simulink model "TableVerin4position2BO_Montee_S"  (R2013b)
settings: Solver=ode15s  StartTime=0.0  StopTime=20  RelTol=1e-3
undefined symbols (not defined in the file): deg, kg, m, mm, N, rad, s, X, Y, Z
libraries: sm_lib x907, fl_lib x19, nesl_utility x13, elec_lib x3, sdl_lib x2
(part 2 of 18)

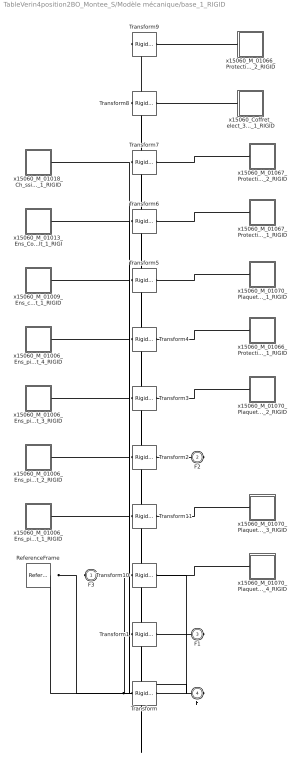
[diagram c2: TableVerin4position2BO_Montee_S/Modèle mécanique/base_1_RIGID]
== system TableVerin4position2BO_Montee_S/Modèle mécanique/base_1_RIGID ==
  ReferenceFrame : sm_lib/Frames and Transforms/Reference Frame  BlockFunction=simmechanics.library.frames_transforms.reference_frame
  Transform : sm_lib/Frames and Transforms/Rigid Transform  TranslationMethod=Cartesian  TranslationLengthUnit=mm  TranslationStandardAxis=+Z  TranslationStandardOffset=0  TranslationCartesianOffset=[-1242 73.964999999999918 -35]  TranslationROffset=0  TranslationROffsetUnits=m  TranslationZOffset=0  TranslationZOffsetUnits=m  TranslationThetaOffset=0  TranslationThetaOffsetUnits=deg  RotationMethod=ArbitraryAxis  RotationAngleUnits=rad  RotationStandardAxis=+Z  RotationAngle=2.0943951023931953  RotationArbitraryAxis=[-0.57735026918962562 -0.57735026918962595 -0.57735026918962562]  FollAlignAxisA=+X  BaseAlignAxisA=+Y  FollAlignAxisB=+Y  BaseAlignAxisB=+Z  BlockFunction=simmechanics.library.frames_transforms.rigid_transform
  Transform1 : sm_lib/Frames and Transforms/Rigid Transform  TranslationMethod=Cartesian  TranslationLengthUnit=mm  TranslationStandardAxis=+Z  TranslationStandardOffset=0  TranslationCartesianOffset=[-1320 -193.8074 -14.000000000000002]  TranslationROffset=0  TranslationROffsetUnits=m  TranslationZOffset=0  TranslationZOffsetUnits=m  TranslationThetaOffset=0  TranslationThetaOffsetUnits=deg  RotationMethod=ArbitraryAxis  RotationAngleUnits=rad  RotationStandardAxis=+Z  RotationAngle=2.0943951023931953  RotationArbitraryAxis=[0.57735026918962584 -0.57735026918962584 0.57735026918962584]  FollAlignAxisA=+X  BaseAlignAxisA=+Y  FollAlignAxisB=+Y  BaseAlignAxisB=+Z  BlockFunction=simmechanics.library.frames_transforms.rigid_transform
  Transform10 : sm_lib/Frames and Transforms/Rigid Transform  TranslationMethod=Cartesian  TranslationLengthUnit=mm  TranslationStandardAxis=+Z  TranslationStandardOffset=0  TranslationCartesianOffset=[-200 -325 -60]  TranslationROffset=0  TranslationROffsetUnits=m  TranslationZOffset=0  TranslationZOffsetUnits=m  TranslationThetaOffset=0  TranslationThetaOffsetUnits=deg  RotationMethod=ArbitraryAxis  RotationAngleUnits=rad  RotationStandardAxis=+Z  RotationAngle=3.1415926535897891  RotationArbitraryAxis=[0 1 0]  FollAlignAxisA=+X  BaseAlignAxisA=+Y  FollAlignAxisB=+Y  BaseAlignAxisB=+Z  BlockFunction=simmechanics.library.frames_transforms.rigid_transform
  Transform11 : sm_lib/Frames and Transforms/Rigid Transform  TranslationMethod=Cartesian  TranslationLengthUnit=mm  TranslationStandardAxis=+Z  TranslationStandardOffset=0  TranslationCartesianOffset=[-200 215 -60]  TranslationROffset=0  TranslationROffsetUnits=m  TranslationZOffset=0  TranslationZOffsetUnits=m  TranslationThetaOffset=0  TranslationThetaOffsetUnits=deg  RotationMethod=ArbitraryAxis  RotationAngleUnits=rad  RotationStandardAxis=+Z  RotationAngle=3.1415926535897891  RotationArbitraryAxis=[0 1 0]  FollAlignAxisA=+X  BaseAlignAxisA=+Y  FollAlignAxisB=+Y  BaseAlignAxisB=+Z  BlockFunction=simmechanics.library.frames_transforms.rigid_transform
  Transform2 : sm_lib/Frames and Transforms/Rigid Transform  TranslationMethod=Cartesian  TranslationLengthUnit=mm  TranslationStandardAxis=+Z  TranslationStandardOffset=0  TranslationCartesianOffset=[-1400 -138.965 121.00000000000195]  TranslationROffset=0  TranslationROffsetUnits=m  TranslationZOffset=0  TranslationZOffsetUnits=m  TranslationThetaOffset=0  TranslationThetaOffsetUnits=deg  RotationMethod=ArbitraryAxis  RotationAngleUnits=rad  RotationStandardAxis=+Z  RotationAngle=2.0943951023931953  RotationArbitraryAxis=[0.57735026918962584 -0.57735026918962584 0.57735026918962584]  FollAlignAxisA=+X  BaseAlignAxisA=+Y  FollAlignAxisB=+Y  BaseAlignAxisB=+Z  BlockFunction=simmechanics.library.frames_transforms.rigid_transform
  Transform3 : sm_lib/Frames and Transforms/Rigid Transform  TranslationMethod=Cartesian  TranslationLengthUnit=mm  TranslationStandardAxis=+Z  TranslationStandardOffset=0  TranslationCartesianOffset=[-550 -325 -60]  TranslationROffset=0  TranslationROffsetUnits=m  TranslationZOffset=0  TranslationZOffsetUnits=m  TranslationThetaOffset=0  TranslationThetaOffsetUnits=deg  RotationMethod=ArbitraryAxis  RotationAngleUnits=rad  RotationStandardAxis=+Z  RotationAngle=3.1415926535897931  RotationArbitraryAxis=[1 -6.2449999999999997e-17 0]  FollAlignAxisA=+X  BaseAlignAxisA=+Y  FollAlignAxisB=+Y  BaseAlignAxisB=+Z  BlockFunction=simmechanics.library.frames_transforms.rigid_transform
  Transform4 : sm_lib/Frames and Transforms/Rigid Transform  TranslationMethod=Cartesian  TranslationLengthUnit=mm  TranslationStandardAxis=+Z  TranslationStandardOffset=0  TranslationCartesianOffset=[-1740 -415 31]  TranslationROffset=0  TranslationROffsetUnits=m  TranslationZOffset=0  TranslationZOffsetUnits=m  TranslationThetaOffset=0  TranslationThetaOffsetUnits=deg  RotationMethod=None  RotationAngleUnits=deg  RotationStandardAxis=+Z  RotationAngle=0  RotationArbitraryAxis=[0 0 1]  FollAlignAxisA=+X  BaseAlignAxisA=+Y  FollAlignAxisB=+Y  BaseAlignAxisB=+Z  BlockFunction=simmechanics.library.frames_transforms.rigid_transform
  Transform5 : sm_lib/Frames and Transforms/Rigid Transform  TranslationMethod=Cartesian  TranslationLengthUnit=mm  TranslationStandardAxis=+Z  TranslationStandardOffset=0  TranslationCartesianOffset=[-550 215 -60]  TranslationROffset=0  TranslationROffsetUnits=m  TranslationZOffset=0  TranslationZOffsetUnits=m  TranslationThetaOffset=0  TranslationThetaOffsetUnits=deg  RotationMethod=ArbitraryAxis  RotationAngleUnits=rad  RotationStandardAxis=+Z  RotationAngle=3.1415926535897896  RotationArbitraryAxis=[-1 -0 -1.99581e-15]  FollAlignAxisA=+X  BaseAlignAxisA=+Y  FollAlignAxisB=+Y  BaseAlignAxisB=+Z  BlockFunction=simmechanics.library.frames_transforms.rigid_transform
  Transform6 : sm_lib/Frames and Transforms/Rigid Transform  TranslationMethod=Cartesian  TranslationLengthUnit=mm  TranslationStandardAxis=+Z  TranslationStandardOffset=0  TranslationCartesianOffset=[20 -415 31]  TranslationROffset=0  TranslationROffsetUnits=m  TranslationZOffset=0  TranslationZOffsetUnits=m  TranslationThetaOffset=0  TranslationThetaOffsetUnits=deg  RotationMethod=ArbitraryAxis  RotationAngleUnits=rad  RotationStandardAxis=+Z  RotationAngle=3.1415926535897931  RotationArbitraryAxis=[0 -1.9146e-15 1]  FollAlignAxisA=+X  BaseAlignAxisA=+Y  FollAlignAxisB=+Y  BaseAlignAxisB=+Z  BlockFunction=simmechanics.library.frames_transforms.rigid_transform
  Transform7 : sm_lib/Frames and Transforms/Rigid Transform  TranslationMethod=Cartesian  TranslationLengthUnit=mm  TranslationStandardAxis=+Z  TranslationStandardOffset=0  TranslationCartesianOffset=[-1740 415 31]  TranslationROffset=0  TranslationROffsetUnits=m  TranslationZOffset=0  TranslationZOffsetUnits=m  TranslationThetaOffset=0  TranslationThetaOffsetUnits=deg  RotationMethod=None  RotationAngleUnits=deg  RotationStandardAxis=+Z  RotationAngle=0  RotationArbitraryAxis=[0 0 1]  FollAlignAxisA=+X  BaseAlignAxisA=+Y  FollAlignAxisB=+Y  BaseAlignAxisB=+Z  BlockFunction=simmechanics.library.frames_transforms.rigid_transform
  Transform8 : sm_lib/Frames and Transforms/Rigid Transform  TranslationMethod=Cartesian  TranslationLengthUnit=mm  TranslationStandardAxis=+Z  TranslationStandardOffset=0  TranslationCartesianOffset=[-760 275 -60]  TranslationROffset=0  TranslationROffsetUnits=m  TranslationZOffset=0  TranslationZOffsetUnits=m  TranslationThetaOffset=0  TranslationThetaOffsetUnits=deg  RotationMethod=ArbitraryAxis  RotationAngleUnits=rad  RotationStandardAxis=+Z  RotationAngle=1.5707963267948968  RotationArbitraryAxis=[-5.5510999999999988e-17 5.5510999999999988e-17 1]  FollAlignAxisA=+X  BaseAlignAxisA=+Y  FollAlignAxisB=+Y  BaseAlignAxisB=+Z  BlockFunction=simmechanics.library.frames_transforms.rigid_transform
  Transform9 : sm_lib/Frames and Transforms/Rigid Transform  TranslationMethod=Cartesian  TranslationLengthUnit=mm  TranslationStandardAxis=+Z  TranslationStandardOffset=0  TranslationCartesianOffset=[20 415 31]  TranslationROffset=0  TranslationROffsetUnits=m  TranslationZOffset=0  TranslationZOffsetUnits=m  TranslationThetaOffset=0  TranslationThetaOffsetUnits=deg  RotationMethod=ArbitraryAxis  RotationAngleUnits=rad  RotationStandardAxis=+Z  RotationAngle=3.1415926535897931  RotationArbitraryAxis=[0 -1.6751650000000001e-15 1]  FollAlignAxisA=+X  BaseAlignAxisA=+Y  FollAlignAxisB=+Y  BaseAlignAxisB=+Z  BlockFunction=simmechanics.library.frames_transforms.rigid_transform
  x15060_Coffret_elect_300_X_150_H_150_AA_DEFAULT_1_RIGID : Subsystem
  x15060_M_01006_Ens_pied_escamotable_Default_1_RIGID : Subsystem
  x15060_M_01006_Ens_pied_escamotable_Default_2_RIGID : Subsystem
  x15060_M_01006_Ens_pied_escamotable_Default_3_RIGID : Subsystem
  x15060_M_01006_Ens_pied_escamotable_Default_4_RIGID : Subsystem
  x15060_M_01009_Ens_chassis_inf_Default_1_RIGID : Subsystem
  x15060_M_01013_Ens_Coffret_electrique_sous_table_Default_1_RIGI : Subsystem
  x15060_M_01018_Ch_ssis_bas_1_RIGID : Subsystem
  x15060_M_01066_Protection_capteur_pied_AA_DEFAULT_1_RIGID : Subsystem
  x15060_M_01066_Protection_capteur_pied_AA_DEFAULT_2_RIGID : Subsystem
  x15060_M_01067_Protection_capteur_pied_SYM_AA_DEFAULT_1_RIGID : Subsystem
  x15060_M_01067_Protection_capteur_pied_SYM_AA_DEFAULT_2_RIGID : Subsystem
  x15060_M_01070_Plaquette_porte_coffret_elect_AA_DEFAULT_1_RIGID : Subsystem
  x15060_M_01070_Plaquette_porte_coffret_elect_AA_DEFAULT_2_RIGID : Subsystem
  x15060_M_01070_Plaquette_porte_coffret_elect_AA_DEFAULT_3_RIGID : Subsystem
  x15060_M_01070_Plaquette_porte_coffret_elect_AA_DEFAULT_4_RIGID : Subsystem
  F3 : PMIOPort  Port=1  Side=Left
  F2 : PMIOPort  Port=2  Side=Right
  F1 : PMIOPort  Port=3  Side=Right
  F : PMIOPort  Port=4  Side=Right
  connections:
  Transform/LConn1 -- ReferenceFrame/RConn1 -- Transform1/LConn1 -- Transform10/LConn1 -- Transform11/LConn1 -- Transform2/LConn1 -- Transform3/LConn1 -- Transform4/LConn1 -- Transform5/LConn1 -- Transform6/LConn1 -- Transform7/LConn1 -- Transform8/LConn1 -- Transform9/LConn1 -- x15060_M_01006_Ens_pied_escamotable_Default_1_RIGID/RConn1 -- x15060_M_01006_Ens_pied_escamotable_Default_2_RIGID/RConn1 -- x15060_M_01006_Ens_pied_escamotable_Default_3_RIGID/RConn1 -- x15060_M_01006_Ens_pied_escamotable_Default_4_RIGID/RConn1 -- x15060_M_01009_Ens_chassis_inf_Default_1_RIGID/RConn1 -- x15060_M_01013_Ens_Coffret_electrique_sous_table_Default_1_RIGI/RConn1 -- x15060_M_01018_Ch_ssis_bas_1_RIGID/RConn1 -- F3/RConn1
  Transform/RConn1 -- F/RConn1
  Transform9/RConn1 -- x15060_M_01066_Protection_capteur_pied_AA_DEFAULT_2_RIGID/LConn1
  Transform10/RConn1 -- x15060_M_01070_Plaquette_porte_coffret_elect_AA_DEFAULT_4_RIGID/LConn1
  Transform11/RConn1 -- x15060_M_01070_Plaquette_porte_coffret_elect_AA_DEFAULT_3_RIGID/LConn1
  Transform1/RConn1 -- F1/RConn1
  Transform2/RConn1 -- F2/RConn1
  Transform3/RConn1 -- x15060_M_01070_Plaquette_porte_coffret_elect_AA_DEFAULT_2_RIGID/LConn1
  Transform4/RConn1 -- x15060_M_01066_Protection_capteur_pied_AA_DEFAULT_1_RIGID/LConn1
  Transform5/RConn1 -- x15060_M_01070_Plaquette_porte_coffret_elect_AA_DEFAULT_1_RIGID/LConn1
  Transform6/RConn1 -- x15060_M_01067_Protection_capteur_pied_SYM_AA_DEFAULT_1_RIGID/LConn1
  Transform7/RConn1 -- x15060_M_01067_Protection_capteur_pied_SYM_AA_DEFAULT_2_RIGID/LConn1
  Transform8/RConn1 -- x15060_Coffret_elect_300_X_150_H_150_AA_DEFAULT_1_RIGID/LConn1

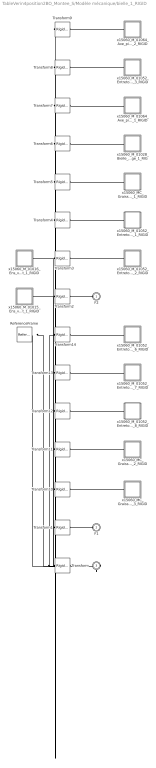
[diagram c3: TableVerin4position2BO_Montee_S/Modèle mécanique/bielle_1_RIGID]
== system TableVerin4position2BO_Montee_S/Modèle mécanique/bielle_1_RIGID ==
  ReferenceFrame : sm_lib/Frames and Transforms/Reference Frame  BlockFunction=simmechanics.library.frames_transforms.reference_frame
  Transform : sm_lib/Frames and Transforms/Rigid Transform  TranslationMethod=Cartesian  TranslationLengthUnit=mm  TranslationStandardAxis=+Z  TranslationStandardOffset=0  TranslationCartesianOffset=[-316.26699999999994 -140.96499999999997 350]  TranslationROffset=0  TranslationROffsetUnits=m  TranslationZOffset=0  TranslationZOffsetUnits=m  TranslationThetaOffset=0  TranslationThetaOffsetUnits=deg  RotationMethod=ArbitraryAxis  RotationAngleUnits=rad  RotationStandardAxis=+Z  RotationAngle=2.0943951023931957  RotationArbitraryAxis=[0.57735026918962584 -0.57735026918962573 0.57735026918962573]  FollAlignAxisA=+X  BaseAlignAxisA=+Y  FollAlignAxisB=+Y  BaseAlignAxisB=+Z  BlockFunction=simmechanics.library.frames_transforms.rigid_transform
  Transform1 : sm_lib/Frames and Transforms/Rigid Transform  TranslationMethod=Cartesian  TranslationLengthUnit=mm  TranslationStandardAxis=+Z  TranslationStandardOffset=0  TranslationCartesianOffset=[-778.76007754271018 -139.46500000002229 0.00028965769951128095]  TranslationROffset=0  TranslationROffsetUnits=m  TranslationZOffset=0  TranslationZOffsetUnits=m  TranslationThetaOffset=0  TranslationThetaOffsetUnits=deg  RotationMethod=ArbitraryAxis  RotationAngleUnits=rad  RotationStandardAxis=+Z  RotationAngle=2.0943951023931953  RotationArbitraryAxis=[0.57735026918962584 -0.57735026918962584 0.57735026918962584]  FollAlignAxisA=+X  BaseAlignAxisA=+Y  FollAlignAxisB=+Y  BaseAlignAxisB=+Z  BlockFunction=simmechanics.library.frames_transforms.rigid_transform
  Transform10 : sm_lib/Frames and Transforms/Rigid Transform  TranslationMethod=Cartesian  TranslationLengthUnit=mm  TranslationStandardAxis=+Z  TranslationStandardOffset=0  TranslationCartesianOffset=[-785.096 9.7691999999999992e-12 8.3727200000000011]  TranslationROffset=0  TranslationROffsetUnits=m  TranslationZOffset=0  TranslationZOffsetUnits=m  TranslationThetaOffset=0  TranslationThetaOffsetUnits=deg  RotationMethod=ArbitraryAxis  RotationAngleUnits=rad  RotationStandardAxis=+Z  RotationAngle=2.4013188770426868  RotationArbitraryAxis=[0.70267924249142677 -0.65170522453176793 -0.28552089676532016]  FollAlignAxisA=+X  BaseAlignAxisA=+Y  FollAlignAxisB=+Y  BaseAlignAxisB=+Z  BlockFunction=simmechanics.library.frames_transforms.rigid_transform
  Transform11 : sm_lib/Frames and Transforms/Rigid Transform  TranslationMethod=Cartesian  TranslationLengthUnit=mm  TranslationStandardAxis=+Z  TranslationStandardOffset=0  TranslationCartesianOffset=[-310.23200000000003 -73 342.02600000000001]  TranslationROffset=0  TranslationROffsetUnits=m  TranslationZOffset=0  TranslationZOffsetUnits=m  TranslationThetaOffset=0  TranslationThetaOffsetUnits=deg  RotationMethod=ArbitraryAxis  RotationAngleUnits=rad  RotationStandardAxis=+Z  RotationAngle=2.9102018676527228  RotationArbitraryAxis=[-0.51648054719757408 -0.70231547164023367 0.48989878818103916]  FollAlignAxisA=+X  BaseAlignAxisA=+Y  FollAlignAxisB=+Y  BaseAlignAxisB=+Z  BlockFunction=simmechanics.library.frames_transforms.rigid_transform
  Transform12 : sm_lib/Frames and Transforms/Rigid Transform  TranslationMethod=Cartesian  TranslationLengthUnit=mm  TranslationStandardAxis=+Z  TranslationStandardOffset=0  TranslationCartesianOffset=[-316.267 105.5 350]  TranslationROffset=0  TranslationROffsetUnits=m  TranslationZOffset=0  TranslationZOffsetUnits=m  TranslationThetaOffset=0  TranslationThetaOffsetUnits=deg  RotationMethod=ArbitraryAxis  RotationAngleUnits=rad  RotationStandardAxis=+Z  RotationAngle=2.793539492072322  RotationArbitraryAxis=[-0.69609360831745681 -0.6960936083174567 0.17580493997372784]  FollAlignAxisA=+X  BaseAlignAxisA=+Y  FollAlignAxisB=+Y  BaseAlignAxisB=+Z  BlockFunction=simmechanics.library.frames_transforms.rigid_transform
  Transform13 : sm_lib/Frames and Transforms/Rigid Transform  TranslationMethod=Cartesian  TranslationLengthUnit=mm  TranslationStandardAxis=+Z  TranslationStandardOffset=0  TranslationCartesianOffset=[-778.75999999999999 -106.5 -8.5598199999999999e-10]  TranslationROffset=0  TranslationROffsetUnits=m  TranslationZOffset=0  TranslationZOffsetUnits=m  TranslationThetaOffset=0  TranslationThetaOffsetUnits=deg  RotationMethod=ArbitraryAxis  RotationAngleUnits=rad  RotationStandardAxis=+Z  RotationAngle=2.793539492072322  RotationArbitraryAxis=[-0.69609360831745681 -0.6960936083174567 0.17580493997372784]  FollAlignAxisA=+X  BaseAlignAxisA=+Y  FollAlignAxisB=+Y  BaseAlignAxisB=+Z  BlockFunction=simmechanics.library.frames_transforms.rigid_transform
  Transform14 : sm_lib/Frames and Transforms/Rigid Transform  TranslationMethod=Cartesian  TranslationLengthUnit=mm  TranslationStandardAxis=+Z  TranslationStandardOffset=0  TranslationCartesianOffset=[-316.267 -27 350]  TranslationROffset=0  TranslationROffsetUnits=m  TranslationZOffset=0  TranslationZOffsetUnits=m  TranslationThetaOffset=0  TranslationThetaOffsetUnits=deg  RotationMethod=ArbitraryAxis  RotationAngleUnits=rad  RotationStandardAxis=+Z  RotationAngle=1.631639801857675  RotationArbitraryAxis=[-0.2394170303444268 -0.2394170303444268 0.94093515778830983]  FollAlignAxisA=+X  BaseAlignAxisA=+Y  FollAlignAxisB=+Y  BaseAlignAxisB=+Z  BlockFunction=simmechanics.library.frames_transforms.rigid_transform
  Transform2 : sm_lib/Frames and Transforms/Rigid Transform  TranslationMethod=Cartesian  TranslationLengthUnit=mm  TranslationStandardAxis=+Z  TranslationStandardOffset=0  TranslationCartesianOffset=[-316.267 127 350]  TranslationROffset=0  TranslationROffsetUnits=m  TranslationZOffset=0  TranslationZOffsetUnits=m  TranslationThetaOffset=0  TranslationThetaOffsetUnits=deg  RotationMethod=ArbitraryAxis  RotationAngleUnits=rad  RotationStandardAxis=+Z  RotationAngle=2.0943951023931957  RotationArbitraryAxis=[0.57735026918962584 -0.57735026918962573 0.57735026918962573]  FollAlignAxisA=+X  BaseAlignAxisA=+Y  FollAlignAxisB=+Y  BaseAlignAxisB=+Z  BlockFunction=simmechanics.library.frames_transforms.rigid_transform
  Transform3 : sm_lib/Frames and Transforms/Rigid Transform  TranslationMethod=Cartesian  TranslationLengthUnit=mm  TranslationStandardAxis=+Z  TranslationStandardOffset=0  TranslationCartesianOffset=[-778.75999999999999 105.5 -8.5609299999999991e-10]  TranslationROffset=0  TranslationROffsetUnits=m  TranslationZOffset=0  TranslationZOffsetUnits=m  TranslationThetaOffset=0  TranslationThetaOffsetUnits=deg  RotationMethod=ArbitraryAxis  RotationAngleUnits=rad  RotationStandardAxis=+Z  RotationAngle=2.8057551749822172  RotationArbitraryAxis=[-0.69687325454044569 -0.69687325454044569 0.16951499701328632]  FollAlignAxisA=+X  BaseAlignAxisA=+Y  FollAlignAxisB=+Y  BaseAlignAxisB=+Z  BlockFunction=simmechanics.library.frames_transforms.rigid_transform
  Transform4 : sm_lib/Frames and Transforms/Rigid Transform  TranslationMethod=Cartesian  TranslationLengthUnit=mm  TranslationStandardAxis=+Z  TranslationStandardOffset=0  TranslationCartesianOffset=[-316.267 -50.5 350]  TranslationROffset=0  TranslationROffsetUnits=m  TranslationZOffset=0  TranslationZOffsetUnits=m  TranslationThetaOffset=0  TranslationThetaOffsetUnits=deg  RotationMethod=ArbitraryAxis  RotationAngleUnits=rad  RotationStandardAxis=+Z  RotationAngle=1.631639801857675  RotationArbitraryAxis=[-0.2394170303444268 -0.2394170303444268 0.94093515778830983]  FollAlignAxisA=+X  BaseAlignAxisA=+Y  FollAlignAxisB=+Y  BaseAlignAxisB=+Z  BlockFunction=simmechanics.library.frames_transforms.rigid_transform
  Transform5 : sm_lib/Frames and Transforms/Rigid Transform  TranslationMethod=Cartesian  TranslationLengthUnit=mm  TranslationStandardAxis=+Z  TranslationStandardOffset=0  TranslationCartesianOffset=[-310.23200000000003 73 342.02600000000001]  TranslationROffset=0  TranslationROffsetUnits=m  TranslationZOffset=0  TranslationZOffsetUnits=m  TranslationThetaOffset=0  TranslationThetaOffsetUnits=deg  RotationMethod=ArbitraryAxis  RotationAngleUnits=rad  RotationStandardAxis=+Z  RotationAngle=2.0858703302929738  RotationArbitraryAxis=[-0.81159259125179828 -0.57448043372600788 0.10625298626941872]  FollAlignAxisA=+X  BaseAlignAxisA=+Y  FollAlignAxisB=+Y  BaseAlignAxisB=+Z  BlockFunction=simmechanics.library.frames_transforms.rigid_transform
  Transform6 : sm_lib/Frames and Transforms/Rigid Transform  TranslationMethod=Cartesian  TranslationLengthUnit=mm  TranslationStandardAxis=+Z  TranslationStandardOffset=0  TranslationCartesianOffset=[-778.75999999999999 0 1.7275099999999998e-10]  TranslationROffset=0  TranslationROffsetUnits=m  TranslationZOffset=0  TranslationZOffsetUnits=m  TranslationThetaOffset=0  TranslationThetaOffsetUnits=deg  RotationMethod=ArbitraryAxis  RotationAngleUnits=rad  RotationStandardAxis=+Z  RotationAngle=3.1401454668224669  RotationArbitraryAxis=[-0.00072359350995129183 0.70710659607036352 0.70710659607036352]  FollAlignAxisA=+X  BaseAlignAxisA=+Y  FollAlignAxisB=+Y  BaseAlignAxisB=+Z  BlockFunction=simmechanics.library.frames_transforms.rigid_transform
  Transform7 : sm_lib/Frames and Transforms/Rigid Transform  TranslationMethod=Cartesian  TranslationLengthUnit=mm  TranslationStandardAxis=+Z  TranslationStandardOffset=0  TranslationCartesianOffset=[-778.75999999999999 1.5 2.1094199999999997e-12]  TranslationROffset=0  TranslationROffsetUnits=m  TranslationZOffset=0  TranslationZOffsetUnits=m  TranslationThetaOffset=0  TranslationThetaOffsetUnits=deg  RotationMethod=ArbitraryAxis  RotationAngleUnits=rad  RotationStandardAxis=+Z  RotationAngle=2.0943951023931953  RotationArbitraryAxis=[0.57735026918962584 0.57735026918962584 0.57735026918962584]  FollAlignAxisA=+X  BaseAlignAxisA=+Y  FollAlignAxisB=+Y  BaseAlignAxisB=+Z  BlockFunction=simmechanics.library.frames_transforms.rigid_transform
  Transform8 : sm_lib/Frames and Transforms/Rigid Transform  TranslationMethod=Cartesian  TranslationLengthUnit=mm  TranslationStandardAxis=+Z  TranslationStandardOffset=0  TranslationCartesianOffset=[-316.267 -107 350]  TranslationROffset=0  TranslationROffsetUnits=m  TranslationZOffset=0  TranslationZOffsetUnits=m  TranslationThetaOffset=0  TranslationThetaOffsetUnits=deg  RotationMethod=ArbitraryAxis  RotationAngleUnits=rad  RotationStandardAxis=+Z  RotationAngle=1.631639801857675  RotationArbitraryAxis=[-0.2394170303444268 -0.2394170303444268 0.94093515778830983]  FollAlignAxisA=+X  BaseAlignAxisA=+Y  FollAlignAxisB=+Y  BaseAlignAxisB=+Z  BlockFunction=simmechanics.library.frames_transforms.rigid_transform
  Transform9 : sm_lib/Frames and Transforms/Rigid Transform  TranslationMethod=Cartesian  TranslationLengthUnit=mm  TranslationStandardAxis=+Z  TranslationStandardOffset=0  TranslationCartesianOffset=[-316.267 -0.5 350]  TranslationROffset=0  TranslationROffsetUnits=m  TranslationZOffset=0  TranslationZOffsetUnits=m  TranslationThetaOffset=0  TranslationThetaOffsetUnits=deg  RotationMethod=ArbitraryAxis  RotationAngleUnits=rad  RotationStandardAxis=+Z  RotationAngle=1.627678660110736  RotationArbitraryAxis=[-0.23193408162721896 -0.23193408162721896 0.94467622154867281]  FollAlignAxisA=+X  BaseAlignAxisA=+Y  FollAlignAxisB=+Y  BaseAlignAxisB=+Z  BlockFunction=simmechanics.library.frames_transforms.rigid_transform
  x15060_MC_Graisseur_droit_M6_D2_11_02_AA_DEFAULT_1_RIGID : Subsystem
  x15060_MC_Graisseur_droit_M6_D2_11_02_AA_DEFAULT_2_RIGID : Subsystem
  x15060_MC_Graisseur_droit_M6_D2_11_02_AA_DEFAULT_3_RIGID : Subsystem
  x15060_M_01015_Ens_verin_levage_Default_1_RIGID : Subsystem
  x15060_M_01016_Ens_verin_inclinaison_Default_1_RIGID : Subsystem
  x15060_M_01028_Bielle_principale_AA_DEFAULT_Brut_dusinage_1_RIG : Subsystem
  x15060_M_01052_Entretoise_pour_axe_AA_DEFAULT_1_RIGID : Subsystem
  x15060_M_01052_Entretoise_pour_axe_AA_DEFAULT_2_RIGID : Subsystem
  x15060_M_01052_Entretoise_pour_axe_AA_DEFAULT_3_RIGID : Subsystem
  x15060_M_01052_Entretoise_pour_axe_AA_DEFAULT_6_RIGID : Subsystem
  x15060_M_01052_Entretoise_pour_axe_AA_DEFAULT_7_RIGID : Subsystem
  x15060_M_01052_Entretoise_pour_axe_AA_DEFAULT_8_RIGID : Subsystem
  x15060_M_01064_Axe_pivot_AA_DEFAULT_1_RIGID : Subsystem
  x15060_M_01064_Axe_pivot_AA_DEFAULT_2_RIGID : Subsystem
  F2 : PMIOPort  Port=1  Side=Left
  F1 : PMIOPort  Port=2  Side=Left
  F : PMIOPort  Port=3  Side=Right
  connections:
  Transform/LConn1 -- ReferenceFrame/RConn1 -- Transform1/LConn1 -- Transform10/LConn1 -- Transform11/LConn1 -- Transform12/LConn1 -- Transform13/LConn1 -- Transform14/LConn1 -- Transform2/LConn1 -- Transform3/LConn1 -- Transform4/LConn1 -- Transform5/LConn1 -- Transform6/LConn1 -- Transform7/LConn1 -- Transform8/LConn1 -- Transform9/LConn1 -- x15060_M_01015_Ens_verin_levage_Default_1_RIGID/RConn1 -- x15060_M_01016_Ens_verin_inclinaison_Default_1_RIGID/RConn1
  Transform/RConn1 -- F/RConn1
  Transform9/RConn1 -- x15060_M_01064_Axe_pivot_AA_DEFAULT_2_RIGID/LConn1
  Transform10/RConn1 -- x15060_MC_Graisseur_droit_M6_D2_11_02_AA_DEFAULT_3_RIGID/LConn1
  Transform11/RConn1 -- x15060_MC_Graisseur_droit_M6_D2_11_02_AA_DEFAULT_2_RIGID/LConn1
  Transform12/RConn1 -- x15060_M_01052_Entretoise_pour_axe_AA_DEFAULT_8_RIGID/LConn1
  Transform13/RConn1 -- x15060_M_01052_Entretoise_pour_axe_AA_DEFAULT_7_RIGID/LConn1
  Transform14/RConn1 -- x15060_M_01052_Entretoise_pour_axe_AA_DEFAULT_6_RIGID/LConn1
  Transform1/RConn1 -- F1/RConn1
  Transform2/RConn1 -- F2/RConn1
  Transform3/RConn1 -- x15060_M_01052_Entretoise_pour_axe_AA_DEFAULT_2_RIGID/LConn1
  Transform4/RConn1 -- x15060_M_01052_Entretoise_pour_axe_AA_DEFAULT_1_RIGID/LConn1
  Transform5/RConn1 -- x15060_MC_Graisseur_droit_M6_D2_11_02_AA_DEFAULT_1_RIGID/LConn1
  Transform6/RConn1 -- x15060_M_01028_Bielle_principale_AA_DEFAULT_Brut_dusinage_1_RIG/LConn1
  Transform7/RConn1 -- x15060_M_01064_Axe_pivot_AA_DEFAULT_1_RIGID/LConn1
  Transform8/RConn1 -- x15060_M_01052_Entretoise_pour_axe_AA_DEFAULT_3_RIGID/LConn1

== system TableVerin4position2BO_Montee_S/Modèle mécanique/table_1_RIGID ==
  ReferenceFrame : sm_lib/Frames and Transforms/Reference Frame  BlockFunction=simmechanics.library.frames_transforms.reference_frame
  Tige_bielle_r_blable_1_RIGID : Subsystem
  Tige_bielle_r_blable_2_RIGID : Subsystem
  Transform : sm_lib/Frames and Transforms/Rigid Transform  TranslationMethod=Cartesian  TranslationLengthUnit=mm  TranslationStandardAxis=+Z  TranslationStandardOffset=0  TranslationCartesianOffset=[-838.18105377463883 -142.69783000000029 384.87994733183064]  TranslationROffset=0  TranslationROffsetUnits=m  TranslationZOffset=0  TranslationZOffsetUnits=m  TranslationThetaOffset=0  TranslationThetaOffsetUnits=deg  RotationMethod=ArbitraryAxis  RotationAngleUnits=deg  RotationStandardAxis=+Z  RotationAngle=90  RotationArbitraryAxis=[1 0 0]  FollAlignAxisA=+X  BaseAlignAxisA=+Y  FollAlignAxisB=+Y  BaseAlignAxisB=+Z  BlockFunction=simmechanics.library.frames_transforms.rigid_transform
  Transform1 : sm_lib/Frames and Transforms/Rigid Transform  TranslationMethod=Cartesian  TranslationLengthUnit=mm  TranslationStandardAxis=+Z  TranslationStandardOffset=0  TranslationCartesianOffset=[-918.17785051976955 -133.66282999999999 519.87994235684323]  TranslationROffset=0  TranslationROffsetUnits=m  TranslationZOffset=0  TranslationZOffsetUnits=m  TranslationThetaOffset=0  TranslationThetaOffsetUnits=deg  RotationMethod=ArbitraryAxis  RotationAngleUnits=rad  RotationStandardAxis=+Z  RotationAngle=2.0943951023931957  RotationArbitraryAxis=[0.57735026918962584 -0.57735026918962573 0.57735026918962573]  FollAlignAxisA=+X  BaseAlignAxisA=+Y  FollAlignAxisB=+Y  BaseAlignAxisB=+Z  BlockFunction=simmechanics.library.frames_transforms.rigid_transform
  Transform2 : sm_lib/Frames and Transforms/Rigid Transform  TranslationMethod=Cartesian  TranslationLengthUnit=mm  TranslationStandardAxis=+Z  TranslationStandardOffset=0  TranslationCartesianOffset=[-838.18105377463883 -142.69783000000029 570.87994733183064]  TranslationROffset=0  TranslationROffsetUnits=m  TranslationZOffset=0  TranslationZOffsetUnits=m  TranslationThetaOffset=0  TranslationThetaOffsetUnits=deg  RotationMethod=ArbitraryAxis  RotationAngleUnits=deg  RotationStandardAxis=+Z  RotationAngle=0  RotationArbitraryAxis=[0 0 0]  FollAlignAxisA=+X  BaseAlignAxisA=+Y  FollAlignAxisB=+Y  BaseAlignAxisB=+Z  BlockFunction=simmechanics.library.frames_transforms.rigid_transform
  corps_bielle_r_glable_1_RIGID : Subsystem
  corps_bielle_r_glable_sym_trique_1_RIGID : Subsystem
  x15060_M_01002_Ens_cadre_Default_1_RIGID : Subsystem
  x15060_M_01014_Ens_plateau_Default_1_RIGID : Subsystem
  x15060_M_01018_Ch_ssis_haut_1_RIGID : Subsystem
  F1 : PMIOPort  Port=1  Side=Left
  F : PMIOPort  Port=2  Side=Left
  F2 : PMIOPort  Port=3  Side=Right
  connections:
  Tige_bielle_r_blable_1_RIGID/RConn1 -- x15060_M_01014_Ens_plateau_Default_1_RIGID/RConn1 -- x15060_M_01018_Ch_ssis_haut_1_RIGID/RConn1 -- x15060_M_01002_Ens_cadre_Default_1_RIGID/RConn1 -- corps_bielle_r_glable_1_RIGID/RConn1 -- Tige_bielle_r_blable_2_RIGID/RConn1 -- ReferenceFrame/RConn1 -- Transform/LConn1 -- Transform2/LConn1 -- corps_bielle_r_glable_sym_trique_1_RIGID/RConn1 -- Transform1/LConn1
  Transform/RConn1 -- F/RConn1
  Transform1/RConn1 -- F1/RConn1
  Transform2/RConn1 -- F2/RConn1

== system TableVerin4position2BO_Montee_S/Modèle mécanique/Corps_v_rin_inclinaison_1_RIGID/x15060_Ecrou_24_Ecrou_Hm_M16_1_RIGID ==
  ReferenceFrame : sm_lib/Frames and Transforms/Reference Frame  BlockFunction=simmechanics.library.frames_transforms.reference_frame
  Solid : sm_lib/Body Elements/Solid  InertiaType=Custom  Mass=0.0210143  MassUnits=kg  CenterOfMass=[0 4 -3.9695699999999997e-10]  CenterOfMassUnits=mm  MomentsOfInertia=[1.2038 2.1874899999999999 1.2038]  MomentsOfInertiaUnits=kg*mm^2  ProductsOfInertia=[0 0 0]  ProductsOfInertiaUnits=kg*mm^2  DensityBased=on  Density=1000  DensityUnits=kg/(m^3)  GraphicType=FromGeometry  MarkerShape=Sphere  MarkerSize=10  MarkerSizeUnits=m  GraphicVisPropType=SimpleVisualProperties  GraphicDiffuseColor=[0.776471 0.756863 0.737255]  GraphicSpecularColor=[0.5 0.5 0.5 1.0]  GraphicAmbientColor=[0.15 0.15 0.15 1.0]  GraphicEmissiveColor=[0.0 0.0 0.0 1.0]  GraphicShininess=75  GraphicOpacity=1  GeometryShape=FromFile  RectangleSize=[1 1]  RectangleSizeUnits=m  BrickDimensions=[1 1 1]  BrickDimensionUnits=m  CylinderRadius=1  CylinderRadiusUnits=m  CylinderLength=1  CylinderLengthUnits=m  SphereRadius=1  SphereRadiusUnits=m  EllipsoidRadii=[1 1 1]  EllipsoidRadiiUnits=m  ExtrusionCrossSection=[1 1; -1 1; -1 -1; 1 -1]  ExtrusionCrossSectionUnits=m  ExtrusionLength=1  ExtrusionLengthUnits=m  PolygonNumSides=3  PolygonOuterRadius=1  PolygonOuterRadiusUnits=m  ExtGeomFileName=15060-Ecrou-_24 - Ecrou Hm M16_Défaut_sldprt.STL  ExtGeomFileUnits=mm  RevolutionCrossSection=[1 1; 1 -1; 2 -1; 2 1]  RevolutionCrossSectionUnits=m  RevolutionExtent=Full  RevolutionAngle=180  RevolutionAngleUnits=deg  BlockFunction=simmechanics.library.body_elements.solid
  F : PMIOPort  Port=1  Side=Left
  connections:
  Solid/RConn1 -- ReferenceFrame/RConn1 -- F/RConn1

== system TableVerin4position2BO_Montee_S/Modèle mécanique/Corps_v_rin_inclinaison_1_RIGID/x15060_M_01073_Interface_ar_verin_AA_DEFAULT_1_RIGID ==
  ReferenceFrame : sm_lib/Frames and Transforms/Reference Frame  BlockFunction=simmechanics.library.frames_transforms.reference_frame
  Solid : sm_lib/Body Elements/Solid  InertiaType=Custom  Mass=0.224909  MassUnits=kg  CenterOfMass=[28.064 0 0]  CenterOfMassUnits=mm  MomentsOfInertia=[30.872299999999999 76.841700000000003 75.723100000000002]  MomentsOfInertiaUnits=kg*mm^2  ProductsOfInertia=[0 0 0]  ProductsOfInertiaUnits=kg*mm^2  DensityBased=on  Density=1000  DensityUnits=kg/(m^3)  GraphicType=FromGeometry  MarkerShape=Sphere  MarkerSize=10  MarkerSizeUnits=m  GraphicVisPropType=SimpleVisualProperties  GraphicDiffuseColor=[0.776471 0.756863 0.737255]  GraphicSpecularColor=[0.5 0.5 0.5 1.0]  GraphicAmbientColor=[0.15 0.15 0.15 1.0]  GraphicEmissiveColor=[0.0 0.0 0.0 1.0]  GraphicShininess=75  GraphicOpacity=1  GeometryShape=FromFile  RectangleSize=[1 1]  RectangleSizeUnits=m  BrickDimensions=[1 1 1]  BrickDimensionUnits=m  CylinderRadius=1  CylinderRadiusUnits=m  CylinderLength=1  CylinderLengthUnits=m  SphereRadius=1  SphereRadiusUnits=m  EllipsoidRadii=[1 1 1]  EllipsoidRadiiUnits=m  ExtrusionCrossSection=[1 1; -1 1; -1 -1; 1 -1]  ExtrusionCrossSectionUnits=m  ExtrusionLength=1  ExtrusionLengthUnits=m  PolygonNumSides=3  PolygonOuterRadius=1  PolygonOuterRadiusUnits=m  ExtGeomFileName=15060-M-01073-Interface ar verin_AA - DEFAULT_Défaut_sldprt.STL  ExtGeomFileUnits=mm  RevolutionCrossSection=[1 1; 1 -1; 2 -1; 2 1]  RevolutionCrossSectionUnits=m  RevolutionExtent=Full  RevolutionAngle=180  RevolutionAngleUnits=deg  BlockFunction=simmechanics.library.body_elements.solid
  F : PMIOPort  Port=1  Side=Left
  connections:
  Solid/RConn1 -- ReferenceFrame/RConn1 -- F/RConn1

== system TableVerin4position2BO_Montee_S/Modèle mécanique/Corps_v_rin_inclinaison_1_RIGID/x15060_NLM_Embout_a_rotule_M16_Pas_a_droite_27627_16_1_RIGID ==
  ReferenceFrame : sm_lib/Frames and Transforms/Reference Frame  BlockFunction=simmechanics.library.frames_transforms.reference_frame
  Solid : sm_lib/Body Elements/Solid  InertiaType=Custom  Mass=0.22046099999999999  MassUnits=kg  CenterOfMass=[13.6563 0 -8.5964900000000008e-06]  CenterOfMassUnits=mm  MomentsOfInertia=[23.439299999999999 136.78299999999999 123.59099999999999]  MomentsOfInertiaUnits=kg*mm^2  ProductsOfInertia=[-4.6663400000000005e-05 4.08513e-05 5.5129399999999994e-05]  ProductsOfInertiaUnits=kg*mm^2  DensityBased=on  Density=1000  DensityUnits=kg/(m^3)  GraphicType=FromGeometry  MarkerShape=Sphere  MarkerSize=10  MarkerSizeUnits=m  GraphicVisPropType=SimpleVisualProperties  GraphicDiffuseColor=[0.776471 0.756863 0.737255]  GraphicSpecularColor=[0.5 0.5 0.5 1.0]  GraphicAmbientColor=[0.15 0.15 0.15 1.0]  GraphicEmissiveColor=[0.0 0.0 0.0 1.0]  GraphicShininess=75  GraphicOpacity=1  GeometryShape=FromFile  RectangleSize=[1 1]  RectangleSizeUnits=m  BrickDimensions=[1 1 1]  BrickDimensionUnits=m  CylinderRadius=1  CylinderRadiusUnits=m  CylinderLength=1  CylinderLengthUnits=m  SphereRadius=1  SphereRadiusUnits=m  EllipsoidRadii=[1 1 1]  EllipsoidRadiiUnits=m  ExtrusionCrossSection=[1 1; -1 1; -1 -1; 1 -1]  ExtrusionCrossSectionUnits=m  ExtrusionLength=1  ExtrusionLengthUnits=m  PolygonNumSides=3  PolygonOuterRadius=1  PolygonOuterRadiusUnits=m  ExtGeomFileName=15060-NLM-Embout a rotule M16 Pas a droite - 27627-16_Défaut_sldprt.STL  ExtGeomFileUnits=mm  RevolutionCrossSection=[1 1; 1 -1; 2 -1; 2 1]  RevolutionCrossSectionUnits=m  RevolutionExtent=Full  RevolutionAngle=180  RevolutionAngleUnits=deg  BlockFunction=simmechanics.library.body_elements.solid
  F : PMIOPort  Port=1  Side=Left
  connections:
  Solid/RConn1 -- ReferenceFrame/RConn1 -- F/RConn1

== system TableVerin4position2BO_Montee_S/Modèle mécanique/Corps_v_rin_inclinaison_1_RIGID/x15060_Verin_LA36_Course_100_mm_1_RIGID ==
  ReferenceFrame : sm_lib/Frames and Transforms/Reference Frame  BlockFunction=simmechanics.library.frames_transforms.reference_frame
  Solid : sm_lib/Body Elements/Solid  InertiaType=Custom  Mass=16.4344  MassUnits=kg  CenterOfMass=[-32.3232 0.0025488500000000001 17.760100000000001]  CenterOfMassUnits=mm  MomentsOfInertia=[90976.899999999994 107643 28123.599999999999]  MomentsOfInertiaUnits=kg*mm^2  ProductsOfInertia=[5.1204799999999997 -235.90300000000005 -1.9517]  ProductsOfInertiaUnits=kg*mm^2  DensityBased=on  Density=1000  DensityUnits=kg/(m^3)  GraphicType=FromGeometry  MarkerShape=Sphere  MarkerSize=10  MarkerSizeUnits=m  GraphicVisPropType=SimpleVisualProperties  GraphicDiffuseColor=[0.647059 0.517647 0]  GraphicSpecularColor=[0.5 0.5 0.5 1.0]  GraphicAmbientColor=[0.15 0.15 0.15 1.0]  GraphicEmissiveColor=[0.0 0.0 0.0 1.0]  GraphicShininess=75  GraphicOpacity=1  GeometryShape=FromFile  RectangleSize=[1 1]  RectangleSizeUnits=m  BrickDimensions=[1 1 1]  BrickDimensionUnits=m  CylinderRadius=1  CylinderRadiusUnits=m  CylinderLength=1  CylinderLengthUnits=m  SphereRadius=1  SphereRadiusUnits=m  EllipsoidRadii=[1 1 1]  EllipsoidRadiiUnits=m  ExtrusionCrossSection=[1 1; -1 1; -1 -1; 1 -1]  ExtrusionCrossSectionUnits=m  ExtrusionLength=1  ExtrusionLengthUnits=m  PolygonNumSides=3  PolygonOuterRadius=1  PolygonOuterRadiusUnits=m  ExtGeomFileName=15060-Verin - LA36 - Course 100 mm_Défaut_sldprt.STL  ExtGeomFileUnits=mm  RevolutionCrossSection=[1 1; 1 -1; 2 -1; 2 1]  RevolutionCrossSectionUnits=m  RevolutionExtent=Full  RevolutionAngle=180  RevolutionAngleUnits=deg  BlockFunction=simmechanics.library.body_elements.solid
  F : PMIOPort  Port=1  Side=Left
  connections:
  Solid/RConn1 -- ReferenceFrame/RConn1 -- F/RConn1

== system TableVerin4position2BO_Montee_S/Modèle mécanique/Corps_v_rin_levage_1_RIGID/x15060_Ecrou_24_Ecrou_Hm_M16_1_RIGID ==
  ReferenceFrame : sm_lib/Frames and Transforms/Reference Frame  BlockFunction=simmechanics.library.frames_transforms.reference_frame
  Solid : sm_lib/Body Elements/Solid  InertiaType=Custom  Mass=0.0210143  MassUnits=kg  CenterOfMass=[0 4 -3.9695699999999997e-10]  CenterOfMassUnits=mm  MomentsOfInertia=[1.2038 2.1874899999999999 1.2038]  MomentsOfInertiaUnits=kg*mm^2  ProductsOfInertia=[0 0 0]  ProductsOfInertiaUnits=kg*mm^2  DensityBased=on  Density=1000  DensityUnits=kg/(m^3)  GraphicType=FromGeometry  MarkerShape=Sphere  MarkerSize=10  MarkerSizeUnits=m  GraphicVisPropType=SimpleVisualProperties  GraphicDiffuseColor=[0.776471 0.756863 0.737255]  GraphicSpecularColor=[0.5 0.5 0.5 1.0]  GraphicAmbientColor=[0.15 0.15 0.15 1.0]  GraphicEmissiveColor=[0.0 0.0 0.0 1.0]  GraphicShininess=75  GraphicOpacity=1  GeometryShape=FromFile  RectangleSize=[1 1]  RectangleSizeUnits=m  BrickDimensions=[1 1 1]  BrickDimensionUnits=m  CylinderRadius=1  CylinderRadiusUnits=m  CylinderLength=1  CylinderLengthUnits=m  SphereRadius=1  SphereRadiusUnits=m  EllipsoidRadii=[1 1 1]  EllipsoidRadiiUnits=m  ExtrusionCrossSection=[1 1; -1 1; -1 -1; 1 -1]  ExtrusionCrossSectionUnits=m  ExtrusionLength=1  ExtrusionLengthUnits=m  PolygonNumSides=3  PolygonOuterRadius=1  PolygonOuterRadiusUnits=m  ExtGeomFileName=15060-Ecrou-_24 - Ecrou Hm M16_Défaut_sldprt.STL  ExtGeomFileUnits=mm  RevolutionCrossSection=[1 1; 1 -1; 2 -1; 2 1]  RevolutionCrossSectionUnits=m  RevolutionExtent=Full  RevolutionAngle=180  RevolutionAngleUnits=deg  BlockFunction=simmechanics.library.body_elements.solid
  F : PMIOPort  Port=1  Side=Left
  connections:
  Solid/RConn1 -- ReferenceFrame/RConn1 -- F/RConn1

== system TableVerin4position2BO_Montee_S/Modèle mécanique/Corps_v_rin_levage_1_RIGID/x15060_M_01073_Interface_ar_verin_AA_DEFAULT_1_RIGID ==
  ReferenceFrame : sm_lib/Frames and Transforms/Reference Frame  BlockFunction=simmechanics.library.frames_transforms.reference_frame
  Solid : sm_lib/Body Elements/Solid  InertiaType=Custom  Mass=0.224909  MassUnits=kg  CenterOfMass=[28.064 0 0]  CenterOfMassUnits=mm  MomentsOfInertia=[30.872299999999999 76.841700000000003 75.723100000000002]  MomentsOfInertiaUnits=kg*mm^2  ProductsOfInertia=[0 0 0]  ProductsOfInertiaUnits=kg*mm^2  DensityBased=on  Density=1000  DensityUnits=kg/(m^3)  GraphicType=FromGeometry  MarkerShape=Sphere  MarkerSize=10  MarkerSizeUnits=m  GraphicVisPropType=SimpleVisualProperties  GraphicDiffuseColor=[0.776471 0.756863 0.737255]  GraphicSpecularColor=[0.5 0.5 0.5 1.0]  GraphicAmbientColor=[0.15 0.15 0.15 1.0]  GraphicEmissiveColor=[0.0 0.0 0.0 1.0]  GraphicShininess=75  GraphicOpacity=1  GeometryShape=FromFile  RectangleSize=[1 1]  RectangleSizeUnits=m  BrickDimensions=[1 1 1]  BrickDimensionUnits=m  CylinderRadius=1  CylinderRadiusUnits=m  CylinderLength=1  CylinderLengthUnits=m  SphereRadius=1  SphereRadiusUnits=m  EllipsoidRadii=[1 1 1]  EllipsoidRadiiUnits=m  ExtrusionCrossSection=[1 1; -1 1; -1 -1; 1 -1]  ExtrusionCrossSectionUnits=m  ExtrusionLength=1  ExtrusionLengthUnits=m  PolygonNumSides=3  PolygonOuterRadius=1  PolygonOuterRadiusUnits=m  ExtGeomFileName=15060-M-01073-Interface ar verin_AA - DEFAULT_Défaut_sldprt.STL  ExtGeomFileUnits=mm  RevolutionCrossSection=[1 1; 1 -1; 2 -1; 2 1]  RevolutionCrossSectionUnits=m  RevolutionExtent=Full  RevolutionAngle=180  RevolutionAngleUnits=deg  BlockFunction=simmechanics.library.body_elements.solid
  F : PMIOPort  Port=1  Side=Left
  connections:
  Solid/RConn1 -- ReferenceFrame/RConn1 -- F/RConn1

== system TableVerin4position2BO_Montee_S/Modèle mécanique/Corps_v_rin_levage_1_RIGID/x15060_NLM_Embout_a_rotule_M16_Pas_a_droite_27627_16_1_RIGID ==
  ReferenceFrame : sm_lib/Frames and Transforms/Reference Frame  BlockFunction=simmechanics.library.frames_transforms.reference_frame
  Solid : sm_lib/Body Elements/Solid  InertiaType=Custom  Mass=0.22046099999999999  MassUnits=kg  CenterOfMass=[13.6563 0 -8.5964900000000008e-06]  CenterOfMassUnits=mm  MomentsOfInertia=[23.439299999999999 136.78299999999999 123.59099999999999]  MomentsOfInertiaUnits=kg*mm^2  ProductsOfInertia=[-4.6663400000000005e-05 4.08513e-05 5.5129399999999994e-05]  ProductsOfInertiaUnits=kg*mm^2  DensityBased=on  Density=1000  DensityUnits=kg/(m^3)  GraphicType=FromGeometry  MarkerShape=Sphere  MarkerSize=10  MarkerSizeUnits=m  GraphicVisPropType=SimpleVisualProperties  GraphicDiffuseColor=[0.776471 0.756863 0.737255]  GraphicSpecularColor=[0.5 0.5 0.5 1.0]  GraphicAmbientColor=[0.15 0.15 0.15 1.0]  GraphicEmissiveColor=[0.0 0.0 0.0 1.0]  GraphicShininess=75  GraphicOpacity=1  GeometryShape=FromFile  RectangleSize=[1 1]  RectangleSizeUnits=m  BrickDimensions=[1 1 1]  BrickDimensionUnits=m  CylinderRadius=1  CylinderRadiusUnits=m  CylinderLength=1  CylinderLengthUnits=m  SphereRadius=1  SphereRadiusUnits=m  EllipsoidRadii=[1 1 1]  EllipsoidRadiiUnits=m  ExtrusionCrossSection=[1 1; -1 1; -1 -1; 1 -1]  ExtrusionCrossSectionUnits=m  ExtrusionLength=1  ExtrusionLengthUnits=m  PolygonNumSides=3  PolygonOuterRadius=1  PolygonOuterRadiusUnits=m  ExtGeomFileName=15060-NLM-Embout a rotule M16 Pas a droite - 27627-16_Défaut_sldprt.STL  ExtGeomFileUnits=mm  RevolutionCrossSection=[1 1; 1 -1; 2 -1; 2 1]  RevolutionCrossSectionUnits=m  RevolutionExtent=Full  RevolutionAngle=180  RevolutionAngleUnits=deg  BlockFunction=simmechanics.library.body_elements.solid
  F : PMIOPort  Port=1  Side=Left
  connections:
  Solid/RConn1 -- ReferenceFrame/RConn1 -- F/RConn1

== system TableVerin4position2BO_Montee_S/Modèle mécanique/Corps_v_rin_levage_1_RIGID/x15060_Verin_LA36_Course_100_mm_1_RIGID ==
  ReferenceFrame : sm_lib/Frames and Transforms/Reference Frame  BlockFunction=simmechanics.library.frames_transforms.reference_frame
  Solid : sm_lib/Body Elements/Solid  InertiaType=Custom  Mass=16.4344  MassUnits=kg  CenterOfMass=[-32.3232 0.0025488500000000001 17.760100000000001]  CenterOfMassUnits=mm  MomentsOfInertia=[90976.899999999994 107643 28123.599999999999]  MomentsOfInertiaUnits=kg*mm^2  ProductsOfInertia=[5.1204799999999997 -235.90300000000005 -1.9517]  ProductsOfInertiaUnits=kg*mm^2  DensityBased=on  Density=1000  DensityUnits=kg/(m^3)  GraphicType=FromGeometry  MarkerShape=Sphere  MarkerSize=10  MarkerSizeUnits=m  GraphicVisPropType=SimpleVisualProperties  GraphicDiffuseColor=[0.647059 0.517647 0]  GraphicSpecularColor=[0.5 0.5 0.5 1.0]  GraphicAmbientColor=[0.15 0.15 0.15 1.0]  GraphicEmissiveColor=[0.0 0.0 0.0 1.0]  GraphicShininess=75  GraphicOpacity=1  GeometryShape=FromFile  RectangleSize=[1 1]  RectangleSizeUnits=m  BrickDimensions=[1 1 1]  BrickDimensionUnits=m  CylinderRadius=1  CylinderRadiusUnits=m  CylinderLength=1  CylinderLengthUnits=m  SphereRadius=1  SphereRadiusUnits=m  EllipsoidRadii=[1 1 1]  EllipsoidRadiiUnits=m  ExtrusionCrossSection=[1 1; -1 1; -1 -1; 1 -1]  ExtrusionCrossSectionUnits=m  ExtrusionLength=1  ExtrusionLengthUnits=m  PolygonNumSides=3  PolygonOuterRadius=1  PolygonOuterRadiusUnits=m  ExtGeomFileName=15060-Verin - LA36 - Course 100 mm_Défaut_sldprt.STL  ExtGeomFileUnits=mm  RevolutionCrossSection=[1 1; 1 -1; 2 -1; 2 1]  RevolutionCrossSectionUnits=m  RevolutionExtent=Full  RevolutionAngle=180  RevolutionAngleUnits=deg  BlockFunction=simmechanics.library.body_elements.solid
  F : PMIOPort  Port=1  Side=Left
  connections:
  Solid/RConn1 -- ReferenceFrame/RConn1 -- F/RConn1

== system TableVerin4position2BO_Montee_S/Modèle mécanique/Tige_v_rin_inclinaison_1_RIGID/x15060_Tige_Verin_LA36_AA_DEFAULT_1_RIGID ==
  ReferenceFrame : sm_lib/Frames and Transforms/Reference Frame  BlockFunction=simmechanics.library.frames_transforms.reference_frame
  Solid : sm_lib/Body Elements/Solid  InertiaType=Custom  Mass=1.0865400000000001  MassUnits=kg  CenterOfMass=[100.095 0 0]  CenterOfMassUnits=mm  MomentsOfInertia=[122.032 3676.6300000000001 3676.6300000000001]  MomentsOfInertiaUnits=kg*mm^2  ProductsOfInertia=[0 0 0]  ProductsOfInertiaUnits=kg*mm^2  DensityBased=on  Density=1000  DensityUnits=kg/(m^3)  GraphicType=FromGeometry  MarkerShape=Sphere  MarkerSize=10  MarkerSizeUnits=m  GraphicVisPropType=SimpleVisualProperties  GraphicDiffuseColor=[0.776471 0.756863 0.737255]  GraphicSpecularColor=[0.5 0.5 0.5 1.0]  GraphicAmbientColor=[0.15 0.15 0.15 1.0]  GraphicEmissiveColor=[0.0 0.0 0.0 1.0]  GraphicShininess=75  GraphicOpacity=1  GeometryShape=FromFile  RectangleSize=[1 1]  RectangleSizeUnits=m  BrickDimensions=[1 1 1]  BrickDimensionUnits=m  CylinderRadius=1  CylinderRadiusUnits=m  CylinderLength=1  CylinderLengthUnits=m  SphereRadius=1  SphereRadiusUnits=m  EllipsoidRadii=[1 1 1]  EllipsoidRadiiUnits=m  ExtrusionCrossSection=[1 1; -1 1; -1 -1; 1 -1]  ExtrusionCrossSectionUnits=m  ExtrusionLength=1  ExtrusionLengthUnits=m  PolygonNumSides=3  PolygonOuterRadius=1  PolygonOuterRadiusUnits=m  ExtGeomFileName=15060-Tige Verin - LA36_AA - DEFAULT_Défaut_sldprt.STL  ExtGeomFileUnits=mm  RevolutionCrossSection=[1 1; 1 -1; 2 -1; 2 1]  RevolutionCrossSectionUnits=m  RevolutionExtent=Full  RevolutionAngle=180  RevolutionAngleUnits=deg  BlockFunction=simmechanics.library.body_elements.solid
  F : PMIOPort  Port=1  Side=Left
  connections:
  Solid/RConn1 -- ReferenceFrame/RConn1 -- F/RConn1

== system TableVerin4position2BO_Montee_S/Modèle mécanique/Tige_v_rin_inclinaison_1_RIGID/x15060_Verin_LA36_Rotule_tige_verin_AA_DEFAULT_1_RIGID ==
  ReferenceFrame : sm_lib/Frames and Transforms/Reference Frame  BlockFunction=simmechanics.library.frames_transforms.reference_frame
  Solid : sm_lib/Body Elements/Solid  InertiaType=Custom  Mass=0.218778  MassUnits=kg  CenterOfMass=[17.366699999999998 -1.65342e-06 4.7137100000000001e-06]  CenterOfMassUnits=mm  MomentsOfInertia=[24.659199999999998 72.896000000000001 84.362000000000009]  MomentsOfInertiaUnits=kg*mm^2  ProductsOfInertia=[-4.0241599999999998e-05 3.5702500000000002e-06 -2.8363700000000001e-06]  ProductsOfInertiaUnits=kg*mm^2  DensityBased=on  Density=1000  DensityUnits=kg/(m^3)  GraphicType=FromGeometry  MarkerShape=Sphere  MarkerSize=10  MarkerSizeUnits=m  GraphicVisPropType=SimpleVisualProperties  GraphicDiffuseColor=[0.776471 0.756863 0.737255]  GraphicSpecularColor=[0.5 0.5 0.5 1.0]  GraphicAmbientColor=[0.15 0.15 0.15 1.0]  GraphicEmissiveColor=[0.0 0.0 0.0 1.0]  GraphicShininess=75  GraphicOpacity=1  GeometryShape=FromFile  RectangleSize=[1 1]  RectangleSizeUnits=m  BrickDimensions=[1 1 1]  BrickDimensionUnits=m  CylinderRadius=1  CylinderRadiusUnits=m  CylinderLength=1  CylinderLengthUnits=m  SphereRadius=1  SphereRadiusUnits=m  EllipsoidRadii=[1 1 1]  EllipsoidRadiiUnits=m  ExtrusionCrossSection=[1 1; -1 1; -1 -1; 1 -1]  ExtrusionCrossSectionUnits=m  ExtrusionLength=1  ExtrusionLengthUnits=m  PolygonNumSides=3  PolygonOuterRadius=1  PolygonOuterRadiusUnits=m  ExtGeomFileName=15060-Verin - LA36 - Rotule tige verin_AA - DEFAULT_Défaut_sldprt.STL  ExtGeomFileUnits=mm  RevolutionCrossSection=[1 1; 1 -1; 2 -1; 2 1]  RevolutionCrossSectionUnits=m  RevolutionExtent=Full  RevolutionAngle=180  RevolutionAngleUnits=deg  BlockFunction=simmechanics.library.body_elements.solid
  F : PMIOPort  Port=1  Side=Left
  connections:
  Solid/RConn1 -- ReferenceFrame/RConn1 -- F/RConn1

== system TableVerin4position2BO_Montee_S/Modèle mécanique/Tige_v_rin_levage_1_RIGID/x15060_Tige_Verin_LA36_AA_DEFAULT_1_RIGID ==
  ReferenceFrame : sm_lib/Frames and Transforms/Reference Frame  BlockFunction=simmechanics.library.frames_transforms.reference_frame
  Solid : sm_lib/Body Elements/Solid  InertiaType=Custom  Mass=1.0865400000000001  MassUnits=kg  CenterOfMass=[100.095 0 0]  CenterOfMassUnits=mm  MomentsOfInertia=[122.032 3676.6300000000001 3676.6300000000001]  MomentsOfInertiaUnits=kg*mm^2  ProductsOfInertia=[0 0 0]  ProductsOfInertiaUnits=kg*mm^2  DensityBased=on  Density=1000  DensityUnits=kg/(m^3)  GraphicType=FromGeometry  MarkerShape=Sphere  MarkerSize=10  MarkerSizeUnits=m  GraphicVisPropType=SimpleVisualProperties  GraphicDiffuseColor=[0.776471 0.756863 0.737255]  GraphicSpecularColor=[0.5 0.5 0.5 1.0]  GraphicAmbientColor=[0.15 0.15 0.15 1.0]  GraphicEmissiveColor=[0.0 0.0 0.0 1.0]  GraphicShininess=75  GraphicOpacity=1  GeometryShape=FromFile  RectangleSize=[1 1]  RectangleSizeUnits=m  BrickDimensions=[1 1 1]  BrickDimensionUnits=m  CylinderRadius=1  CylinderRadiusUnits=m  CylinderLength=1  CylinderLengthUnits=m  SphereRadius=1  SphereRadiusUnits=m  EllipsoidRadii=[1 1 1]  EllipsoidRadiiUnits=m  ExtrusionCrossSection=[1 1; -1 1; -1 -1; 1 -1]  ExtrusionCrossSectionUnits=m  ExtrusionLength=1  ExtrusionLengthUnits=m  PolygonNumSides=3  PolygonOuterRadius=1  PolygonOuterRadiusUnits=m  ExtGeomFileName=15060-Tige Verin - LA36_AA - DEFAULT_Défaut_sldprt.STL  ExtGeomFileUnits=mm  RevolutionCrossSection=[1 1; 1 -1; 2 -1; 2 1]  RevolutionCrossSectionUnits=m  RevolutionExtent=Full  RevolutionAngle=180  RevolutionAngleUnits=deg  BlockFunction=simmechanics.library.body_elements.solid
  F : PMIOPort  Port=1  Side=Left
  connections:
  Solid/RConn1 -- ReferenceFrame/RConn1 -- F/RConn1
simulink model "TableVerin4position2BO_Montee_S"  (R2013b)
settings: Solver=ode15s  StartTime=0.0  StopTime=20  RelTol=1e-3
undefined symbols (not defined in the file): deg, kg, m, mm, N, rad, s, X, Y, Z
libraries: sm_lib x907, fl_lib x19, nesl_utility x13, elec_lib x3, sdl_lib x2
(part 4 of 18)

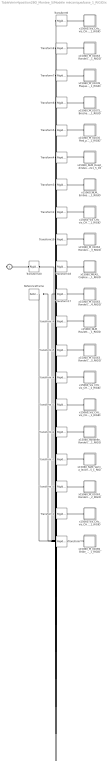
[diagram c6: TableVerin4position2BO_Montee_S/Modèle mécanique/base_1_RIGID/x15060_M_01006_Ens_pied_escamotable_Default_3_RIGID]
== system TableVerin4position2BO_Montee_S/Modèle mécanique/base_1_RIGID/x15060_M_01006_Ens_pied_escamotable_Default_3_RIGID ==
  ReferenceFrame : sm_lib/Frames and Transforms/Reference Frame  BlockFunction=simmechanics.library.frames_transforms.reference_frame
  Transform : sm_lib/Frames and Transforms/Rigid Transform  TranslationMethod=Cartesian  TranslationLengthUnit=mm  TranslationStandardAxis=+Z  TranslationStandardOffset=0  TranslationCartesianOffset=[-28 52.5 1]  TranslationROffset=0  TranslationROffsetUnits=m  TranslationZOffset=0  TranslationZOffsetUnits=m  TranslationThetaOffset=0  TranslationThetaOffsetUnits=deg  RotationMethod=ArbitraryAxis  RotationAngleUnits=rad  RotationStandardAxis=+Z  RotationAngle=2.0943951023931926  RotationArbitraryAxis=[-0.57735026918962484 0.57735026918962484 0.57735026918962762]  FollAlignAxisA=+X  BaseAlignAxisA=+Y  FollAlignAxisB=+Y  BaseAlignAxisB=+Z  BlockFunction=simmechanics.library.frames_transforms.rigid_transform
  Transform1 : sm_lib/Frames and Transforms/Rigid Transform  TranslationMethod=Cartesian  TranslationLengthUnit=mm  TranslationStandardAxis=+Z  TranslationStandardOffset=0  TranslationCartesianOffset=[-2 130 -15]  TranslationROffset=0  TranslationROffsetUnits=m  TranslationZOffset=0  TranslationZOffsetUnits=m  TranslationThetaOffset=0  TranslationThetaOffsetUnits=deg  RotationMethod=ArbitraryAxis  RotationAngleUnits=rad  RotationStandardAxis=+Z  RotationAngle=1.8468790707046723  RotationArbitraryAxis=[-0.46281772058563114 0.7560420061238935 -0.46281772058563114]  FollAlignAxisA=+X  BaseAlignAxisA=+Y  FollAlignAxisB=+Y  BaseAlignAxisB=+Z  BlockFunction=simmechanics.library.frames_transforms.rigid_transform
  Transform10 : sm_lib/Frames and Transforms/Rigid Transform  TranslationMethod=Cartesian  TranslationLengthUnit=mm  TranslationStandardAxis=+Z  TranslationStandardOffset=0  TranslationCartesianOffset=[-8 1 1]  TranslationROffset=0  TranslationROffsetUnits=m  TranslationZOffset=0  TranslationZOffsetUnits=m  TranslationThetaOffset=0  TranslationThetaOffsetUnits=deg  RotationMethod=ArbitraryAxis  RotationAngleUnits=rad  RotationStandardAxis=+Z  RotationAngle=2.5503618214833885  RotationArbitraryAxis=[0.67351920895470851 -0.6735192089547084 0.30453858595923028]  FollAlignAxisA=+X  BaseAlignAxisA=+Y  FollAlignAxisB=+Y  BaseAlignAxisB=+Z  BlockFunction=simmechanics.library.frames_transforms.rigid_transform
  Transform11 : sm_lib/Frames and Transforms/Rigid Transform  TranslationMethod=Cartesian  TranslationLengthUnit=mm  TranslationStandardAxis=+Z  TranslationStandardOffset=0  TranslationCartesianOffset=[-2 1 1]  TranslationROffset=0  TranslationROffsetUnits=m  TranslationZOffset=0  TranslationZOffsetUnits=m  TranslationThetaOffset=0  TranslationThetaOffsetUnits=deg  RotationMethod=ArbitraryAxis  RotationAngleUnits=rad  RotationStandardAxis=+Z  RotationAngle=0.78539829157538132  RotationArbitraryAxis=[-1 0 0]  FollAlignAxisA=+X  BaseAlignAxisA=+Y  FollAlignAxisB=+Y  BaseAlignAxisB=+Z  BlockFunction=simmechanics.library.frames_transforms.rigid_transform
  Transform12 : sm_lib/Frames and Transforms/Rigid Transform  TranslationMethod=Cartesian  TranslationLengthUnit=mm  TranslationStandardAxis=+Z  TranslationStandardOffset=0  TranslationCartesianOffset=[-69.299999999999997 1 1]  TranslationROffset=0  TranslationROffsetUnits=m  TranslationZOffset=0  TranslationZOffsetUnits=m  TranslationThetaOffset=0  TranslationThetaOffsetUnits=deg  RotationMethod=ArbitraryAxis  RotationAngleUnits=rad  RotationStandardAxis=+Z  RotationAngle=1.779666102874204  RotationArbitraryAxis=[-0.41441858134901061 -0.41441858134901077 -0.81025581075691555]  FollAlignAxisA=+X  BaseAlignAxisA=+Y  FollAlignAxisB=+Y  BaseAlignAxisB=+Z  BlockFunction=simmechanics.library.frames_transforms.rigid_transform
  Transform13 : sm_lib/Frames and Transforms/Rigid Transform  TranslationMethod=Cartesian  TranslationLengthUnit=mm  TranslationStandardAxis=+Z  TranslationStandardOffset=0  TranslationCartesianOffset=[23.5107 45 115]  TranslationROffset=0  TranslationROffsetUnits=m  TranslationZOffset=0  TranslationZOffsetUnits=m  TranslationThetaOffset=0  TranslationThetaOffsetUnits=deg  RotationMethod=ArbitraryAxis  RotationAngleUnits=rad  RotationStandardAxis=+Z  RotationAngle=1.7576864373908556  RotationArbitraryAxis=[0.39584132832668711 -0.82862493661313852 -0.39584132832668711]  FollAlignAxisA=+X  BaseAlignAxisA=+Y  FollAlignAxisB=+Y  BaseAlignAxisB=+Z  BlockFunction=simmechanics.library.frames_transforms.rigid_transform
  Transform14 : sm_lib/Frames and Transforms/Rigid Transform  TranslationMethod=Cartesian  TranslationLengthUnit=mm  TranslationStandardAxis=+Z  TranslationStandardOffset=0  TranslationCartesianOffset=[-2 -15 130]  TranslationROffset=0  TranslationROffsetUnits=m  TranslationZOffset=0  TranslationZOffsetUnits=m  TranslationThetaOffset=0  TranslationThetaOffsetUnits=deg  RotationMethod=ArbitraryAxis  RotationAngleUnits=rad  RotationStandardAxis=+Z  RotationAngle=1.8958525166545865  RotationArbitraryAxis=[-0.49199382426247901 0.7182507596760076 -0.49199382426247901]  FollAlignAxisA=+X  BaseAlignAxisA=+Y  FollAlignAxisB=+Y  BaseAlignAxisB=+Z  BlockFunction=simmechanics.library.frames_transforms.rigid_transform
  Transform15 : sm_lib/Frames and Transforms/Rigid Transform  TranslationMethod=Cartesian  TranslationLengthUnit=mm  TranslationStandardAxis=+Z  TranslationStandardOffset=0  TranslationCartesianOffset=[-7.0000000000000009 1 1]  TranslationROffset=0  TranslationROffsetUnits=m  TranslationZOffset=0  TranslationZOffsetUnits=m  TranslationThetaOffset=0  TranslationThetaOffsetUnits=deg  RotationMethod=ArbitraryAxis  RotationAngleUnits=rad  RotationStandardAxis=+Z  RotationAngle=2.5773215317098641  RotationArbitraryAxis=[0.6767483296554524 -0.67674832965545229 0.28986789511277461]  FollAlignAxisA=+X  BaseAlignAxisA=+Y  FollAlignAxisB=+Y  BaseAlignAxisB=+Z  BlockFunction=simmechanics.library.frames_transforms.rigid_transform
  Transform16 : sm_lib/Frames and Transforms/Rigid Transform  TranslationMethod=Cartesian  TranslationLengthUnit=mm  TranslationStandardAxis=+Z  TranslationStandardOffset=0  TranslationCartesianOffset=[73.5 50 85]  TranslationROffset=0  TranslationROffsetUnits=m  TranslationZOffset=0  TranslationZOffsetUnits=m  TranslationThetaOffset=0  TranslationThetaOffsetUnits=deg  RotationMethod=ArbitraryAxis  RotationAngleUnits=rad  RotationStandardAxis=+Z  RotationAngle=1.5707963267948968  RotationArbitraryAxis=[0 0 1]  FollAlignAxisA=+X  BaseAlignAxisA=+Y  FollAlignAxisB=+Y  BaseAlignAxisB=+Z  BlockFunction=simmechanics.library.frames_transforms.rigid_transform
  Transform17 : sm_lib/Frames and Transforms/Rigid Transform  TranslationMethod=Cartesian  TranslationLengthUnit=mm  TranslationStandardAxis=+Z  TranslationStandardOffset=0  TranslationCartesianOffset=[-9 1 1]  TranslationROffset=0  TranslationROffsetUnits=m  TranslationZOffset=0  TranslationZOffsetUnits=m  TranslationThetaOffset=0  TranslationThetaOffsetUnits=deg  RotationMethod=ArbitraryAxis  RotationAngleUnits=rad  RotationStandardAxis=+Z  RotationAngle=2.5503618214833885  RotationArbitraryAxis=[0.67351920895470851 -0.6735192089547084 0.30453858595923028]  FollAlignAxisA=+X  BaseAlignAxisA=+Y  FollAlignAxisB=+Y  BaseAlignAxisB=+Z  BlockFunction=simmechanics.library.frames_transforms.rigid_transform
  Transform18 : sm_lib/Frames and Transforms/Rigid Transform  TranslationMethod=Cartesian  TranslationLengthUnit=mm  TranslationStandardAxis=+Z  TranslationStandardOffset=0  TranslationCartesianOffset=[14 1 1]  TranslationROffset=0  TranslationROffsetUnits=m  TranslationZOffset=0  TranslationZOffsetUnits=m  TranslationThetaOffset=0  TranslationThetaOffsetUnits=deg  RotationMethod=ArbitraryAxis  RotationAngleUnits=rad  RotationStandardAxis=+Z  RotationAngle=2.0943951023931953  RotationArbitraryAxis=[-0.57735026918962584 0.57735026918962584 0.57735026918962584]  FollAlignAxisA=+X  BaseAlignAxisA=+Y  FollAlignAxisB=+Y  BaseAlignAxisB=+Z  BlockFunction=simmechanics.library.frames_transforms.rigid_transform
  Transform19 : sm_lib/Frames and Transforms/Rigid Transform  TranslationMethod=Cartesian  TranslationLengthUnit=mm  TranslationStandardAxis=+Z  TranslationStandardOffset=0  TranslationCartesianOffset=[-6 1 1]  TranslationROffset=0  TranslationROffsetUnits=m  TranslationZOffset=0  TranslationZOffsetUnits=m  TranslationThetaOffset=0  TranslationThetaOffsetUnits=deg  RotationMethod=ArbitraryAxis  RotationAngleUnits=rad  RotationStandardAxis=+Z  RotationAngle=2.5773215317098641  RotationArbitraryAxis=[0.6767483296554524 -0.6767483296554524 0.28986789511277455]  FollAlignAxisA=+X  BaseAlignAxisA=+Y  FollAlignAxisB=+Y  BaseAlignAxisB=+Z  BlockFunction=simmechanics.library.frames_transforms.rigid_transform
  Transform2 : sm_lib/Frames and Transforms/Rigid Transform  TranslationMethod=Cartesian  TranslationLengthUnit=mm  TranslationStandardAxis=+Z  TranslationStandardOffset=0  TranslationCartesianOffset=[-75.300000000000011 1 1]  TranslationROffset=0  TranslationROffsetUnits=m  TranslationZOffset=0  TranslationZOffsetUnits=m  TranslationThetaOffset=0  TranslationThetaOffsetUnits=deg  RotationMethod=ArbitraryAxis  RotationAngleUnits=rad  RotationStandardAxis=+Z  RotationAngle=2.533359793208557  RotationArbitraryAxis=[-0.67137794896695524 0.31385235267853073 -0.67137794896695535]  FollAlignAxisA=+X  BaseAlignAxisA=+Y  FollAlignAxisB=+Y  BaseAlignAxisB=+Z  BlockFunction=simmechanics.library.frames_transforms.rigid_transform
  Transform20 : sm_lib/Frames and Transforms/Rigid Transform  TranslationMethod=Cartesian  TranslationLengthUnit=mm  TranslationStandardAxis=+Z  TranslationStandardOffset=0  TranslationCartesianOffset=[-15 -380 33]  TranslationROffset=0  TranslationROffsetUnits=m  TranslationZOffset=0  TranslationZOffsetUnits=m  TranslationThetaOffset=0  TranslationThetaOffsetUnits=deg  RotationMethod=ArbitraryAxis  RotationAngleUnits=rad  RotationStandardAxis=+Z  RotationAngle=2.0943951023931926  RotationArbitraryAxis=[-0.57735026918962629 0.57735026918962473 0.57735026918962629]  FollAlignAxisA=+X  BaseAlignAxisA=+Y  FollAlignAxisB=+Y  BaseAlignAxisB=+Z  BlockFunction=simmechanics.library.frames_transforms.rigid_transform
  Transform3 : sm_lib/Frames and Transforms/Rigid Transform  TranslationMethod=Cartesian  TranslationLengthUnit=mm  TranslationStandardAxis=+Z  TranslationStandardOffset=0  TranslationCartesianOffset=[104 1 1]  TranslationROffset=0  TranslationROffsetUnits=m  TranslationZOffset=0  TranslationZOffsetUnits=m  TranslationThetaOffset=0  TranslationThetaOffsetUnits=deg  RotationMethod=ArbitraryAxis  RotationAngleUnits=rad  RotationStandardAxis=+Z  RotationAngle=2.8467308529659632  RotationArbitraryAxis=[-0.6992657722290897 0.6992657722290897 0.14850844951621375]  FollAlignAxisA=+X  BaseAlignAxisA=+Y  FollAlignAxisB=+Y  BaseAlignAxisB=+Z  BlockFunction=simmechanics.library.frames_transforms.rigid_transform
  Transform4 : sm_lib/Frames and Transforms/Rigid Transform  TranslationMethod=Cartesian  TranslationLengthUnit=mm  TranslationStandardAxis=+Z  TranslationStandardOffset=0  TranslationCartesianOffset=[-3 52.5 -23]  TranslationROffset=0  TranslationROffsetUnits=m  TranslationZOffset=0  TranslationZOffsetUnits=m  TranslationThetaOffset=0  TranslationThetaOffsetUnits=deg  RotationMethod=ArbitraryAxis  RotationAngleUnits=rad  RotationStandardAxis=+Z  RotationAngle=1.6378338521091518  RotationArbitraryAxis=[-0.25056285449650229 0.25056285449650229 0.9351131011236713]  FollAlignAxisA=+X  BaseAlignAxisA=+Y  FollAlignAxisB=+Y  BaseAlignAxisB=+Z  BlockFunction=simmechanics.library.frames_transforms.rigid_transform
  Transform5 : sm_lib/Frames and Transforms/Rigid Transform  TranslationMethod=Cartesian  TranslationLengthUnit=mm  TranslationStandardAxis=+Z  TranslationStandardOffset=0  TranslationCartesianOffset=[26 1 1]  TranslationROffset=0  TranslationROffsetUnits=m  TranslationZOffset=0  TranslationZOffsetUnits=m  TranslationThetaOffset=0  TranslationThetaOffsetUnits=deg  RotationMethod=ArbitraryAxis  RotationAngleUnits=rad  RotationStandardAxis=+Z  RotationAngle=1.5964112029521187  RotationArbitraryAxis=[-0.15802682740811666 0.15802682740811666 0.97470767086273136]  FollAlignAxisA=+X  BaseAlignAxisA=+Y  FollAlignAxisB=+Y  BaseAlignAxisB=+Z  BlockFunction=simmechanics.library.frames_transforms.rigid_transform
  Transform6 : sm_lib/Frames and Transforms/Rigid Transform  TranslationMethod=Cartesian  TranslationLengthUnit=mm  TranslationStandardAxis=+Z  TranslationStandardOffset=0  TranslationCartesianOffset=[74 1 1]  TranslationROffset=0  TranslationROffsetUnits=m  TranslationZOffset=0  TranslationZOffsetUnits=m  TranslationThetaOffset=0  TranslationThetaOffsetUnits=deg  RotationMethod=ArbitraryAxis  RotationAngleUnits=rad  RotationStandardAxis=+Z  RotationAngle=3.1415926535897931  RotationArbitraryAxis=[3.1925426677448238e-17 0.91204751904576642 0.41008453153278329]  FollAlignAxisA=+X  BaseAlignAxisA=+Y  FollAlignAxisB=+Y  BaseAlignAxisB=+Z  BlockFunction=simmechanics.library.frames_transforms.rigid_transform
  Transform7 : sm_lib/Frames and Transforms/Rigid Transform  TranslationMethod=Cartesian  TranslationLengthUnit=mm  TranslationStandardAxis=+Z  TranslationStandardOffset=0  TranslationCartesianOffset=[13 85 85]  TranslationROffset=0  TranslationROffsetUnits=m  TranslationZOffset=0  TranslationZOffsetUnits=m  TranslationThetaOffset=0  TranslationThetaOffsetUnits=deg  RotationMethod=ArbitraryAxis  RotationAngleUnits=rad  RotationStandardAxis=+Z  RotationAngle=1.5707963267948968  RotationArbitraryAxis=[-0 -1 -0]  FollAlignAxisA=+X  BaseAlignAxisA=+Y  FollAlignAxisB=+Y  BaseAlignAxisB=+Z  BlockFunction=simmechanics.library.frames_transforms.rigid_transform
  Transform8 : sm_lib/Frames and Transforms/Rigid Transform  TranslationMethod=Cartesian  TranslationLengthUnit=mm  TranslationStandardAxis=+Z  TranslationStandardOffset=0  TranslationCartesianOffset=[-10 1 1]  TranslationROffset=0  TranslationROffsetUnits=m  TranslationZOffset=0  TranslationZOffsetUnits=m  TranslationThetaOffset=0  TranslationThetaOffsetUnits=deg  RotationMethod=ArbitraryAxis  RotationAngleUnits=rad  RotationStandardAxis=+Z  RotationAngle=2.5503618214833885  RotationArbitraryAxis=[0.67351920895470851 -0.6735192089547084 0.30453858595923028]  FollAlignAxisA=+X  BaseAlignAxisA=+Y  FollAlignAxisB=+Y  BaseAlignAxisB=+Z  BlockFunction=simmechanics.library.frames_transforms.rigid_transform
  Transform9 : sm_lib/Frames and Transforms/Rigid Transform  TranslationMethod=Cartesian  TranslationLengthUnit=mm  TranslationStandardAxis=+Z  TranslationStandardOffset=0  TranslationCartesianOffset=[-39 52.5 19]  TranslationROffset=0  TranslationROffsetUnits=m  TranslationZOffset=0  TranslationZOffsetUnits=m  TranslationThetaOffset=0  TranslationThetaOffsetUnits=deg  RotationMethod=ArbitraryAxis  RotationAngleUnits=rad  RotationStandardAxis=+Z  RotationAngle=3.1415926535897905  RotationArbitraryAxis=[-0.57504174666649199 0.81812406735821563 2.040515663386459e-15]  FollAlignAxisA=+X  BaseAlignAxisA=+Y  FollAlignAxisB=+Y  BaseAlignAxisB=+Z  BlockFunction=simmechanics.library.frames_transforms.rigid_transform
  x15060_MEAS_Capteur_deffort_1000_N_FN_9620_AA_DEFAULT_1_RIGID : Subsystem
  x15060_M_01035_Pied_porte_capteur_AA_DEFAULT_1_RIGID : Subsystem
  x15060_M_01039_Plaque_roulette_AA_DEFAULT_1_RIGID : Subsystem
  x15060_M_01063_Rondelle_entretoise_AA_DEFAULT_1_RIGID : Subsystem
  x15060_M_01063_Rondelle_entretoise_AA_DEFAULT_2_RIGID : Subsystem
  x15060_M_01063_Rondelle_entretoise_AA_DEFAULT_3_RIGID : Subsystem
  x15060_M_01063_Rondelle_entretoise_AA_DEFAULT_4_RIGID : Subsystem
  x15060_M_01063_Rondelle_entretoise_AA_DEFAULT_5_RIGID : Subsystem
  x15060_M_01069_Bride_doigt_dindexage_AA_DEFAULT_1_RIGID : Subsystem
  x15060_M_01075_Broche_M12_Modifi_e_27810_120451_1_RIGID : Subsystem
  x15060_NLM_Doigt_dindexage_acier_6_avec_contre_ecrou_M12x1_5_03 : Subsystem
  x15060_NLM_Embase_60_27801_20601_1_RIGID : Subsystem
  x15060_NLM_Roulette_pivotante_F_200_KG_95034_07532_1_RIGID : Subsystem
  x15060_NLM_Verin_a_levier_Rot_a_droite_traction_04410_35_1_RIGI : Subsystem
  x15060_Rondelle_Rondelle_Large_L_6_1_RIGID : Subsystem
  x15060_Vis_CHc_vis_CHc_M_5_X_20_1_RIGID : Subsystem
  x15060_Vis_CHc_vis_CHc_M_6_X_16_1_RIGID : Subsystem
  x15060_Vis_CHc_vis_CHc_M_8_X_12_1_RIGID : Subsystem
  x15060_Vis_CHc_vis_CHc_M_8_X_25_1_RIGID : Subsystem
  x15060_Vis_CHc_vis_CHc_M_8_X_25_2_RIGID : Subsystem
  F : PMIOPort  Port=1  Side=Right
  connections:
  Transform/RConn1 -- x15060_M_01069_Bride_doigt_dindexage_AA_DEFAULT_1_RIGID/LConn1
  Transform1/RConn1 -- x15060_Vis_CHc_vis_CHc_M_8_X_25_1_RIGID/LConn1
  Transform10/RConn1 -- x15060_M_01063_Rondelle_entretoise_AA_DEFAULT_2_RIGID/LConn1
  Transform11/RConn1 -- x15060_NLM_Verin_a_levier_Rot_a_droite_traction_04410_35_1_RIGI/LConn1
  Transform12/RConn1 -- x15060_Rondelle_Rondelle_Large_L_6_1_RIGID/LConn1
  Transform13/RConn1 -- x15060_Vis_CHc_vis_CHc_M_8_X_12_1_RIGID/LConn1
  Transform14/RConn1 -- x15060_Vis_CHc_vis_CHc_M_8_X_25_2_RIGID/LConn1
  Transform15/RConn1 -- x15060_M_01063_Rondelle_entretoise_AA_DEFAULT_5_RIGID/LConn1
  Transform16/RConn1 -- x15060_NLM_Roulette_pivotante_F_200_KG_95034_07532_1_RIGID/LConn1
  Transform17/RConn1 -- x15060_M_01063_Rondelle_entretoise_AA_DEFAULT_4_RIGID/LConn1
  Transform18/RConn1 -- x15060_MEAS_Capteur_deffort_1000_N_FN_9620_AA_DEFAULT_1_RIGID/LConn1
  Transform19/RConn1 -- x15060_M_01063_Rondelle_entretoise_AA_DEFAULT_3_RIGID/LConn1
  Transform2/RConn1 -- x15060_Vis_CHc_vis_CHc_M_6_X_16_1_RIGID/LConn1
  Transform/LConn1 -- ReferenceFrame/RConn1 -- Transform1/LConn1 -- Transform10/LConn1 -- Transform11/LConn1 -- Transform12/LConn1 -- Transform13/LConn1 -- Transform14/LConn1 -- Transform15/LConn1 -- Transform16/LConn1 -- Transform17/LConn1 -- Transform18/LConn1 -- Transform19/LConn1 -- Transform2/LConn1 -- Transform20/RConn1 -- Transform3/LConn1 -- Transform4/LConn1 -- Transform5/LConn1 -- Transform6/LConn1 -- Transform7/LConn1 -- Transform8/LConn1 -- Transform9/LConn1
  Transform20/LConn1 -- F/RConn1
  Transform3/RConn1 -- x15060_NLM_Embase_60_27801_20601_1_RIGID/LConn1
  Transform4/RConn1 -- x15060_NLM_Doigt_dindexage_acier_6_avec_contre_ecrou_M12x1_5_03/LConn1
  Transform5/RConn1 -- x15060_M_01035_Pied_porte_capteur_AA_DEFAULT_1_RIGID/LConn1
  Transform6/RConn1 -- x15060_M_01075_Broche_M12_Modifi_e_27810_120451_1_RIGID/LConn1
  Transform7/RConn1 -- x15060_M_01039_Plaque_roulette_AA_DEFAULT_1_RIGID/LConn1
  Transform8/RConn1 -- x15060_M_01063_Rondelle_entretoise_AA_DEFAULT_1_RIGID/LConn1
  Transform9/RConn1 -- x15060_Vis_CHc_vis_CHc_M_5_X_20_1_RIGID/LConn1

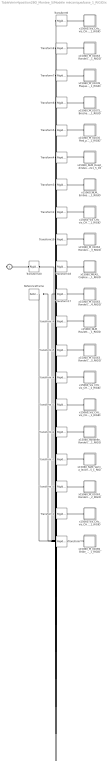
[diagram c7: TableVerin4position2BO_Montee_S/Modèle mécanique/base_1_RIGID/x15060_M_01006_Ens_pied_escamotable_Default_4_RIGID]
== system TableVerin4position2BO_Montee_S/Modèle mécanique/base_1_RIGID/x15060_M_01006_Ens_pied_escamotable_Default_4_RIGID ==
  ReferenceFrame : sm_lib/Frames and Transforms/Reference Frame  BlockFunction=simmechanics.library.frames_transforms.reference_frame
  Transform : sm_lib/Frames and Transforms/Rigid Transform  TranslationMethod=Cartesian  TranslationLengthUnit=mm  TranslationStandardAxis=+Z  TranslationStandardOffset=0  TranslationCartesianOffset=[-28 52.5 1]  TranslationROffset=0  TranslationROffsetUnits=m  TranslationZOffset=0  TranslationZOffsetUnits=m  TranslationThetaOffset=0  TranslationThetaOffsetUnits=deg  RotationMethod=ArbitraryAxis  RotationAngleUnits=rad  RotationStandardAxis=+Z  RotationAngle=2.0943951023931926  RotationArbitraryAxis=[-0.57735026918962484 0.57735026918962484 0.57735026918962762]  FollAlignAxisA=+X  BaseAlignAxisA=+Y  FollAlignAxisB=+Y  BaseAlignAxisB=+Z  BlockFunction=simmechanics.library.frames_transforms.rigid_transform
  Transform1 : sm_lib/Frames and Transforms/Rigid Transform  TranslationMethod=Cartesian  TranslationLengthUnit=mm  TranslationStandardAxis=+Z  TranslationStandardOffset=0  TranslationCartesianOffset=[-2 130 -15]  TranslationROffset=0  TranslationROffsetUnits=m  TranslationZOffset=0  TranslationZOffsetUnits=m  TranslationThetaOffset=0  TranslationThetaOffsetUnits=deg  RotationMethod=ArbitraryAxis  RotationAngleUnits=rad  RotationStandardAxis=+Z  RotationAngle=1.8468790707046723  RotationArbitraryAxis=[-0.46281772058563114 0.7560420061238935 -0.46281772058563114]  FollAlignAxisA=+X  BaseAlignAxisA=+Y  FollAlignAxisB=+Y  BaseAlignAxisB=+Z  BlockFunction=simmechanics.library.frames_transforms.rigid_transform
  Transform10 : sm_lib/Frames and Transforms/Rigid Transform  TranslationMethod=Cartesian  TranslationLengthUnit=mm  TranslationStandardAxis=+Z  TranslationStandardOffset=0  TranslationCartesianOffset=[-8 1 1]  TranslationROffset=0  TranslationROffsetUnits=m  TranslationZOffset=0  TranslationZOffsetUnits=m  TranslationThetaOffset=0  TranslationThetaOffsetUnits=deg  RotationMethod=ArbitraryAxis  RotationAngleUnits=rad  RotationStandardAxis=+Z  RotationAngle=2.5503618214833885  RotationArbitraryAxis=[0.67351920895470851 -0.6735192089547084 0.30453858595923028]  FollAlignAxisA=+X  BaseAlignAxisA=+Y  FollAlignAxisB=+Y  BaseAlignAxisB=+Z  BlockFunction=simmechanics.library.frames_transforms.rigid_transform
  Transform11 : sm_lib/Frames and Transforms/Rigid Transform  TranslationMethod=Cartesian  TranslationLengthUnit=mm  TranslationStandardAxis=+Z  TranslationStandardOffset=0  TranslationCartesianOffset=[-2 1 1]  TranslationROffset=0  TranslationROffsetUnits=m  TranslationZOffset=0  TranslationZOffsetUnits=m  TranslationThetaOffset=0  TranslationThetaOffsetUnits=deg  RotationMethod=ArbitraryAxis  RotationAngleUnits=rad  RotationStandardAxis=+Z  RotationAngle=0.78539829157538132  RotationArbitraryAxis=[-1 0 0]  FollAlignAxisA=+X  BaseAlignAxisA=+Y  FollAlignAxisB=+Y  BaseAlignAxisB=+Z  BlockFunction=simmechanics.library.frames_transforms.rigid_transform
  Transform12 : sm_lib/Frames and Transforms/Rigid Transform  TranslationMethod=Cartesian  TranslationLengthUnit=mm  TranslationStandardAxis=+Z  TranslationStandardOffset=0  TranslationCartesianOffset=[-69.299999999999997 1 1]  TranslationROffset=0  TranslationROffsetUnits=m  TranslationZOffset=0  TranslationZOffsetUnits=m  TranslationThetaOffset=0  TranslationThetaOffsetUnits=deg  RotationMethod=ArbitraryAxis  RotationAngleUnits=rad  RotationStandardAxis=+Z  RotationAngle=1.779666102874204  RotationArbitraryAxis=[-0.41441858134901061 -0.41441858134901077 -0.81025581075691555]  FollAlignAxisA=+X  BaseAlignAxisA=+Y  FollAlignAxisB=+Y  BaseAlignAxisB=+Z  BlockFunction=simmechanics.library.frames_transforms.rigid_transform
  Transform13 : sm_lib/Frames and Transforms/Rigid Transform  TranslationMethod=Cartesian  TranslationLengthUnit=mm  TranslationStandardAxis=+Z  TranslationStandardOffset=0  TranslationCartesianOffset=[23.5107 45 115]  TranslationROffset=0  TranslationROffsetUnits=m  TranslationZOffset=0  TranslationZOffsetUnits=m  TranslationThetaOffset=0  TranslationThetaOffsetUnits=deg  RotationMethod=ArbitraryAxis  RotationAngleUnits=rad  RotationStandardAxis=+Z  RotationAngle=1.7576864373908556  RotationArbitraryAxis=[0.39584132832668711 -0.82862493661313852 -0.39584132832668711]  FollAlignAxisA=+X  BaseAlignAxisA=+Y  FollAlignAxisB=+Y  BaseAlignAxisB=+Z  BlockFunction=simmechanics.library.frames_transforms.rigid_transform
  Transform14 : sm_lib/Frames and Transforms/Rigid Transform  TranslationMethod=Cartesian  TranslationLengthUnit=mm  TranslationStandardAxis=+Z  TranslationStandardOffset=0  TranslationCartesianOffset=[-2 -15 130]  TranslationROffset=0  TranslationROffsetUnits=m  TranslationZOffset=0  TranslationZOffsetUnits=m  TranslationThetaOffset=0  TranslationThetaOffsetUnits=deg  RotationMethod=ArbitraryAxis  RotationAngleUnits=rad  RotationStandardAxis=+Z  RotationAngle=1.8958525166545865  RotationArbitraryAxis=[-0.49199382426247901 0.7182507596760076 -0.49199382426247901]  FollAlignAxisA=+X  BaseAlignAxisA=+Y  FollAlignAxisB=+Y  BaseAlignAxisB=+Z  BlockFunction=simmechanics.library.frames_transforms.rigid_transform
  Transform15 : sm_lib/Frames and Transforms/Rigid Transform  TranslationMethod=Cartesian  TranslationLengthUnit=mm  TranslationStandardAxis=+Z  TranslationStandardOffset=0  TranslationCartesianOffset=[-7.0000000000000009 1 1]  TranslationROffset=0  TranslationROffsetUnits=m  TranslationZOffset=0  TranslationZOffsetUnits=m  TranslationThetaOffset=0  TranslationThetaOffsetUnits=deg  RotationMethod=ArbitraryAxis  RotationAngleUnits=rad  RotationStandardAxis=+Z  RotationAngle=2.5773215317098641  RotationArbitraryAxis=[0.6767483296554524 -0.67674832965545229 0.28986789511277461]  FollAlignAxisA=+X  BaseAlignAxisA=+Y  FollAlignAxisB=+Y  BaseAlignAxisB=+Z  BlockFunction=simmechanics.library.frames_transforms.rigid_transform
  Transform16 : sm_lib/Frames and Transforms/Rigid Transform  TranslationMethod=Cartesian  TranslationLengthUnit=mm  TranslationStandardAxis=+Z  TranslationStandardOffset=0  TranslationCartesianOffset=[73.5 50 85]  TranslationROffset=0  TranslationROffsetUnits=m  TranslationZOffset=0  TranslationZOffsetUnits=m  TranslationThetaOffset=0  TranslationThetaOffsetUnits=deg  RotationMethod=ArbitraryAxis  RotationAngleUnits=rad  RotationStandardAxis=+Z  RotationAngle=1.5707963267948968  RotationArbitraryAxis=[0 0 1]  FollAlignAxisA=+X  BaseAlignAxisA=+Y  FollAlignAxisB=+Y  BaseAlignAxisB=+Z  BlockFunction=simmechanics.library.frames_transforms.rigid_transform
  Transform17 : sm_lib/Frames and Transforms/Rigid Transform  TranslationMethod=Cartesian  TranslationLengthUnit=mm  TranslationStandardAxis=+Z  TranslationStandardOffset=0  TranslationCartesianOffset=[-9 1 1]  TranslationROffset=0  TranslationROffsetUnits=m  TranslationZOffset=0  TranslationZOffsetUnits=m  TranslationThetaOffset=0  TranslationThetaOffsetUnits=deg  RotationMethod=ArbitraryAxis  RotationAngleUnits=rad  RotationStandardAxis=+Z  RotationAngle=2.5503618214833885  RotationArbitraryAxis=[0.67351920895470851 -0.6735192089547084 0.30453858595923028]  FollAlignAxisA=+X  BaseAlignAxisA=+Y  FollAlignAxisB=+Y  BaseAlignAxisB=+Z  BlockFunction=simmechanics.library.frames_transforms.rigid_transform
  Transform18 : sm_lib/Frames and Transforms/Rigid Transform  TranslationMethod=Cartesian  TranslationLengthUnit=mm  TranslationStandardAxis=+Z  TranslationStandardOffset=0  TranslationCartesianOffset=[14 1 1]  TranslationROffset=0  TranslationROffsetUnits=m  TranslationZOffset=0  TranslationZOffsetUnits=m  TranslationThetaOffset=0  TranslationThetaOffsetUnits=deg  RotationMethod=ArbitraryAxis  RotationAngleUnits=rad  RotationStandardAxis=+Z  RotationAngle=2.0943951023931953  RotationArbitraryAxis=[-0.57735026918962584 0.57735026918962584 0.57735026918962584]  FollAlignAxisA=+X  BaseAlignAxisA=+Y  FollAlignAxisB=+Y  BaseAlignAxisB=+Z  BlockFunction=simmechanics.library.frames_transforms.rigid_transform
  Transform19 : sm_lib/Frames and Transforms/Rigid Transform  TranslationMethod=Cartesian  TranslationLengthUnit=mm  TranslationStandardAxis=+Z  TranslationStandardOffset=0  TranslationCartesianOffset=[-6 1 1]  TranslationROffset=0  TranslationROffsetUnits=m  TranslationZOffset=0  TranslationZOffsetUnits=m  TranslationThetaOffset=0  TranslationThetaOffsetUnits=deg  RotationMethod=ArbitraryAxis  RotationAngleUnits=rad  RotationStandardAxis=+Z  RotationAngle=2.5773215317098641  RotationArbitraryAxis=[0.6767483296554524 -0.6767483296554524 0.28986789511277455]  FollAlignAxisA=+X  BaseAlignAxisA=+Y  FollAlignAxisB=+Y  BaseAlignAxisB=+Z  BlockFunction=simmechanics.library.frames_transforms.rigid_transform
  Transform2 : sm_lib/Frames and Transforms/Rigid Transform  TranslationMethod=Cartesian  TranslationLengthUnit=mm  TranslationStandardAxis=+Z  TranslationStandardOffset=0  TranslationCartesianOffset=[-75.300000000000011 1 1]  TranslationROffset=0  TranslationROffsetUnits=m  TranslationZOffset=0  TranslationZOffsetUnits=m  TranslationThetaOffset=0  TranslationThetaOffsetUnits=deg  RotationMethod=ArbitraryAxis  RotationAngleUnits=rad  RotationStandardAxis=+Z  RotationAngle=2.533359793208557  RotationArbitraryAxis=[-0.67137794896695524 0.31385235267853073 -0.67137794896695535]  FollAlignAxisA=+X  BaseAlignAxisA=+Y  FollAlignAxisB=+Y  BaseAlignAxisB=+Z  BlockFunction=simmechanics.library.frames_transforms.rigid_transform
  Transform20 : sm_lib/Frames and Transforms/Rigid Transform  TranslationMethod=Cartesian  TranslationLengthUnit=mm  TranslationStandardAxis=+Z  TranslationStandardOffset=0  TranslationCartesianOffset=[-15 380 33]  TranslationROffset=0  TranslationROffsetUnits=m  TranslationZOffset=0  TranslationZOffsetUnits=m  TranslationThetaOffset=0  TranslationThetaOffsetUnits=deg  RotationMethod=ArbitraryAxis  RotationAngleUnits=rad  RotationStandardAxis=+Z  RotationAngle=3.1415926535897913  RotationArbitraryAxis=[-0.70710678118654846 -8.5078875780330932e-16 0.70710678118654657]  FollAlignAxisA=+X  BaseAlignAxisA=+Y  FollAlignAxisB=+Y  BaseAlignAxisB=+Z  BlockFunction=simmechanics.library.frames_transforms.rigid_transform
  Transform3 : sm_lib/Frames and Transforms/Rigid Transform  TranslationMethod=Cartesian  TranslationLengthUnit=mm  TranslationStandardAxis=+Z  TranslationStandardOffset=0  TranslationCartesianOffset=[104 1 1]  TranslationROffset=0  TranslationROffsetUnits=m  TranslationZOffset=0  TranslationZOffsetUnits=m  TranslationThetaOffset=0  TranslationThetaOffsetUnits=deg  RotationMethod=ArbitraryAxis  RotationAngleUnits=rad  RotationStandardAxis=+Z  RotationAngle=2.8467308529659632  RotationArbitraryAxis=[-0.6992657722290897 0.6992657722290897 0.14850844951621375]  FollAlignAxisA=+X  BaseAlignAxisA=+Y  FollAlignAxisB=+Y  BaseAlignAxisB=+Z  BlockFunction=simmechanics.library.frames_transforms.rigid_transform
  Transform4 : sm_lib/Frames and Transforms/Rigid Transform  TranslationMethod=Cartesian  TranslationLengthUnit=mm  TranslationStandardAxis=+Z  TranslationStandardOffset=0  TranslationCartesianOffset=[-3 52.5 -23]  TranslationROffset=0  TranslationROffsetUnits=m  TranslationZOffset=0  TranslationZOffsetUnits=m  TranslationThetaOffset=0  TranslationThetaOffsetUnits=deg  RotationMethod=ArbitraryAxis  RotationAngleUnits=rad  RotationStandardAxis=+Z  RotationAngle=1.6378338521091518  RotationArbitraryAxis=[-0.25056285449650229 0.25056285449650229 0.9351131011236713]  FollAlignAxisA=+X  BaseAlignAxisA=+Y  FollAlignAxisB=+Y  BaseAlignAxisB=+Z  BlockFunction=simmechanics.library.frames_transforms.rigid_transform
  Transform5 : sm_lib/Frames and Transforms/Rigid Transform  TranslationMethod=Cartesian  TranslationLengthUnit=mm  TranslationStandardAxis=+Z  TranslationStandardOffset=0  TranslationCartesianOffset=[26 1 1]  TranslationROffset=0  TranslationROffsetUnits=m  TranslationZOffset=0  TranslationZOffsetUnits=m  TranslationThetaOffset=0  TranslationThetaOffsetUnits=deg  RotationMethod=ArbitraryAxis  RotationAngleUnits=rad  RotationStandardAxis=+Z  RotationAngle=1.5964112029521187  RotationArbitraryAxis=[-0.15802682740811666 0.15802682740811666 0.97470767086273136]  FollAlignAxisA=+X  BaseAlignAxisA=+Y  FollAlignAxisB=+Y  BaseAlignAxisB=+Z  BlockFunction=simmechanics.library.frames_transforms.rigid_transform
  Transform6 : sm_lib/Frames and Transforms/Rigid Transform  TranslationMethod=Cartesian  TranslationLengthUnit=mm  TranslationStandardAxis=+Z  TranslationStandardOffset=0  TranslationCartesianOffset=[74 1 1]  TranslationROffset=0  TranslationROffsetUnits=m  TranslationZOffset=0  TranslationZOffsetUnits=m  TranslationThetaOffset=0  TranslationThetaOffsetUnits=deg  RotationMethod=ArbitraryAxis  RotationAngleUnits=rad  RotationStandardAxis=+Z  RotationAngle=3.1415926535897931  RotationArbitraryAxis=[3.1925426677448238e-17 0.91204751904576642 0.41008453153278329]  FollAlignAxisA=+X  BaseAlignAxisA=+Y  FollAlignAxisB=+Y  BaseAlignAxisB=+Z  BlockFunction=simmechanics.library.frames_transforms.rigid_transform
  Transform7 : sm_lib/Frames and Transforms/Rigid Transform  TranslationMethod=Cartesian  TranslationLengthUnit=mm  TranslationStandardAxis=+Z  TranslationStandardOffset=0  TranslationCartesianOffset=[13 85 85]  TranslationROffset=0  TranslationROffsetUnits=m  TranslationZOffset=0  TranslationZOffsetUnits=m  TranslationThetaOffset=0  TranslationThetaOffsetUnits=deg  RotationMethod=ArbitraryAxis  RotationAngleUnits=rad  RotationStandardAxis=+Z  RotationAngle=1.5707963267948968  RotationArbitraryAxis=[-0 -1 -0]  FollAlignAxisA=+X  BaseAlignAxisA=+Y  FollAlignAxisB=+Y  BaseAlignAxisB=+Z  BlockFunction=simmechanics.library.frames_transforms.rigid_transform
  Transform8 : sm_lib/Frames and Transforms/Rigid Transform  TranslationMethod=Cartesian  TranslationLengthUnit=mm  TranslationStandardAxis=+Z  TranslationStandardOffset=0  TranslationCartesianOffset=[-10 1 1]  TranslationROffset=0  TranslationROffsetUnits=m  TranslationZOffset=0  TranslationZOffsetUnits=m  TranslationThetaOffset=0  TranslationThetaOffsetUnits=deg  RotationMethod=ArbitraryAxis  RotationAngleUnits=rad  RotationStandardAxis=+Z  RotationAngle=2.5503618214833885  RotationArbitraryAxis=[0.67351920895470851 -0.6735192089547084 0.30453858595923028]  FollAlignAxisA=+X  BaseAlignAxisA=+Y  FollAlignAxisB=+Y  BaseAlignAxisB=+Z  BlockFunction=simmechanics.library.frames_transforms.rigid_transform
  Transform9 : sm_lib/Frames and Transforms/Rigid Transform  TranslationMethod=Cartesian  TranslationLengthUnit=mm  TranslationStandardAxis=+Z  TranslationStandardOffset=0  TranslationCartesianOffset=[-39 52.5 19]  TranslationROffset=0  TranslationROffsetUnits=m  TranslationZOffset=0  TranslationZOffsetUnits=m  TranslationThetaOffset=0  TranslationThetaOffsetUnits=deg  RotationMethod=ArbitraryAxis  RotationAngleUnits=rad  RotationStandardAxis=+Z  RotationAngle=3.1415926535897905  RotationArbitraryAxis=[-0.57504174666649199 0.81812406735821563 2.040515663386459e-15]  FollAlignAxisA=+X  BaseAlignAxisA=+Y  FollAlignAxisB=+Y  BaseAlignAxisB=+Z  BlockFunction=simmechanics.library.frames_transforms.rigid_transform
  x15060_MEAS_Capteur_deffort_1000_N_FN_9620_AA_DEFAULT_1_RIGID : Subsystem
  x15060_M_01035_Pied_porte_capteur_AA_DEFAULT_1_RIGID : Subsystem
  x15060_M_01039_Plaque_roulette_AA_DEFAULT_1_RIGID : Subsystem
  x15060_M_01063_Rondelle_entretoise_AA_DEFAULT_1_RIGID : Subsystem
  x15060_M_01063_Rondelle_entretoise_AA_DEFAULT_2_RIGID : Subsystem
  x15060_M_01063_Rondelle_entretoise_AA_DEFAULT_3_RIGID : Subsystem
  x15060_M_01063_Rondelle_entretoise_AA_DEFAULT_4_RIGID : Subsystem
  x15060_M_01063_Rondelle_entretoise_AA_DEFAULT_5_RIGID : Subsystem
  x15060_M_01069_Bride_doigt_dindexage_AA_DEFAULT_1_RIGID : Subsystem
  x15060_M_01075_Broche_M12_Modifi_e_27810_120451_1_RIGID : Subsystem
  x15060_NLM_Doigt_dindexage_acier_6_avec_contre_ecrou_M12x1_5_03 : Subsystem
  x15060_NLM_Embase_60_27801_20601_1_RIGID : Subsystem
  x15060_NLM_Roulette_pivotante_F_200_KG_95034_07532_1_RIGID : Subsystem
  x15060_NLM_Verin_a_levier_Rot_a_droite_traction_04410_35_1_RIGI : Subsystem
  x15060_Rondelle_Rondelle_Large_L_6_1_RIGID : Subsystem
  x15060_Vis_CHc_vis_CHc_M_5_X_20_1_RIGID : Subsystem
  x15060_Vis_CHc_vis_CHc_M_6_X_16_1_RIGID : Subsystem
  x15060_Vis_CHc_vis_CHc_M_8_X_12_1_RIGID : Subsystem
  x15060_Vis_CHc_vis_CHc_M_8_X_25_1_RIGID : Subsystem
  x15060_Vis_CHc_vis_CHc_M_8_X_25_2_RIGID : Subsystem
  F : PMIOPort  Port=1  Side=Right
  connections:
  Transform/RConn1 -- x15060_M_01069_Bride_doigt_dindexage_AA_DEFAULT_1_RIGID/LConn1
  Transform1/RConn1 -- x15060_Vis_CHc_vis_CHc_M_8_X_25_1_RIGID/LConn1
  Transform10/RConn1 -- x15060_M_01063_Rondelle_entretoise_AA_DEFAULT_2_RIGID/LConn1
  Transform11/RConn1 -- x15060_NLM_Verin_a_levier_Rot_a_droite_traction_04410_35_1_RIGI/LConn1
  Transform12/RConn1 -- x15060_Rondelle_Rondelle_Large_L_6_1_RIGID/LConn1
  Transform13/RConn1 -- x15060_Vis_CHc_vis_CHc_M_8_X_12_1_RIGID/LConn1
  Transform14/RConn1 -- x15060_Vis_CHc_vis_CHc_M_8_X_25_2_RIGID/LConn1
  Transform15/RConn1 -- x15060_M_01063_Rondelle_entretoise_AA_DEFAULT_5_RIGID/LConn1
  Transform16/RConn1 -- x15060_NLM_Roulette_pivotante_F_200_KG_95034_07532_1_RIGID/LConn1
  Transform17/RConn1 -- x15060_M_01063_Rondelle_entretoise_AA_DEFAULT_4_RIGID/LConn1
  Transform18/RConn1 -- x15060_MEAS_Capteur_deffort_1000_N_FN_9620_AA_DEFAULT_1_RIGID/LConn1
  Transform19/RConn1 -- x15060_M_01063_Rondelle_entretoise_AA_DEFAULT_3_RIGID/LConn1
  Transform2/RConn1 -- x15060_Vis_CHc_vis_CHc_M_6_X_16_1_RIGID/LConn1
  Transform/LConn1 -- ReferenceFrame/RConn1 -- Transform1/LConn1 -- Transform10/LConn1 -- Transform11/LConn1 -- Transform12/LConn1 -- Transform13/LConn1 -- Transform14/LConn1 -- Transform15/LConn1 -- Transform16/LConn1 -- Transform17/LConn1 -- Transform18/LConn1 -- Transform19/LConn1 -- Transform2/LConn1 -- Transform20/RConn1 -- Transform3/LConn1 -- Transform4/LConn1 -- Transform5/LConn1 -- Transform6/LConn1 -- Transform7/LConn1 -- Transform8/LConn1 -- Transform9/LConn1
  Transform20/LConn1 -- F/RConn1
  Transform3/RConn1 -- x15060_NLM_Embase_60_27801_20601_1_RIGID/LConn1
  Transform4/RConn1 -- x15060_NLM_Doigt_dindexage_acier_6_avec_contre_ecrou_M12x1_5_03/LConn1
  Transform5/RConn1 -- x15060_M_01035_Pied_porte_capteur_AA_DEFAULT_1_RIGID/LConn1
  Transform6/RConn1 -- x15060_M_01075_Broche_M12_Modifi_e_27810_120451_1_RIGID/LConn1
  Transform7/RConn1 -- x15060_M_01039_Plaque_roulette_AA_DEFAULT_1_RIGID/LConn1
  Transform8/RConn1 -- x15060_M_01063_Rondelle_entretoise_AA_DEFAULT_1_RIGID/LConn1
  Transform9/RConn1 -- x15060_Vis_CHc_vis_CHc_M_5_X_20_1_RIGID/LConn1

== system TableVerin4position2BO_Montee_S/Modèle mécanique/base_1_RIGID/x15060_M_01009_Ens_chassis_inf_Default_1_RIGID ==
  ReferenceFrame : sm_lib/Frames and Transforms/Reference Frame  BlockFunction=simmechanics.library.frames_transforms.reference_frame
  Transform : sm_lib/Frames and Transforms/Rigid Transform  TranslationMethod=Cartesian  TranslationLengthUnit=mm  TranslationStandardAxis=+Z  TranslationStandardOffset=0  TranslationCartesianOffset=[-1540 155 -20]  TranslationROffset=0  TranslationROffsetUnits=m  TranslationZOffset=0  TranslationZOffsetUnits=m  TranslationThetaOffset=0  TranslationThetaOffsetUnits=deg  RotationMethod=ArbitraryAxis  RotationAngleUnits=rad  RotationStandardAxis=+Z  RotationAngle=3.1415926535897931  RotationArbitraryAxis=[0 -0.70710678118654746 0.70710678118654757]  FollAlignAxisA=+X  BaseAlignAxisA=+Y  FollAlignAxisB=+Y  BaseAlignAxisB=+Z  BlockFunction=simmechanics.library.frames_transforms.rigid_transform
  Transform1 : sm_lib/Frames and Transforms/Rigid Transform  TranslationMethod=Cartesian  TranslationLengthUnit=mm  TranslationStandardAxis=+Z  TranslationStandardOffset=0  TranslationCartesianOffset=[-180 -155 -20]  TranslationROffset=0  TranslationROffsetUnits=m  TranslationZOffset=0  TranslationZOffsetUnits=m  TranslationThetaOffset=0  TranslationThetaOffsetUnits=deg  RotationMethod=ArbitraryAxis  RotationAngleUnits=rad  RotationStandardAxis=+Z  RotationAngle=1.5707963267950076  RotationArbitraryAxis=[-1 -1.8734999999997923e-15 -1.8734999999997923e-15]  FollAlignAxisA=+X  BaseAlignAxisA=+Y  FollAlignAxisB=+Y  BaseAlignAxisB=+Z  BlockFunction=simmechanics.library.frames_transforms.rigid_transform
  Transform2 : sm_lib/Frames and Transforms/Rigid Transform  TranslationMethod=Cartesian  TranslationLengthUnit=mm  TranslationStandardAxis=+Z  TranslationStandardOffset=0  TranslationCartesianOffset=[-180 155 -20]  TranslationROffset=0  TranslationROffsetUnits=m  TranslationZOffset=0  TranslationZOffsetUnits=m  TranslationThetaOffset=0  TranslationThetaOffsetUnits=deg  RotationMethod=ArbitraryAxis  RotationAngleUnits=rad  RotationStandardAxis=+Z  RotationAngle=1.5707963267950076  RotationArbitraryAxis=[-1 -1.8734999999997923e-15 -1.8734999999997923e-15]  FollAlignAxisA=+X  BaseAlignAxisA=+Y  FollAlignAxisB=+Y  BaseAlignAxisB=+Z  BlockFunction=simmechanics.library.frames_transforms.rigid_transform
  Transform3 : sm_lib/Frames and Transforms/Rigid Transform  TranslationMethod=None  TranslationLengthUnit=m  TranslationStandardAxis=+Z  TranslationStandardOffset=0  TranslationCartesianOffset=[0 0 0]  TranslationROffset=0  TranslationROffsetUnits=m  TranslationZOffset=0  TranslationZOffsetUnits=m  TranslationThetaOffset=0  TranslationThetaOffsetUnits=deg  RotationMethod=None  RotationAngleUnits=deg  RotationStandardAxis=+Z  RotationAngle=0  RotationArbitraryAxis=[0 0 1]  FollAlignAxisA=+X  BaseAlignAxisA=+Y  FollAlignAxisB=+Y  BaseAlignAxisB=+Z  BlockFunction=simmechanics.library.frames_transforms.rigid_transform
  Transform4 : sm_lib/Frames and Transforms/Rigid Transform  TranslationMethod=Cartesian  TranslationLengthUnit=mm  TranslationStandardAxis=+Z  TranslationStandardOffset=0  TranslationCartesianOffset=[-1540 -155 -20]  TranslationROffset=0  TranslationROffsetUnits=m  TranslationZOffset=0  TranslationZOffsetUnits=m  TranslationThetaOffset=0  TranslationThetaOffsetUnits=deg  RotationMethod=ArbitraryAxis  RotationAngleUnits=rad  RotationStandardAxis=+Z  RotationAngle=3.1415926535897931  RotationArbitraryAxis=[0 -0.70710678118654746 0.70710678118654757]  FollAlignAxisA=+X  BaseAlignAxisA=+Y  FollAlignAxisB=+Y  BaseAlignAxisB=+Z  BlockFunction=simmechanics.library.frames_transforms.rigid_transform
  Transform5 : sm_lib/Frames and Transforms/Rigid Transform  TranslationMethod=None  TranslationLengthUnit=m  TranslationStandardAxis=+Z  TranslationStandardOffset=0  TranslationCartesianOffset=[0 0 0]  TranslationROffset=0  TranslationROffsetUnits=m  TranslationZOffset=0  TranslationZOffsetUnits=m  TranslationThetaOffset=0  TranslationThetaOffsetUnits=deg  RotationMethod=None  RotationAngleUnits=deg  RotationStandardAxis=+Z  RotationAngle=0  RotationArbitraryAxis=[0 0 1]  FollAlignAxisA=+X  BaseAlignAxisA=+Y  FollAlignAxisB=+Y  BaseAlignAxisB=+Z  BlockFunction=simmechanics.library.frames_transforms.rigid_transform
  x15060_ITEM_Kit_Equerre_8_40x40_Zn_0_0_411_15_AA_DEFAULT_1_RIGI : Subsystem
  x15060_ITEM_Kit_Equerre_8_40x40_Zn_0_0_411_15_AA_DEFAULT_2_RIGI : Subsystem
  x15060_ITEM_Kit_Equerre_8_40x40_Zn_0_0_411_15_AA_DEFAULT_3_RIGI : Subsystem
  x15060_ITEM_Kit_Equerre_8_40x40_Zn_0_0_411_15_AA_DEFAULT_4_RIGI : Subsystem
  x15060_M_01023_Chassis_alu_partie_basse_AA_DEFAULT_Brut_dusinag : Subsystem
  F : PMIOPort  Port=1  Side=Right
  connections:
  Transform/RConn1 -- x15060_ITEM_Kit_Equerre_8_40x40_Zn_0_0_411_15_AA_DEFAULT_2_RIGI/LConn1
  Transform1/RConn1 -- x15060_ITEM_Kit_Equerre_8_40x40_Zn_0_0_411_15_AA_DEFAULT_3_RIGI/LConn1
  Transform2/RConn1 -- x15060_ITEM_Kit_Equerre_8_40x40_Zn_0_0_411_15_AA_DEFAULT_4_RIGI/LConn1
  Transform3/RConn1 -- x15060_M_01023_Chassis_alu_partie_basse_AA_DEFAULT_Brut_dusinag/LConn1
  Transform4/RConn1 -- x15060_ITEM_Kit_Equerre_8_40x40_Zn_0_0_411_15_AA_DEFAULT_1_RIGI/LConn1
  Transform/LConn1 -- ReferenceFrame/RConn1 -- Transform1/LConn1 -- Transform2/LConn1 -- Transform3/LConn1 -- Transform4/LConn1 -- Transform5/RConn1
  Transform5/LConn1 -- F/RConn1

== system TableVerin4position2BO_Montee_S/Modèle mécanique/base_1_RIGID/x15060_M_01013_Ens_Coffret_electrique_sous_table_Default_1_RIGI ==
  ReferenceFrame : sm_lib/Frames and Transforms/Reference Frame  BlockFunction=simmechanics.library.frames_transforms.reference_frame
  Transform : sm_lib/Frames and Transforms/Rigid Transform  TranslationMethod=None  TranslationLengthUnit=m  TranslationStandardAxis=+Z  TranslationStandardOffset=0  TranslationCartesianOffset=[0 0 0]  TranslationROffset=0  TranslationROffsetUnits=m  TranslationZOffset=0  TranslationZOffsetUnits=m  TranslationThetaOffset=0  TranslationThetaOffsetUnits=deg  RotationMethod=None  RotationAngleUnits=deg  RotationStandardAxis=+Z  RotationAngle=0  RotationArbitraryAxis=[0 0 1]  FollAlignAxisA=+X  BaseAlignAxisA=+Y  FollAlignAxisB=+Y  BaseAlignAxisB=+Z  BlockFunction=simmechanics.library.frames_transforms.rigid_transform
  Transform1 : sm_lib/Frames and Transforms/Rigid Transform  TranslationMethod=Cartesian  TranslationLengthUnit=mm  TranslationStandardAxis=+Z  TranslationStandardOffset=0  TranslationCartesianOffset=[85 0 123]  TranslationROffset=0  TranslationROffsetUnits=m  TranslationZOffset=0  TranslationZOffsetUnits=m  TranslationThetaOffset=0  TranslationThetaOffsetUnits=deg  RotationMethod=ArbitraryAxis  RotationAngleUnits=rad  RotationStandardAxis=+Z  RotationAngle=1.5708012083345249  RotationArbitraryAxis=[-0.0022094152617557553 -0.99999511847228639 -0.0022094152617557553]  FollAlignAxisA=+X  BaseAlignAxisA=+Y  FollAlignAxisB=+Y  BaseAlignAxisB=+Z  BlockFunction=simmechanics.library.frames_transforms.rigid_transform
  Transform2 : sm_lib/Frames and Transforms/Rigid Transform  TranslationMethod=Cartesian  TranslationLengthUnit=mm  TranslationStandardAxis=+Z  TranslationStandardOffset=0  TranslationCartesianOffset=[-85 0 123]  TranslationROffset=0  TranslationROffsetUnits=m  TranslationZOffset=0  TranslationZOffsetUnits=m  TranslationThetaOffset=0  TranslationThetaOffsetUnits=deg  RotationMethod=ArbitraryAxis  RotationAngleUnits=rad  RotationStandardAxis=+Z  RotationAngle=1.5723058157582293  RotationArbitraryAxis=[0.038822844681433127 -0.99849164916972766 0.038822844681433127]  FollAlignAxisA=+X  BaseAlignAxisA=+Y  FollAlignAxisB=+Y  BaseAlignAxisB=+Z  BlockFunction=simmechanics.library.frames_transforms.rigid_transform
  Transform3 : sm_lib/Frames and Transforms/Rigid Transform  TranslationMethod=Cartesian  TranslationLengthUnit=mm  TranslationStandardAxis=+Z  TranslationStandardOffset=0  TranslationCartesianOffset=[-375 -55 -60]  TranslationROffset=0  TranslationROffsetUnits=m  TranslationZOffset=0  TranslationZOffsetUnits=m  TranslationThetaOffset=0  TranslationThetaOffsetUnits=deg  RotationMethod=None  RotationAngleUnits=deg  RotationStandardAxis=+Z  RotationAngle=0  RotationArbitraryAxis=[0 0 1]  FollAlignAxisA=+X  BaseAlignAxisA=+Y  FollAlignAxisB=+Y  BaseAlignAxisB=+Z  BlockFunction=simmechanics.library.frames_transforms.rigid_transform
  x15060_Bouton_rouge_AA_DEFAULT_1_RIGID : Subsystem
  x15060_Bouton_vert_AA_DEFAULT_1_RIGID : Subsystem
  x15060_Coffret_elect_600_X_300_H_150_AA_DEFAULT_1_RIGID : Subsystem
  F : PMIOPort  Port=1  Side=Right
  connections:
  Transform/RConn1 -- x15060_Coffret_elect_600_X_300_H_150_AA_DEFAULT_1_RIGID/LConn1
  Transform1/RConn1 -- x15060_Bouton_rouge_AA_DEFAULT_1_RIGID/LConn1
  Transform2/RConn1 -- x15060_Bouton_vert_AA_DEFAULT_1_RIGID/LConn1
  Transform/LConn1 -- ReferenceFrame/RConn1 -- Transform1/LConn1 -- Transform2/LConn1 -- Transform3/RConn1
  Transform3/LConn1 -- F/RConn1
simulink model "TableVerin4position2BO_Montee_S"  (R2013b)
settings: Solver=ode15s  StartTime=0.0  StopTime=20  RelTol=1e-3
undefined symbols (not defined in the file): deg, kg, m, mm, N, rad, s, X, Y, Z
libraries: sm_lib x907, fl_lib x19, nesl_utility x13, elec_lib x3, sdl_lib x2
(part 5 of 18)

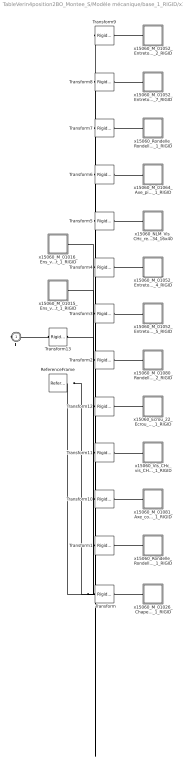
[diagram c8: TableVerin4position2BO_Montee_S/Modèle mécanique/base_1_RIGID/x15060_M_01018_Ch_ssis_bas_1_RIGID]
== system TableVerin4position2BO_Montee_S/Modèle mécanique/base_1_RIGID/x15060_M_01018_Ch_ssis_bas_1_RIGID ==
  ReferenceFrame : sm_lib/Frames and Transforms/Reference Frame  BlockFunction=simmechanics.library.frames_transforms.reference_frame
  Transform : sm_lib/Frames and Transforms/Rigid Transform  TranslationMethod=Cartesian  TranslationLengthUnit=mm  TranslationStandardAxis=+Z  TranslationStandardOffset=0  TranslationCartesianOffset=[-778.75999999999999 0 1.94289e-12]  TranslationROffset=0  TranslationROffsetUnits=m  TranslationZOffset=0  TranslationZOffsetUnits=m  TranslationThetaOffset=0  TranslationThetaOffsetUnits=deg  RotationMethod=ArbitraryAxis  RotationAngleUnits=rad  RotationStandardAxis=+Z  RotationAngle=1.5707963267948968  RotationArbitraryAxis=[-0 -0 -1]  FollAlignAxisA=+X  BaseAlignAxisA=+Y  FollAlignAxisB=+Y  BaseAlignAxisB=+Z  BlockFunction=simmechanics.library.frames_transforms.rigid_transform
  Transform1 : sm_lib/Frames and Transforms/Rigid Transform  TranslationMethod=Cartesian  TranslationLengthUnit=mm  TranslationStandardAxis=+Z  TranslationStandardOffset=0  TranslationCartesianOffset=[-698.75999999999999 -112 -135]  TranslationROffset=0  TranslationROffsetUnits=m  TranslationZOffset=0  TranslationZOffsetUnits=m  TranslationThetaOffset=0  TranslationThetaOffsetUnits=deg  RotationMethod=None  RotationAngleUnits=deg  RotationStandardAxis=+Z  RotationAngle=0  RotationArbitraryAxis=[0 0 1]  FollAlignAxisA=+X  BaseAlignAxisA=+Y  FollAlignAxisB=+Y  BaseAlignAxisB=+Z  BlockFunction=simmechanics.library.frames_transforms.rigid_transform
  Transform10 : sm_lib/Frames and Transforms/Rigid Transform  TranslationMethod=Cartesian  TranslationLengthUnit=mm  TranslationStandardAxis=+Z  TranslationStandardOffset=0  TranslationCartesianOffset=[-620.75999999999999 -66.5 -156]  TranslationROffset=0  TranslationROffsetUnits=m  TranslationZOffset=0  TranslationZOffsetUnits=m  TranslationThetaOffset=0  TranslationThetaOffsetUnits=deg  RotationMethod=ArbitraryAxis  RotationAngleUnits=rad  RotationStandardAxis=+Z  RotationAngle=1.5708766247314945  RotationArbitraryAxis=[0.0089605518396334936 -0.0089605518396334936 -0.99991970528710883]  FollAlignAxisA=+X  BaseAlignAxisA=+Y  FollAlignAxisB=+Y  BaseAlignAxisB=+Z  BlockFunction=simmechanics.library.frames_transforms.rigid_transform
  Transform11 : sm_lib/Frames and Transforms/Rigid Transform  TranslationMethod=Cartesian  TranslationLengthUnit=mm  TranslationStandardAxis=+Z  TranslationStandardOffset=0  TranslationCartesianOffset=[-778.75999999999999 133.5 -20]  TranslationROffset=0  TranslationROffsetUnits=m  TranslationZOffset=0  TranslationZOffsetUnits=m  TranslationThetaOffset=0  TranslationThetaOffsetUnits=deg  RotationMethod=ArbitraryAxis  RotationAngleUnits=rad  RotationStandardAxis=+Z  RotationAngle=1.5723576177247005  RotationArbitraryAxis=[0.99843992661750025 0.039482356414230965 -0.039482356414230965]  FollAlignAxisA=+X  BaseAlignAxisA=+Y  FollAlignAxisB=+Y  BaseAlignAxisB=+Z  BlockFunction=simmechanics.library.frames_transforms.rigid_transform
  Transform12 : sm_lib/Frames and Transforms/Rigid Transform  TranslationMethod=Cartesian  TranslationLengthUnit=mm  TranslationStandardAxis=+Z  TranslationStandardOffset=0  TranslationCartesianOffset=[-698.75999999999999 -109.5 -135]  TranslationROffset=0  TranslationROffsetUnits=m  TranslationZOffset=0  TranslationZOffsetUnits=m  TranslationThetaOffset=0  TranslationThetaOffsetUnits=deg  RotationMethod=ArbitraryAxis  RotationAngleUnits=rad  RotationStandardAxis=+Z  RotationAngle=0.0077183974585433093  RotationArbitraryAxis=[0 -1 0]  FollAlignAxisA=+X  BaseAlignAxisA=+Y  FollAlignAxisB=+Y  BaseAlignAxisB=+Z  BlockFunction=simmechanics.library.frames_transforms.rigid_transform
  Transform13 : sm_lib/Frames and Transforms/Rigid Transform  TranslationMethod=Cartesian  TranslationLengthUnit=mm  TranslationStandardAxis=+Z  TranslationStandardOffset=0  TranslationCartesianOffset=[-621.24000000000001 0 121]  TranslationROffset=0  TranslationROffsetUnits=m  TranslationZOffset=0  TranslationZOffsetUnits=m  TranslationThetaOffset=0  TranslationThetaOffsetUnits=deg  RotationMethod=None  RotationAngleUnits=deg  RotationStandardAxis=+Z  RotationAngle=0  RotationArbitraryAxis=[0 0 1]  FollAlignAxisA=+X  BaseAlignAxisA=+Y  FollAlignAxisB=+Y  BaseAlignAxisB=+Z  BlockFunction=simmechanics.library.frames_transforms.rigid_transform
  Transform2 : sm_lib/Frames and Transforms/Rigid Transform  TranslationMethod=Cartesian  TranslationLengthUnit=mm  TranslationStandardAxis=+Z  TranslationStandardOffset=0  TranslationCartesianOffset=[-620.75999999999999 -27.5 -156]  TranslationROffset=0  TranslationROffsetUnits=m  TranslationZOffset=0  TranslationZOffsetUnits=m  TranslationThetaOffset=0  TranslationThetaOffsetUnits=deg  RotationMethod=ArbitraryAxis  RotationAngleUnits=rad  RotationStandardAxis=+Z  RotationAngle=0.34613006937877605  RotationArbitraryAxis=[0 1 0]  FollAlignAxisA=+X  BaseAlignAxisA=+Y  FollAlignAxisB=+Y  BaseAlignAxisB=+Z  BlockFunction=simmechanics.library.frames_transforms.rigid_transform
  Transform3 : sm_lib/Frames and Transforms/Rigid Transform  TranslationMethod=Cartesian  TranslationLengthUnit=mm  TranslationStandardAxis=+Z  TranslationStandardOffset=0  TranslationCartesianOffset=[-620.75999999999999 -27 -156]  TranslationROffset=0  TranslationROffsetUnits=m  TranslationZOffset=0  TranslationZOffsetUnits=m  TranslationThetaOffset=0  TranslationThetaOffsetUnits=deg  RotationMethod=ArbitraryAxis  RotationAngleUnits=rad  RotationStandardAxis=+Z  RotationAngle=1.6462179399056456  RotationArbitraryAxis=[-0.26470799157737873 -0.26470799157737873 0.92728601757502027]  FollAlignAxisA=+X  BaseAlignAxisA=+Y  FollAlignAxisB=+Y  BaseAlignAxisB=+Z  BlockFunction=simmechanics.library.frames_transforms.rigid_transform
  Transform4 : sm_lib/Frames and Transforms/Rigid Transform  TranslationMethod=Cartesian  TranslationLengthUnit=mm  TranslationStandardAxis=+Z  TranslationStandardOffset=0  TranslationCartesianOffset=[-620.75999999999999 -50.5 -156]  TranslationROffset=0  TranslationROffsetUnits=m  TranslationZOffset=0  TranslationZOffsetUnits=m  TranslationThetaOffset=0  TranslationThetaOffsetUnits=deg  RotationMethod=ArbitraryAxis  RotationAngleUnits=rad  RotationStandardAxis=+Z  RotationAngle=1.6462179399056456  RotationArbitraryAxis=[-0.26470799157737873 -0.26470799157737873 0.92728601757502027]  FollAlignAxisA=+X  BaseAlignAxisA=+Y  FollAlignAxisB=+Y  BaseAlignAxisB=+Z  BlockFunction=simmechanics.library.frames_transforms.rigid_transform
  Transform5 : sm_lib/Frames and Transforms/Rigid Transform  TranslationMethod=Cartesian  TranslationLengthUnit=mm  TranslationStandardAxis=+Z  TranslationStandardOffset=0  TranslationCartesianOffset=[-698.75999999999999 -159.5 -135]  TranslationROffset=0  TranslationROffsetUnits=m  TranslationZOffset=0  TranslationZOffsetUnits=m  TranslationThetaOffset=0  TranslationThetaOffsetUnits=deg  RotationMethod=ArbitraryAxis  RotationAngleUnits=rad  RotationStandardAxis=+Z  RotationAngle=1.6989856875068772  RotationArbitraryAxis=[0.33667237369942338 0.33667237369942338 0.87937672562741365]  FollAlignAxisA=+X  BaseAlignAxisA=+Y  FollAlignAxisB=+Y  BaseAlignAxisB=+Z  BlockFunction=simmechanics.library.frames_transforms.rigid_transform
  Transform6 : sm_lib/Frames and Transforms/Rigid Transform  TranslationMethod=Cartesian  TranslationLengthUnit=mm  TranslationStandardAxis=+Z  TranslationStandardOffset=0  TranslationCartesianOffset=[-778.75999999999999 1.5 1.94289e-12]  TranslationROffset=0  TranslationROffsetUnits=m  TranslationZOffset=0  TranslationZOffsetUnits=m  TranslationThetaOffset=0  TranslationThetaOffsetUnits=deg  RotationMethod=ArbitraryAxis  RotationAngleUnits=rad  RotationStandardAxis=+Z  RotationAngle=2.0943951023931953  RotationArbitraryAxis=[0.57735026918962584 0.57735026918962584 0.57735026918962584]  FollAlignAxisA=+X  BaseAlignAxisA=+Y  FollAlignAxisB=+Y  BaseAlignAxisB=+Z  BlockFunction=simmechanics.library.frames_transforms.rigid_transform
  Transform7 : sm_lib/Frames and Transforms/Rigid Transform  TranslationMethod=Cartesian  TranslationLengthUnit=mm  TranslationStandardAxis=+Z  TranslationStandardOffset=0  TranslationCartesianOffset=[-778.75999999999999 125.5 -20]  TranslationROffset=0  TranslationROffsetUnits=m  TranslationZOffset=0  TranslationZOffsetUnits=m  TranslationThetaOffset=0  TranslationThetaOffsetUnits=deg  RotationMethod=ArbitraryAxis  RotationAngleUnits=rad  RotationStandardAxis=+Z  RotationAngle=3.1415926535897931  RotationArbitraryAxis=[-0.9966372618178484 -2.0650739541936245e-16 0.081940029022581309]  FollAlignAxisA=+X  BaseAlignAxisA=+Y  FollAlignAxisB=+Y  BaseAlignAxisB=+Z  BlockFunction=simmechanics.library.frames_transforms.rigid_transform
  Transform8 : sm_lib/Frames and Transforms/Rigid Transform  TranslationMethod=Cartesian  TranslationLengthUnit=mm  TranslationStandardAxis=+Z  TranslationStandardOffset=0  TranslationCartesianOffset=[-778.75999999999999 -106.5 -8.5609299999999991e-10]  TranslationROffset=0  TranslationROffsetUnits=m  TranslationZOffset=0  TranslationZOffsetUnits=m  TranslationThetaOffset=0  TranslationThetaOffsetUnits=deg  RotationMethod=ArbitraryAxis  RotationAngleUnits=rad  RotationStandardAxis=+Z  RotationAngle=2.793539492072322  RotationArbitraryAxis=[-0.69609360831745681 -0.6960936083174567 0.17580493997372784]  FollAlignAxisA=+X  BaseAlignAxisA=+Y  FollAlignAxisB=+Y  BaseAlignAxisB=+Z  BlockFunction=simmechanics.library.frames_transforms.rigid_transform
  Transform9 : sm_lib/Frames and Transforms/Rigid Transform  TranslationMethod=Cartesian  TranslationLengthUnit=mm  TranslationStandardAxis=+Z  TranslationStandardOffset=0  TranslationCartesianOffset=[-778.75999999999999 105.5 -8.5609299999999991e-10]  TranslationROffset=0  TranslationROffsetUnits=m  TranslationZOffset=0  TranslationZOffsetUnits=m  TranslationThetaOffset=0  TranslationThetaOffsetUnits=deg  RotationMethod=ArbitraryAxis  RotationAngleUnits=rad  RotationStandardAxis=+Z  RotationAngle=2.8057551749822172  RotationArbitraryAxis=[-0.69687325454044569 -0.69687325454044569 0.16951499701328632]  FollAlignAxisA=+X  BaseAlignAxisA=+Y  FollAlignAxisB=+Y  BaseAlignAxisB=+Z  BlockFunction=simmechanics.library.frames_transforms.rigid_transform
  x15060_Ecrou_22_Ecrou_Hm_M12_1_RIGID : Subsystem
  x15060_M_01015_Ens_verin_levage_Default_1_RIGID : Subsystem
  x15060_M_01016_Ens_verin_inclinaison_Default_1_RIGID : Subsystem
  x15060_M_01026_Chape_basse_AA_DEFAULT_Brut_dusinage_1_RIGID : Subsystem
  x15060_M_01052_Entretoise_pour_axe_AA_DEFAULT_2_RIGID : Subsystem
  x15060_M_01052_Entretoise_pour_axe_AA_DEFAULT_4_RIGID : Subsystem
  x15060_M_01052_Entretoise_pour_axe_AA_DEFAULT_5_RIGID : Subsystem
  x15060_M_01052_Entretoise_pour_axe_AA_DEFAULT_7_RIGID : Subsystem
  x15060_M_01064_Axe_pivot_AA_DEFAULT_1_RIGID : Subsystem
  x15060_M_01080_Rondelle_anti_rotation_AA_DEFAULT_2_RIGID : Subsystem
  x15060_M_01081_Axe_court_AA_DEFAULT_1_RIGID : Subsystem
  x15060_NLM_Vis_CHc_rectifi_e_a_paulement_16_L40_M12_07534_16x40 : Subsystem
  x15060_Rondelle_Rondelle_Etroite_Z_12_1_RIGID : Subsystem
  x15060_Rondelle_Rondelle_TresLarge_LL_8_1_RIGID : Subsystem
  x15060_Vis_CHc_vis_CHc_M_8_X_12_1_RIGID : Subsystem
  F : PMIOPort  Port=1  Side=Right
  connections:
  Transform/RConn1 -- x15060_M_01026_Chape_basse_AA_DEFAULT_Brut_dusinage_1_RIGID/LConn1
  Transform1/RConn1 -- x15060_Rondelle_Rondelle_Etroite_Z_12_1_RIGID/LConn1
  Transform10/RConn1 -- x15060_M_01081_Axe_court_AA_DEFAULT_1_RIGID/LConn1
  Transform11/RConn1 -- x15060_Vis_CHc_vis_CHc_M_8_X_12_1_RIGID/LConn1
  Transform12/RConn1 -- x15060_Ecrou_22_Ecrou_Hm_M12_1_RIGID/LConn1
  Transform/LConn1 -- ReferenceFrame/RConn1 -- Transform1/LConn1 -- Transform10/LConn1 -- Transform11/LConn1 -- Transform12/LConn1 -- Transform13/RConn1 -- Transform2/LConn1 -- Transform3/LConn1 -- Transform4/LConn1 -- Transform5/LConn1 -- Transform6/LConn1 -- Transform7/LConn1 -- Transform8/LConn1 -- Transform9/LConn1 -- x15060_M_01015_Ens_verin_levage_Default_1_RIGID/RConn1 -- x15060_M_01016_Ens_verin_inclinaison_Default_1_RIGID/RConn1
  Transform13/LConn1 -- F/RConn1
  Transform2/RConn1 -- x15060_M_01080_Rondelle_anti_rotation_AA_DEFAULT_2_RIGID/LConn1
  Transform3/RConn1 -- x15060_M_01052_Entretoise_pour_axe_AA_DEFAULT_5_RIGID/LConn1
  Transform4/RConn1 -- x15060_M_01052_Entretoise_pour_axe_AA_DEFAULT_4_RIGID/LConn1
  Transform5/RConn1 -- x15060_NLM_Vis_CHc_rectifi_e_a_paulement_16_L40_M12_07534_16x40/LConn1
  Transform6/RConn1 -- x15060_M_01064_Axe_pivot_AA_DEFAULT_1_RIGID/LConn1
  Transform7/RConn1 -- x15060_Rondelle_Rondelle_TresLarge_LL_8_1_RIGID/LConn1
  Transform8/RConn1 -- x15060_M_01052_Entretoise_pour_axe_AA_DEFAULT_7_RIGID/LConn1
  Transform9/RConn1 -- x15060_M_01052_Entretoise_pour_axe_AA_DEFAULT_2_RIGID/LConn1

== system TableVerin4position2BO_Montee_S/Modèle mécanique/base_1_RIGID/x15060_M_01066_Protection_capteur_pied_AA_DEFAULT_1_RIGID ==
  ReferenceFrame : sm_lib/Frames and Transforms/Reference Frame  BlockFunction=simmechanics.library.frames_transforms.reference_frame
  Solid : sm_lib/Body Elements/Solid  InertiaType=Custom  Mass=0.087205099999999994  MassUnits=kg  CenterOfMass=[37.549999999999997 30.4391 -50.920200000000001]  CenterOfMassUnits=mm  MomentsOfInertia=[245.80700000000002 281.13299999999998 368.76600000000002]  MomentsOfInertiaUnits=kg*mm^2  ProductsOfInertia=[16.622799999999998 -7.2754099999999999 -108.76200000000001]  ProductsOfInertiaUnits=kg*mm^2  DensityBased=on  Density=1000  DensityUnits=kg/(m^3)  GraphicType=FromGeometry  MarkerShape=Sphere  MarkerSize=10  MarkerSizeUnits=m  GraphicVisPropType=SimpleVisualProperties  GraphicDiffuseColor=[0.792157 0.819608 0.933333]  GraphicSpecularColor=[0.5 0.5 0.5 1.0]  GraphicAmbientColor=[0.15 0.15 0.15 1.0]  GraphicEmissiveColor=[0.0 0.0 0.0 1.0]  GraphicShininess=75  GraphicOpacity=1  GeometryShape=FromFile  RectangleSize=[1 1]  RectangleSizeUnits=m  BrickDimensions=[1 1 1]  BrickDimensionUnits=m  CylinderRadius=1  CylinderRadiusUnits=m  CylinderLength=1  CylinderLengthUnits=m  SphereRadius=1  SphereRadiusUnits=m  EllipsoidRadii=[1 1 1]  EllipsoidRadiiUnits=m  ExtrusionCrossSection=[1 1; -1 1; -1 -1; 1 -1]  ExtrusionCrossSectionUnits=m  ExtrusionLength=1  ExtrusionLengthUnits=m  PolygonNumSides=3  PolygonOuterRadius=1  PolygonOuterRadiusUnits=m  ExtGeomFileName=15060-M-01066-Protection capteur pied_AA - DEFAULT_Défaut_sldprt.STL  ExtGeomFileUnits=mm  RevolutionCrossSection=[1 1; 1 -1; 2 -1; 2 1]  RevolutionCrossSectionUnits=m  RevolutionExtent=Full  RevolutionAngle=180  RevolutionAngleUnits=deg  BlockFunction=simmechanics.library.body_elements.solid
  F : PMIOPort  Port=1  Side=Left
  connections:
  Solid/RConn1 -- ReferenceFrame/RConn1 -- F/RConn1

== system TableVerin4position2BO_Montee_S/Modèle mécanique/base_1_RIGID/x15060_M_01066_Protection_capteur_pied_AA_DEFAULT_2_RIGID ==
  ReferenceFrame : sm_lib/Frames and Transforms/Reference Frame  BlockFunction=simmechanics.library.frames_transforms.reference_frame
  Solid : sm_lib/Body Elements/Solid  InertiaType=Custom  Mass=0.087205099999999994  MassUnits=kg  CenterOfMass=[37.549999999999997 30.4391 -50.920200000000001]  CenterOfMassUnits=mm  MomentsOfInertia=[245.80700000000002 281.13299999999998 368.76600000000002]  MomentsOfInertiaUnits=kg*mm^2  ProductsOfInertia=[16.622799999999998 -7.2754099999999999 -108.76200000000001]  ProductsOfInertiaUnits=kg*mm^2  DensityBased=on  Density=1000  DensityUnits=kg/(m^3)  GraphicType=FromGeometry  MarkerShape=Sphere  MarkerSize=10  MarkerSizeUnits=m  GraphicVisPropType=SimpleVisualProperties  GraphicDiffuseColor=[0.792157 0.819608 0.933333]  GraphicSpecularColor=[0.5 0.5 0.5 1.0]  GraphicAmbientColor=[0.15 0.15 0.15 1.0]  GraphicEmissiveColor=[0.0 0.0 0.0 1.0]  GraphicShininess=75  GraphicOpacity=1  GeometryShape=FromFile  RectangleSize=[1 1]  RectangleSizeUnits=m  BrickDimensions=[1 1 1]  BrickDimensionUnits=m  CylinderRadius=1  CylinderRadiusUnits=m  CylinderLength=1  CylinderLengthUnits=m  SphereRadius=1  SphereRadiusUnits=m  EllipsoidRadii=[1 1 1]  EllipsoidRadiiUnits=m  ExtrusionCrossSection=[1 1; -1 1; -1 -1; 1 -1]  ExtrusionCrossSectionUnits=m  ExtrusionLength=1  ExtrusionLengthUnits=m  PolygonNumSides=3  PolygonOuterRadius=1  PolygonOuterRadiusUnits=m  ExtGeomFileName=15060-M-01066-Protection capteur pied_AA - DEFAULT_Défaut_sldprt.STL  ExtGeomFileUnits=mm  RevolutionCrossSection=[1 1; 1 -1; 2 -1; 2 1]  RevolutionCrossSectionUnits=m  RevolutionExtent=Full  RevolutionAngle=180  RevolutionAngleUnits=deg  BlockFunction=simmechanics.library.body_elements.solid
  F : PMIOPort  Port=1  Side=Left
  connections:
  Solid/RConn1 -- ReferenceFrame/RConn1 -- F/RConn1

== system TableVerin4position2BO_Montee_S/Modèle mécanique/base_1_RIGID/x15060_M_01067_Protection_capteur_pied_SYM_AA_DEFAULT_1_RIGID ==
  ReferenceFrame : sm_lib/Frames and Transforms/Reference Frame  BlockFunction=simmechanics.library.frames_transforms.reference_frame
  Solid : sm_lib/Body Elements/Solid  InertiaType=Custom  Mass=0.087205099999999994  MassUnits=kg  CenterOfMass=[37.549999999999997 -30.4391 -50.920200000000001]  CenterOfMassUnits=mm  MomentsOfInertia=[245.80700000000002 281.13299999999998 368.76600000000002]  MomentsOfInertiaUnits=kg*mm^2  ProductsOfInertia=[-16.622799999999998 -7.2754099999999999 108.76200000000001]  ProductsOfInertiaUnits=kg*mm^2  DensityBased=on  Density=1000  DensityUnits=kg/(m^3)  GraphicType=FromGeometry  MarkerShape=Sphere  MarkerSize=10  MarkerSizeUnits=m  GraphicVisPropType=SimpleVisualProperties  GraphicDiffuseColor=[0.792157 0.819608 0.933333]  GraphicSpecularColor=[0.5 0.5 0.5 1.0]  GraphicAmbientColor=[0.15 0.15 0.15 1.0]  GraphicEmissiveColor=[0.0 0.0 0.0 1.0]  GraphicShininess=75  GraphicOpacity=1  GeometryShape=FromFile  RectangleSize=[1 1]  RectangleSizeUnits=m  BrickDimensions=[1 1 1]  BrickDimensionUnits=m  CylinderRadius=1  CylinderRadiusUnits=m  CylinderLength=1  CylinderLengthUnits=m  SphereRadius=1  SphereRadiusUnits=m  EllipsoidRadii=[1 1 1]  EllipsoidRadiiUnits=m  ExtrusionCrossSection=[1 1; -1 1; -1 -1; 1 -1]  ExtrusionCrossSectionUnits=m  ExtrusionLength=1  ExtrusionLengthUnits=m  PolygonNumSides=3  PolygonOuterRadius=1  PolygonOuterRadiusUnits=m  ExtGeomFileName=15060-M-01067-Protection capteur pied - SYM_AA - DEFAULT_Défaut_sldprt.STL  ExtGeomFileUnits=mm  RevolutionCrossSection=[1 1; 1 -1; 2 -1; 2 1]  RevolutionCrossSectionUnits=m  RevolutionExtent=Full  RevolutionAngle=180  RevolutionAngleUnits=deg  BlockFunction=simmechanics.library.body_elements.solid
  F : PMIOPort  Port=1  Side=Left
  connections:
  Solid/RConn1 -- ReferenceFrame/RConn1 -- F/RConn1

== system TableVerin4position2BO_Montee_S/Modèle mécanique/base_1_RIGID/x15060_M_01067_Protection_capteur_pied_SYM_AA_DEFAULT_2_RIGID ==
  ReferenceFrame : sm_lib/Frames and Transforms/Reference Frame  BlockFunction=simmechanics.library.frames_transforms.reference_frame
  Solid : sm_lib/Body Elements/Solid  InertiaType=Custom  Mass=0.087205099999999994  MassUnits=kg  CenterOfMass=[37.549999999999997 -30.4391 -50.920200000000001]  CenterOfMassUnits=mm  MomentsOfInertia=[245.80700000000002 281.13299999999998 368.76600000000002]  MomentsOfInertiaUnits=kg*mm^2  ProductsOfInertia=[-16.622799999999998 -7.2754099999999999 108.76200000000001]  ProductsOfInertiaUnits=kg*mm^2  DensityBased=on  Density=1000  DensityUnits=kg/(m^3)  GraphicType=FromGeometry  MarkerShape=Sphere  MarkerSize=10  MarkerSizeUnits=m  GraphicVisPropType=SimpleVisualProperties  GraphicDiffuseColor=[0.792157 0.819608 0.933333]  GraphicSpecularColor=[0.5 0.5 0.5 1.0]  GraphicAmbientColor=[0.15 0.15 0.15 1.0]  GraphicEmissiveColor=[0.0 0.0 0.0 1.0]  GraphicShininess=75  GraphicOpacity=1  GeometryShape=FromFile  RectangleSize=[1 1]  RectangleSizeUnits=m  BrickDimensions=[1 1 1]  BrickDimensionUnits=m  CylinderRadius=1  CylinderRadiusUnits=m  CylinderLength=1  CylinderLengthUnits=m  SphereRadius=1  SphereRadiusUnits=m  EllipsoidRadii=[1 1 1]  EllipsoidRadiiUnits=m  ExtrusionCrossSection=[1 1; -1 1; -1 -1; 1 -1]  ExtrusionCrossSectionUnits=m  ExtrusionLength=1  ExtrusionLengthUnits=m  PolygonNumSides=3  PolygonOuterRadius=1  PolygonOuterRadiusUnits=m  ExtGeomFileName=15060-M-01067-Protection capteur pied - SYM_AA - DEFAULT_Défaut_sldprt.STL  ExtGeomFileUnits=mm  RevolutionCrossSection=[1 1; 1 -1; 2 -1; 2 1]  RevolutionCrossSectionUnits=m  RevolutionExtent=Full  RevolutionAngle=180  RevolutionAngleUnits=deg  BlockFunction=simmechanics.library.body_elements.solid
  F : PMIOPort  Port=1  Side=Left
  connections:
  Solid/RConn1 -- ReferenceFrame/RConn1 -- F/RConn1

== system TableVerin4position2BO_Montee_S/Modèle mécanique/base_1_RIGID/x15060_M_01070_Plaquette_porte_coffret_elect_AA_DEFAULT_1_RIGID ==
  ReferenceFrame : sm_lib/Frames and Transforms/Reference Frame  BlockFunction=simmechanics.library.frames_transforms.reference_frame
  Solid : sm_lib/Body Elements/Solid  InertiaType=Custom  Mass=0.019828200000000001  MassUnits=kg  CenterOfMass=[28.216799999999999 0 1.98702]  CenterOfMassUnits=mm  MomentsOfInertia=[5.8898700000000002 11.8095 17.646600000000003]  MomentsOfInertiaUnits=kg*mm^2  ProductsOfInertia=[0 0.0072600900000000003 0]  ProductsOfInertiaUnits=kg*mm^2  DensityBased=on  Density=1000  DensityUnits=kg/(m^3)  GraphicType=FromGeometry  MarkerShape=Sphere  MarkerSize=10  MarkerSizeUnits=m  GraphicVisPropType=SimpleVisualProperties  GraphicDiffuseColor=[0.792157 0.819608 0.933333]  GraphicSpecularColor=[0.5 0.5 0.5 1.0]  GraphicAmbientColor=[0.15 0.15 0.15 1.0]  GraphicEmissiveColor=[0.0 0.0 0.0 1.0]  GraphicShininess=75  GraphicOpacity=1  GeometryShape=FromFile  RectangleSize=[1 1]  RectangleSizeUnits=m  BrickDimensions=[1 1 1]  BrickDimensionUnits=m  CylinderRadius=1  CylinderRadiusUnits=m  CylinderLength=1  CylinderLengthUnits=m  SphereRadius=1  SphereRadiusUnits=m  EllipsoidRadii=[1 1 1]  EllipsoidRadiiUnits=m  ExtrusionCrossSection=[1 1; -1 1; -1 -1; 1 -1]  ExtrusionCrossSectionUnits=m  ExtrusionLength=1  ExtrusionLengthUnits=m  PolygonNumSides=3  PolygonOuterRadius=1  PolygonOuterRadiusUnits=m  ExtGeomFileName=15060-M-01070-Plaquette porte coffret elect._AA - DEFAULT_Défaut_sldprt.STL  ExtGeomFileUnits=mm  RevolutionCrossSection=[1 1; 1 -1; 2 -1; 2 1]  RevolutionCrossSectionUnits=m  RevolutionExtent=Full  RevolutionAngle=180  RevolutionAngleUnits=deg  BlockFunction=simmechanics.library.body_elements.solid
  F : PMIOPort  Port=1  Side=Left
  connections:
  Solid/RConn1 -- ReferenceFrame/RConn1 -- F/RConn1

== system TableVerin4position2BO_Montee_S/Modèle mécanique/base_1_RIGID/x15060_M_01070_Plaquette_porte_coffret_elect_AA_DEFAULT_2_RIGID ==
  ReferenceFrame : sm_lib/Frames and Transforms/Reference Frame  BlockFunction=simmechanics.library.frames_transforms.reference_frame
  Solid : sm_lib/Body Elements/Solid  InertiaType=Custom  Mass=0.019828200000000001  MassUnits=kg  CenterOfMass=[28.216799999999999 0 1.98702]  CenterOfMassUnits=mm  MomentsOfInertia=[5.8898700000000002 11.8095 17.646600000000003]  MomentsOfInertiaUnits=kg*mm^2  ProductsOfInertia=[0 0.0072600900000000003 0]  ProductsOfInertiaUnits=kg*mm^2  DensityBased=on  Density=1000  DensityUnits=kg/(m^3)  GraphicType=FromGeometry  MarkerShape=Sphere  MarkerSize=10  MarkerSizeUnits=m  GraphicVisPropType=SimpleVisualProperties  GraphicDiffuseColor=[0.792157 0.819608 0.933333]  GraphicSpecularColor=[0.5 0.5 0.5 1.0]  GraphicAmbientColor=[0.15 0.15 0.15 1.0]  GraphicEmissiveColor=[0.0 0.0 0.0 1.0]  GraphicShininess=75  GraphicOpacity=1  GeometryShape=FromFile  RectangleSize=[1 1]  RectangleSizeUnits=m  BrickDimensions=[1 1 1]  BrickDimensionUnits=m  CylinderRadius=1  CylinderRadiusUnits=m  CylinderLength=1  CylinderLengthUnits=m  SphereRadius=1  SphereRadiusUnits=m  EllipsoidRadii=[1 1 1]  EllipsoidRadiiUnits=m  ExtrusionCrossSection=[1 1; -1 1; -1 -1; 1 -1]  ExtrusionCrossSectionUnits=m  ExtrusionLength=1  ExtrusionLengthUnits=m  PolygonNumSides=3  PolygonOuterRadius=1  PolygonOuterRadiusUnits=m  ExtGeomFileName=15060-M-01070-Plaquette porte coffret elect._AA - DEFAULT_Défaut_sldprt.STL  ExtGeomFileUnits=mm  RevolutionCrossSection=[1 1; 1 -1; 2 -1; 2 1]  RevolutionCrossSectionUnits=m  RevolutionExtent=Full  RevolutionAngle=180  RevolutionAngleUnits=deg  BlockFunction=simmechanics.library.body_elements.solid
  F : PMIOPort  Port=1  Side=Left
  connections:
  Solid/RConn1 -- ReferenceFrame/RConn1 -- F/RConn1

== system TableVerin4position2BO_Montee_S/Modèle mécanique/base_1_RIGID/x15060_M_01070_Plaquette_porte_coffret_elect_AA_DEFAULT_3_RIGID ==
  ReferenceFrame : sm_lib/Frames and Transforms/Reference Frame  BlockFunction=simmechanics.library.frames_transforms.reference_frame
  Solid : sm_lib/Body Elements/Solid  InertiaType=Custom  Mass=0.019828200000000001  MassUnits=kg  CenterOfMass=[28.216799999999999 0 1.98702]  CenterOfMassUnits=mm  MomentsOfInertia=[5.8898700000000002 11.8095 17.646600000000003]  MomentsOfInertiaUnits=kg*mm^2  ProductsOfInertia=[0 0.0072600900000000003 0]  ProductsOfInertiaUnits=kg*mm^2  DensityBased=on  Density=1000  DensityUnits=kg/(m^3)  GraphicType=FromGeometry  MarkerShape=Sphere  MarkerSize=10  MarkerSizeUnits=m  GraphicVisPropType=SimpleVisualProperties  GraphicDiffuseColor=[0.792157 0.819608 0.933333]  GraphicSpecularColor=[0.5 0.5 0.5 1.0]  GraphicAmbientColor=[0.15 0.15 0.15 1.0]  GraphicEmissiveColor=[0.0 0.0 0.0 1.0]  GraphicShininess=75  GraphicOpacity=1  GeometryShape=FromFile  RectangleSize=[1 1]  RectangleSizeUnits=m  BrickDimensions=[1 1 1]  BrickDimensionUnits=m  CylinderRadius=1  CylinderRadiusUnits=m  CylinderLength=1  CylinderLengthUnits=m  SphereRadius=1  SphereRadiusUnits=m  EllipsoidRadii=[1 1 1]  EllipsoidRadiiUnits=m  ExtrusionCrossSection=[1 1; -1 1; -1 -1; 1 -1]  ExtrusionCrossSectionUnits=m  ExtrusionLength=1  ExtrusionLengthUnits=m  PolygonNumSides=3  PolygonOuterRadius=1  PolygonOuterRadiusUnits=m  ExtGeomFileName=15060-M-01070-Plaquette porte coffret elect._AA - DEFAULT_Défaut_sldprt.STL  ExtGeomFileUnits=mm  RevolutionCrossSection=[1 1; 1 -1; 2 -1; 2 1]  RevolutionCrossSectionUnits=m  RevolutionExtent=Full  RevolutionAngle=180  RevolutionAngleUnits=deg  BlockFunction=simmechanics.library.body_elements.solid
  F : PMIOPort  Port=1  Side=Left
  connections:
  Solid/RConn1 -- ReferenceFrame/RConn1 -- F/RConn1

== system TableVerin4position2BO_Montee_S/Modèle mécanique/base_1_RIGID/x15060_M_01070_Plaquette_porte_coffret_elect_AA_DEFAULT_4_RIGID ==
  ReferenceFrame : sm_lib/Frames and Transforms/Reference Frame  BlockFunction=simmechanics.library.frames_transforms.reference_frame
  Solid : sm_lib/Body Elements/Solid  InertiaType=Custom  Mass=0.019828200000000001  MassUnits=kg  CenterOfMass=[28.216799999999999 0 1.98702]  CenterOfMassUnits=mm  MomentsOfInertia=[5.8898700000000002 11.8095 17.646600000000003]  MomentsOfInertiaUnits=kg*mm^2  ProductsOfInertia=[0 0.0072600900000000003 0]  ProductsOfInertiaUnits=kg*mm^2  DensityBased=on  Density=1000  DensityUnits=kg/(m^3)  GraphicType=FromGeometry  MarkerShape=Sphere  MarkerSize=10  MarkerSizeUnits=m  GraphicVisPropType=SimpleVisualProperties  GraphicDiffuseColor=[0.792157 0.819608 0.933333]  GraphicSpecularColor=[0.5 0.5 0.5 1.0]  GraphicAmbientColor=[0.15 0.15 0.15 1.0]  GraphicEmissiveColor=[0.0 0.0 0.0 1.0]  GraphicShininess=75  GraphicOpacity=1  GeometryShape=FromFile  RectangleSize=[1 1]  RectangleSizeUnits=m  BrickDimensions=[1 1 1]  BrickDimensionUnits=m  CylinderRadius=1  CylinderRadiusUnits=m  CylinderLength=1  CylinderLengthUnits=m  SphereRadius=1  SphereRadiusUnits=m  EllipsoidRadii=[1 1 1]  EllipsoidRadiiUnits=m  ExtrusionCrossSection=[1 1; -1 1; -1 -1; 1 -1]  ExtrusionCrossSectionUnits=m  ExtrusionLength=1  ExtrusionLengthUnits=m  PolygonNumSides=3  PolygonOuterRadius=1  PolygonOuterRadiusUnits=m  ExtGeomFileName=15060-M-01070-Plaquette porte coffret elect._AA - DEFAULT_Défaut_sldprt.STL  ExtGeomFileUnits=mm  RevolutionCrossSection=[1 1; 1 -1; 2 -1; 2 1]  RevolutionCrossSectionUnits=m  RevolutionExtent=Full  RevolutionAngle=180  RevolutionAngleUnits=deg  BlockFunction=simmechanics.library.body_elements.solid
  F : PMIOPort  Port=1  Side=Left
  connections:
  Solid/RConn1 -- ReferenceFrame/RConn1 -- F/RConn1

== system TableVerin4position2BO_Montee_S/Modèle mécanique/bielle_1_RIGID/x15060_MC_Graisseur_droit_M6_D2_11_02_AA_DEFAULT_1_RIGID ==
  ReferenceFrame : sm_lib/Frames and Transforms/Reference Frame  BlockFunction=simmechanics.library.frames_transforms.reference_frame
  Solid : sm_lib/Body Elements/Solid  InertiaType=Custom  Mass=0.00048530999999999997  MassUnits=kg  CenterOfMass=[-4.20691e-05 7.7280100000000003 0]  CenterOfMassUnits=mm  MomentsOfInertia=[0.0093005700000000011 0.0026027099999999998 0.0093005700000000011]  MomentsOfInertiaUnits=kg*mm^2  ProductsOfInertia=[0 0 -1.02464e-07]  ProductsOfInertiaUnits=kg*mm^2  DensityBased=on  Density=1000  DensityUnits=kg/(m^3)  GraphicType=FromGeometry  MarkerShape=Sphere  MarkerSize=10  MarkerSizeUnits=m  GraphicVisPropType=SimpleVisualProperties  GraphicDiffuseColor=[0.792157 0.819608 0.933333]  GraphicSpecularColor=[0.5 0.5 0.5 1.0]  GraphicAmbientColor=[0.15 0.15 0.15 1.0]  GraphicEmissiveColor=[0.0 0.0 0.0 1.0]  GraphicShininess=75  GraphicOpacity=1  GeometryShape=FromFile  RectangleSize=[1 1]  RectangleSizeUnits=m  BrickDimensions=[1 1 1]  BrickDimensionUnits=m  CylinderRadius=1  CylinderRadiusUnits=m  CylinderLength=1  CylinderLengthUnits=m  SphereRadius=1  SphereRadiusUnits=m  EllipsoidRadii=[1 1 1]  EllipsoidRadiiUnits=m  ExtrusionCrossSection=[1 1; -1 1; -1 -1; 1 -1]  ExtrusionCrossSectionUnits=m  ExtrusionLength=1  ExtrusionLengthUnits=m  PolygonNumSides=3  PolygonOuterRadius=1  PolygonOuterRadiusUnits=m  ExtGeomFileName=15060-MC-Graisseur droit M6 - D2-11-02_AA - DEFAULT_Défaut_sldprt.STL  ExtGeomFileUnits=mm  RevolutionCrossSection=[1 1; 1 -1; 2 -1; 2 1]  RevolutionCrossSectionUnits=m  RevolutionExtent=Full  RevolutionAngle=180  RevolutionAngleUnits=deg  BlockFunction=simmechanics.library.body_elements.solid
  F : PMIOPort  Port=1  Side=Left
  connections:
  Solid/RConn1 -- ReferenceFrame/RConn1 -- F/RConn1

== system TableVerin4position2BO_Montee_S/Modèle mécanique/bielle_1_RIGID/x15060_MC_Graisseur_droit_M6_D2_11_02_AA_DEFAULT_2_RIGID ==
  ReferenceFrame : sm_lib/Frames and Transforms/Reference Frame  BlockFunction=simmechanics.library.frames_transforms.reference_frame
  Solid : sm_lib/Body Elements/Solid  InertiaType=Custom  Mass=0.00048530999999999997  MassUnits=kg  CenterOfMass=[-4.20691e-05 7.7280100000000003 0]  CenterOfMassUnits=mm  MomentsOfInertia=[0.0093005700000000011 0.0026027099999999998 0.0093005700000000011]  MomentsOfInertiaUnits=kg*mm^2  ProductsOfInertia=[0 0 -1.02464e-07]  ProductsOfInertiaUnits=kg*mm^2  DensityBased=on  Density=1000  DensityUnits=kg/(m^3)  GraphicType=FromGeometry  MarkerShape=Sphere  MarkerSize=10  MarkerSizeUnits=m  GraphicVisPropType=SimpleVisualProperties  GraphicDiffuseColor=[0.792157 0.819608 0.933333]  GraphicSpecularColor=[0.5 0.5 0.5 1.0]  GraphicAmbientColor=[0.15 0.15 0.15 1.0]  GraphicEmissiveColor=[0.0 0.0 0.0 1.0]  GraphicShininess=75  GraphicOpacity=1  GeometryShape=FromFile  RectangleSize=[1 1]  RectangleSizeUnits=m  BrickDimensions=[1 1 1]  BrickDimensionUnits=m  CylinderRadius=1  CylinderRadiusUnits=m  CylinderLength=1  CylinderLengthUnits=m  SphereRadius=1  SphereRadiusUnits=m  EllipsoidRadii=[1 1 1]  EllipsoidRadiiUnits=m  ExtrusionCrossSection=[1 1; -1 1; -1 -1; 1 -1]  ExtrusionCrossSectionUnits=m  ExtrusionLength=1  ExtrusionLengthUnits=m  PolygonNumSides=3  PolygonOuterRadius=1  PolygonOuterRadiusUnits=m  ExtGeomFileName=15060-MC-Graisseur droit M6 - D2-11-02_AA - DEFAULT_Défaut_sldprt.STL  ExtGeomFileUnits=mm  RevolutionCrossSection=[1 1; 1 -1; 2 -1; 2 1]  RevolutionCrossSectionUnits=m  RevolutionExtent=Full  RevolutionAngle=180  RevolutionAngleUnits=deg  BlockFunction=simmechanics.library.body_elements.solid
  F : PMIOPort  Port=1  Side=Left
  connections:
  Solid/RConn1 -- ReferenceFrame/RConn1 -- F/RConn1

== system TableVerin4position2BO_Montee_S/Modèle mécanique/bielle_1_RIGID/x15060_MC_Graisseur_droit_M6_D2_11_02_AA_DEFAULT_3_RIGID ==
  ReferenceFrame : sm_lib/Frames and Transforms/Reference Frame  BlockFunction=simmechanics.library.frames_transforms.reference_frame
  Solid : sm_lib/Body Elements/Solid  InertiaType=Custom  Mass=0.00048530999999999997  MassUnits=kg  CenterOfMass=[-4.20691e-05 7.7280100000000003 0]  CenterOfMassUnits=mm  MomentsOfInertia=[0.0093005700000000011 0.0026027099999999998 0.0093005700000000011]  MomentsOfInertiaUnits=kg*mm^2  ProductsOfInertia=[0 0 -1.02464e-07]  ProductsOfInertiaUnits=kg*mm^2  DensityBased=on  Density=1000  DensityUnits=kg/(m^3)  GraphicType=FromGeometry  MarkerShape=Sphere  MarkerSize=10  MarkerSizeUnits=m  GraphicVisPropType=SimpleVisualProperties  GraphicDiffuseColor=[0.792157 0.819608 0.933333]  GraphicSpecularColor=[0.5 0.5 0.5 1.0]  GraphicAmbientColor=[0.15 0.15 0.15 1.0]  GraphicEmissiveColor=[0.0 0.0 0.0 1.0]  GraphicShininess=75  GraphicOpacity=1  GeometryShape=FromFile  RectangleSize=[1 1]  RectangleSizeUnits=m  BrickDimensions=[1 1 1]  BrickDimensionUnits=m  CylinderRadius=1  CylinderRadiusUnits=m  CylinderLength=1  CylinderLengthUnits=m  SphereRadius=1  SphereRadiusUnits=m  EllipsoidRadii=[1 1 1]  EllipsoidRadiiUnits=m  ExtrusionCrossSection=[1 1; -1 1; -1 -1; 1 -1]  ExtrusionCrossSectionUnits=m  ExtrusionLength=1  ExtrusionLengthUnits=m  PolygonNumSides=3  PolygonOuterRadius=1  PolygonOuterRadiusUnits=m  ExtGeomFileName=15060-MC-Graisseur droit M6 - D2-11-02_AA - DEFAULT_Défaut_sldprt.STL  ExtGeomFileUnits=mm  RevolutionCrossSection=[1 1; 1 -1; 2 -1; 2 1]  RevolutionCrossSectionUnits=m  RevolutionExtent=Full  RevolutionAngle=180  RevolutionAngleUnits=deg  BlockFunction=simmechanics.library.body_elements.solid
  F : PMIOPort  Port=1  Side=Left
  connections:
  Solid/RConn1 -- ReferenceFrame/RConn1 -- F/RConn1

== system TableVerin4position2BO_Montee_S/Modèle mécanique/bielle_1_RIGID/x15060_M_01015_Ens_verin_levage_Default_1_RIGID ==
  ReferenceFrame : sm_lib/Frames and Transforms/Reference Frame  BlockFunction=simmechanics.library.frames_transforms.reference_frame
  Transform : sm_lib/Frames and Transforms/Rigid Transform  TranslationMethod=Cartesian  TranslationLengthUnit=mm  TranslationStandardAxis=+Z  TranslationStandardOffset=0  TranslationCartesianOffset=[-517.07099999999991 35.420000000000002 16.307499999999997]  TranslationROffset=0  TranslationROffsetUnits=m  TranslationZOffset=0  TranslationZOffsetUnits=m  TranslationThetaOffset=0  TranslationThetaOffsetUnits=deg  RotationMethod=ArbitraryAxis  RotationAngleUnits=rad  RotationStandardAxis=+Z  RotationAngle=1.6424450276988594  RotationArbitraryAxis=[-0.25846666391264611 0.25846666391264667 -0.9308007129841136]  FollAlignAxisA=+X  BaseAlignAxisA=+Y  FollAlignAxisB=+Y  BaseAlignAxisB=+Z  BlockFunction=simmechanics.library.frames_transforms.rigid_transform
  F : PMIOPort  Port=1  Side=Right
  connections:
  ReferenceFrame/RConn1 -- Transform/RConn1
  Transform/LConn1 -- F/RConn1

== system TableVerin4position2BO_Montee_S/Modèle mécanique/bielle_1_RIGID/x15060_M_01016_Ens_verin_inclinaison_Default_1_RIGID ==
  ReferenceFrame : sm_lib/Frames and Transforms/Reference Frame  BlockFunction=simmechanics.library.frames_transforms.reference_frame
  Transform : sm_lib/Frames and Transforms/Rigid Transform  TranslationMethod=Cartesian  TranslationLengthUnit=mm  TranslationStandardAxis=+Z  TranslationStandardOffset=0  TranslationCartesianOffset=[-534.86299999999994 -149.5 81.105599999999995]  TranslationROffset=0  TranslationROffsetUnits=m  TranslationZOffset=0  TranslationZOffsetUnits=m  TranslationThetaOffset=0  TranslationThetaOffsetUnits=deg  RotationMethod=ArbitraryAxis  RotationAngleUnits=rad  RotationStandardAxis=+Z  RotationAngle=0.9229778637121423  RotationArbitraryAxis=[1.419208253804229e-15 1 -3.8905721330019236e-16]  FollAlignAxisA=+X  BaseAlignAxisA=+Y  FollAlignAxisB=+Y  BaseAlignAxisB=+Z  BlockFunction=simmechanics.library.frames_transforms.rigid_transform
  F : PMIOPort  Port=1  Side=Right
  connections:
  ReferenceFrame/RConn1 -- Transform/RConn1
  Transform/LConn1 -- F/RConn1

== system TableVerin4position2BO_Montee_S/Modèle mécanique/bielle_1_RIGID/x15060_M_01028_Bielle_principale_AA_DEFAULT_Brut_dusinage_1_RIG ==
  ReferenceFrame : sm_lib/Frames and Transforms/Reference Frame  BlockFunction=simmechanics.library.frames_transforms.reference_frame
  Solid : sm_lib/Body Elements/Solid  InertiaType=Custom  Mass=16.907399999999999  MassUnits=kg  CenterOfMass=[-221.99799999999999 162.18099999999998 0.54479199999999994]  CenterOfMassUnits=mm  MomentsOfInertia=[302829 438662 552803]  MomentsOfInertiaUnits=kg*mm^2  ProductsOfInertia=[1680.8599999999999 -2017.1499999999996 -258077.99999999997]  ProductsOfInertiaUnits=kg*mm^2  DensityBased=on  Density=1000  DensityUnits=kg/(m^3)  GraphicType=FromGeometry  MarkerShape=Sphere  MarkerSize=10  MarkerSizeUnits=m  GraphicVisPropType=SimpleVisualProperties  GraphicDiffuseColor=[0.776471 0.756863 0.737255]  GraphicSpecularColor=[0.5 0.5 0.5 1.0]  GraphicAmbientColor=[0.15 0.15 0.15 1.0]  GraphicEmissiveColor=[0.0 0.0 0.0 1.0]  GraphicShininess=75  GraphicOpacity=1  GeometryShape=FromFile  RectangleSize=[1 1]  RectangleSizeUnits=m  BrickDimensions=[1 1 1]  BrickDimensionUnits=m  CylinderRadius=1  CylinderRadiusUnits=m  CylinderLength=1  CylinderLengthUnits=m  SphereRadius=1  SphereRadiusUnits=m  EllipsoidRadii=[1 1 1]  EllipsoidRadiiUnits=m  ExtrusionCrossSection=[1 1; -1 1; -1 -1; 1 -1]  ExtrusionCrossSectionUnits=m  ExtrusionLength=1  ExtrusionLengthUnits=m  PolygonNumSides=3  PolygonOuterRadius=1  PolygonOuterRadiusUnits=m  ExtGeomFileName=15060-M-01028-Bielle principale_AA - DEFAULT_Brut d''usinage__Défaut_sldprt.STL  ExtGeomFileUnits=mm  RevolutionCrossSection=[1 1; 1 -1; 2 -1; 2 1]  RevolutionCrossSectionUnits=m  RevolutionExtent=Full  RevolutionAngle=180  RevolutionAngleUnits=deg  BlockFunction=simmechanics.library.body_elements.solid
  F : PMIOPort  Port=1  Side=Left
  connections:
  Solid/RConn1 -- ReferenceFrame/RConn1 -- F/RConn1

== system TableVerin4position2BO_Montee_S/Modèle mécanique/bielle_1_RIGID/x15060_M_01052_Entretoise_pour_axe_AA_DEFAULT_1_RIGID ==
  ReferenceFrame : sm_lib/Frames and Transforms/Reference Frame  BlockFunction=simmechanics.library.frames_transforms.reference_frame
  Solid : sm_lib/Body Elements/Solid  InertiaType=Custom  Mass=0.00088563500000000007  MassUnits=kg  CenterOfMass=[0.75 0 0]  CenterOfMassUnits=mm  MomentsOfInertia=[0.14350000000000002 0.071916300000000002 0.071916300000000002]  MomentsOfInertiaUnits=kg*mm^2  ProductsOfInertia=[0 0 0]  ProductsOfInertiaUnits=kg*mm^2  DensityBased=on  Density=1000  DensityUnits=kg/(m^3)  GraphicType=FromGeometry  MarkerShape=Sphere  MarkerSize=10  MarkerSizeUnits=m  GraphicVisPropType=SimpleVisualProperties  GraphicDiffuseColor=[0.792157 0.819608 0.933333]  GraphicSpecularColor=[0.5 0.5 0.5 1.0]  GraphicAmbientColor=[0.15 0.15 0.15 1.0]  GraphicEmissiveColor=[0.0 0.0 0.0 1.0]  GraphicShininess=75  GraphicOpacity=1  GeometryShape=FromFile  RectangleSize=[1 1]  RectangleSizeUnits=m  BrickDimensions=[1 1 1]  BrickDimensionUnits=m  CylinderRadius=1  CylinderRadiusUnits=m  CylinderLength=1  CylinderLengthUnits=m  SphereRadius=1  SphereRadiusUnits=m  EllipsoidRadii=[1 1 1]  EllipsoidRadiiUnits=m  ExtrusionCrossSection=[1 1; -1 1; -1 -1; 1 -1]  ExtrusionCrossSectionUnits=m  ExtrusionLength=1  ExtrusionLengthUnits=m  PolygonNumSides=3  PolygonOuterRadius=1  PolygonOuterRadiusUnits=m  ExtGeomFileName=15060-M-01052-Entretoise pour axe_AA - DEFAULT_Défaut_sldprt.STL  ExtGeomFileUnits=mm  RevolutionCrossSection=[1 1; 1 -1; 2 -1; 2 1]  RevolutionCrossSectionUnits=m  RevolutionExtent=Full  RevolutionAngle=180  RevolutionAngleUnits=deg  BlockFunction=simmechanics.library.body_elements.solid
  F : PMIOPort  Port=1  Side=Left
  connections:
  Solid/RConn1 -- ReferenceFrame/RConn1 -- F/RConn1

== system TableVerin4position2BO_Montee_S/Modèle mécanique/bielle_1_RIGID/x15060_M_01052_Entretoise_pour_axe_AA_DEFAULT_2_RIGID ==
  ReferenceFrame : sm_lib/Frames and Transforms/Reference Frame  BlockFunction=simmechanics.library.frames_transforms.reference_frame
  Solid : sm_lib/Body Elements/Solid  InertiaType=Custom  Mass=0.00088563500000000007  MassUnits=kg  CenterOfMass=[0.75 0 0]  CenterOfMassUnits=mm  MomentsOfInertia=[0.14350000000000002 0.071916300000000002 0.071916300000000002]  MomentsOfInertiaUnits=kg*mm^2  ProductsOfInertia=[0 0 0]  ProductsOfInertiaUnits=kg*mm^2  DensityBased=on  Density=1000  DensityUnits=kg/(m^3)  GraphicType=FromGeometry  MarkerShape=Sphere  MarkerSize=10  MarkerSizeUnits=m  GraphicVisPropType=SimpleVisualProperties  GraphicDiffuseColor=[0.792157 0.819608 0.933333]  GraphicSpecularColor=[0.5 0.5 0.5 1.0]  GraphicAmbientColor=[0.15 0.15 0.15 1.0]  GraphicEmissiveColor=[0.0 0.0 0.0 1.0]  GraphicShininess=75  GraphicOpacity=1  GeometryShape=FromFile  RectangleSize=[1 1]  RectangleSizeUnits=m  BrickDimensions=[1 1 1]  BrickDimensionUnits=m  CylinderRadius=1  CylinderRadiusUnits=m  CylinderLength=1  CylinderLengthUnits=m  SphereRadius=1  SphereRadiusUnits=m  EllipsoidRadii=[1 1 1]  EllipsoidRadiiUnits=m  ExtrusionCrossSection=[1 1; -1 1; -1 -1; 1 -1]  ExtrusionCrossSectionUnits=m  ExtrusionLength=1  ExtrusionLengthUnits=m  PolygonNumSides=3  PolygonOuterRadius=1  PolygonOuterRadiusUnits=m  ExtGeomFileName=15060-M-01052-Entretoise pour axe_AA - DEFAULT_Défaut_sldprt.STL  ExtGeomFileUnits=mm  RevolutionCrossSection=[1 1; 1 -1; 2 -1; 2 1]  RevolutionCrossSectionUnits=m  RevolutionExtent=Full  RevolutionAngle=180  RevolutionAngleUnits=deg  BlockFunction=simmechanics.library.body_elements.solid
  F : PMIOPort  Port=1  Side=Left
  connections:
  Solid/RConn1 -- ReferenceFrame/RConn1 -- F/RConn1

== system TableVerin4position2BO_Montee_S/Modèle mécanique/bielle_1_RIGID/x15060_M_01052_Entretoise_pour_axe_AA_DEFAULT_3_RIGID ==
  ReferenceFrame : sm_lib/Frames and Transforms/Reference Frame  BlockFunction=simmechanics.library.frames_transforms.reference_frame
  Solid : sm_lib/Body Elements/Solid  InertiaType=Custom  Mass=0.00088563500000000007  MassUnits=kg  CenterOfMass=[0.75 0 0]  CenterOfMassUnits=mm  MomentsOfInertia=[0.14350000000000002 0.071916300000000002 0.071916300000000002]  MomentsOfInertiaUnits=kg*mm^2  ProductsOfInertia=[0 0 0]  ProductsOfInertiaUnits=kg*mm^2  DensityBased=on  Density=1000  DensityUnits=kg/(m^3)  GraphicType=FromGeometry  MarkerShape=Sphere  MarkerSize=10  MarkerSizeUnits=m  GraphicVisPropType=SimpleVisualProperties  GraphicDiffuseColor=[0.792157 0.819608 0.933333]  GraphicSpecularColor=[0.5 0.5 0.5 1.0]  GraphicAmbientColor=[0.15 0.15 0.15 1.0]  GraphicEmissiveColor=[0.0 0.0 0.0 1.0]  GraphicShininess=75  GraphicOpacity=1  GeometryShape=FromFile  RectangleSize=[1 1]  RectangleSizeUnits=m  BrickDimensions=[1 1 1]  BrickDimensionUnits=m  CylinderRadius=1  CylinderRadiusUnits=m  CylinderLength=1  CylinderLengthUnits=m  SphereRadius=1  SphereRadiusUnits=m  EllipsoidRadii=[1 1 1]  EllipsoidRadiiUnits=m  ExtrusionCrossSection=[1 1; -1 1; -1 -1; 1 -1]  ExtrusionCrossSectionUnits=m  ExtrusionLength=1  ExtrusionLengthUnits=m  PolygonNumSides=3  PolygonOuterRadius=1  PolygonOuterRadiusUnits=m  ExtGeomFileName=15060-M-01052-Entretoise pour axe_AA - DEFAULT_Défaut_sldprt.STL  ExtGeomFileUnits=mm  RevolutionCrossSection=[1 1; 1 -1; 2 -1; 2 1]  RevolutionCrossSectionUnits=m  RevolutionExtent=Full  RevolutionAngle=180  RevolutionAngleUnits=deg  BlockFunction=simmechanics.library.body_elements.solid
  F : PMIOPort  Port=1  Side=Left
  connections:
  Solid/RConn1 -- ReferenceFrame/RConn1 -- F/RConn1

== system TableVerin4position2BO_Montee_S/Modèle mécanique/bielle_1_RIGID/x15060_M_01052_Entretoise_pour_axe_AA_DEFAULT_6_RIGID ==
  ReferenceFrame : sm_lib/Frames and Transforms/Reference Frame  BlockFunction=simmechanics.library.frames_transforms.reference_frame
  Solid : sm_lib/Body Elements/Solid  InertiaType=Custom  Mass=0.00088563500000000007  MassUnits=kg  CenterOfMass=[0.75 0 0]  CenterOfMassUnits=mm  MomentsOfInertia=[0.14350000000000002 0.071916300000000002 0.071916300000000002]  MomentsOfInertiaUnits=kg*mm^2  ProductsOfInertia=[0 0 0]  ProductsOfInertiaUnits=kg*mm^2  DensityBased=on  Density=1000  DensityUnits=kg/(m^3)  GraphicType=FromGeometry  MarkerShape=Sphere  MarkerSize=10  MarkerSizeUnits=m  GraphicVisPropType=SimpleVisualProperties  GraphicDiffuseColor=[0.792157 0.819608 0.933333]  GraphicSpecularColor=[0.5 0.5 0.5 1.0]  GraphicAmbientColor=[0.15 0.15 0.15 1.0]  GraphicEmissiveColor=[0.0 0.0 0.0 1.0]  GraphicShininess=75  GraphicOpacity=1  GeometryShape=FromFile  RectangleSize=[1 1]  RectangleSizeUnits=m  BrickDimensions=[1 1 1]  BrickDimensionUnits=m  CylinderRadius=1  CylinderRadiusUnits=m  CylinderLength=1  CylinderLengthUnits=m  SphereRadius=1  SphereRadiusUnits=m  EllipsoidRadii=[1 1 1]  EllipsoidRadiiUnits=m  ExtrusionCrossSection=[1 1; -1 1; -1 -1; 1 -1]  ExtrusionCrossSectionUnits=m  ExtrusionLength=1  ExtrusionLengthUnits=m  PolygonNumSides=3  PolygonOuterRadius=1  PolygonOuterRadiusUnits=m  ExtGeomFileName=15060-M-01052-Entretoise pour axe_AA - DEFAULT_Défaut_sldprt.STL  ExtGeomFileUnits=mm  RevolutionCrossSection=[1 1; 1 -1; 2 -1; 2 1]  RevolutionCrossSectionUnits=m  RevolutionExtent=Full  RevolutionAngle=180  RevolutionAngleUnits=deg  BlockFunction=simmechanics.library.body_elements.solid
  F : PMIOPort  Port=1  Side=Left
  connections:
  Solid/RConn1 -- ReferenceFrame/RConn1 -- F/RConn1

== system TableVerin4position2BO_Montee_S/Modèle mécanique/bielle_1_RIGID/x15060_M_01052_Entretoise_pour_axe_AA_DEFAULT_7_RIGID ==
  ReferenceFrame : sm_lib/Frames and Transforms/Reference Frame  BlockFunction=simmechanics.library.frames_transforms.reference_frame
  Solid : sm_lib/Body Elements/Solid  InertiaType=Custom  Mass=0.00088563500000000007  MassUnits=kg  CenterOfMass=[0.75 0 0]  CenterOfMassUnits=mm  MomentsOfInertia=[0.14350000000000002 0.071916300000000002 0.071916300000000002]  MomentsOfInertiaUnits=kg*mm^2  ProductsOfInertia=[0 0 0]  ProductsOfInertiaUnits=kg*mm^2  DensityBased=on  Density=1000  DensityUnits=kg/(m^3)  GraphicType=FromGeometry  MarkerShape=Sphere  MarkerSize=10  MarkerSizeUnits=m  GraphicVisPropType=SimpleVisualProperties  GraphicDiffuseColor=[0.792157 0.819608 0.933333]  GraphicSpecularColor=[0.5 0.5 0.5 1.0]  GraphicAmbientColor=[0.15 0.15 0.15 1.0]  GraphicEmissiveColor=[0.0 0.0 0.0 1.0]  GraphicShininess=75  GraphicOpacity=1  GeometryShape=FromFile  RectangleSize=[1 1]  RectangleSizeUnits=m  BrickDimensions=[1 1 1]  BrickDimensionUnits=m  CylinderRadius=1  CylinderRadiusUnits=m  CylinderLength=1  CylinderLengthUnits=m  SphereRadius=1  SphereRadiusUnits=m  EllipsoidRadii=[1 1 1]  EllipsoidRadiiUnits=m  ExtrusionCrossSection=[1 1; -1 1; -1 -1; 1 -1]  ExtrusionCrossSectionUnits=m  ExtrusionLength=1  ExtrusionLengthUnits=m  PolygonNumSides=3  PolygonOuterRadius=1  PolygonOuterRadiusUnits=m  ExtGeomFileName=15060-M-01052-Entretoise pour axe_AA - DEFAULT_Défaut_sldprt.STL  ExtGeomFileUnits=mm  RevolutionCrossSection=[1 1; 1 -1; 2 -1; 2 1]  RevolutionCrossSectionUnits=m  RevolutionExtent=Full  RevolutionAngle=180  RevolutionAngleUnits=deg  BlockFunction=simmechanics.library.body_elements.solid
  F : PMIOPort  Port=1  Side=Left
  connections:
  Solid/RConn1 -- ReferenceFrame/RConn1 -- F/RConn1

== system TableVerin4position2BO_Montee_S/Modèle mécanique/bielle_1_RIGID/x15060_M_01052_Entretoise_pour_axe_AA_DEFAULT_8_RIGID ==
  ReferenceFrame : sm_lib/Frames and Transforms/Reference Frame  BlockFunction=simmechanics.library.frames_transforms.reference_frame
  Solid : sm_lib/Body Elements/Solid  InertiaType=Custom  Mass=0.00088563500000000007  MassUnits=kg  CenterOfMass=[0.75 0 0]  CenterOfMassUnits=mm  MomentsOfInertia=[0.14350000000000002 0.071916300000000002 0.071916300000000002]  MomentsOfInertiaUnits=kg*mm^2  ProductsOfInertia=[0 0 0]  ProductsOfInertiaUnits=kg*mm^2  DensityBased=on  Density=1000  DensityUnits=kg/(m^3)  GraphicType=FromGeometry  MarkerShape=Sphere  MarkerSize=10  MarkerSizeUnits=m  GraphicVisPropType=SimpleVisualProperties  GraphicDiffuseColor=[0.792157 0.819608 0.933333]  GraphicSpecularColor=[0.5 0.5 0.5 1.0]  GraphicAmbientColor=[0.15 0.15 0.15 1.0]  GraphicEmissiveColor=[0.0 0.0 0.0 1.0]  GraphicShininess=75  GraphicOpacity=1  GeometryShape=FromFile  RectangleSize=[1 1]  RectangleSizeUnits=m  BrickDimensions=[1 1 1]  BrickDimensionUnits=m  CylinderRadius=1  CylinderRadiusUnits=m  CylinderLength=1  CylinderLengthUnits=m  SphereRadius=1  SphereRadiusUnits=m  EllipsoidRadii=[1 1 1]  EllipsoidRadiiUnits=m  ExtrusionCrossSection=[1 1; -1 1; -1 -1; 1 -1]  ExtrusionCrossSectionUnits=m  ExtrusionLength=1  ExtrusionLengthUnits=m  PolygonNumSides=3  PolygonOuterRadius=1  PolygonOuterRadiusUnits=m  ExtGeomFileName=15060-M-01052-Entretoise pour axe_AA - DEFAULT_Défaut_sldprt.STL  ExtGeomFileUnits=mm  RevolutionCrossSection=[1 1; 1 -1; 2 -1; 2 1]  RevolutionCrossSectionUnits=m  RevolutionExtent=Full  RevolutionAngle=180  RevolutionAngleUnits=deg  BlockFunction=simmechanics.library.body_elements.solid
  F : PMIOPort  Port=1  Side=Left
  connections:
  Solid/RConn1 -- ReferenceFrame/RConn1 -- F/RConn1
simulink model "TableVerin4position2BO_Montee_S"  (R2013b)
settings: Solver=ode15s  StartTime=0.0  StopTime=20  RelTol=1e-3
undefined symbols (not defined in the file): deg, kg, m, mm, N, rad, s, X, Y, Z
libraries: sm_lib x907, fl_lib x19, nesl_utility x13, elec_lib x3, sdl_lib x2
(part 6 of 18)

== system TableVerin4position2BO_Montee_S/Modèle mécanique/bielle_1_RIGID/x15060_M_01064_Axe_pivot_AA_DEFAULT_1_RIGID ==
  ReferenceFrame : sm_lib/Frames and Transforms/Reference Frame  BlockFunction=simmechanics.library.frames_transforms.reference_frame
  Solid : sm_lib/Body Elements/Solid  InertiaType=Custom  Mass=0.39573599999999998  MassUnits=kg  CenterOfMass=[-0.15709799999999999 0.0078982500000000008 0]  CenterOfMassUnits=mm  MomentsOfInertia=[12.652900000000001 2161.5900000000001 2161.5800000000004]  MomentsOfInertiaUnits=kg*mm^2  ProductsOfInertia=[0 0 0.38728699999999999]  ProductsOfInertiaUnits=kg*mm^2  DensityBased=on  Density=1000  DensityUnits=kg/(m^3)  GraphicType=FromGeometry  MarkerShape=Sphere  MarkerSize=10  MarkerSizeUnits=m  GraphicVisPropType=SimpleVisualProperties  GraphicDiffuseColor=[0.776471 0.756863 0.737255]  GraphicSpecularColor=[0.5 0.5 0.5 1.0]  GraphicAmbientColor=[0.15 0.15 0.15 1.0]  GraphicEmissiveColor=[0.0 0.0 0.0 1.0]  GraphicShininess=75  GraphicOpacity=1  GeometryShape=FromFile  RectangleSize=[1 1]  RectangleSizeUnits=m  BrickDimensions=[1 1 1]  BrickDimensionUnits=m  CylinderRadius=1  CylinderRadiusUnits=m  CylinderLength=1  CylinderLengthUnits=m  SphereRadius=1  SphereRadiusUnits=m  EllipsoidRadii=[1 1 1]  EllipsoidRadiiUnits=m  ExtrusionCrossSection=[1 1; -1 1; -1 -1; 1 -1]  ExtrusionCrossSectionUnits=m  ExtrusionLength=1  ExtrusionLengthUnits=m  PolygonNumSides=3  PolygonOuterRadius=1  PolygonOuterRadiusUnits=m  ExtGeomFileName=15060-M-01064-Axe pivot_AA - DEFAULT_Défaut_sldprt.STL  ExtGeomFileUnits=mm  RevolutionCrossSection=[1 1; 1 -1; 2 -1; 2 1]  RevolutionCrossSectionUnits=m  RevolutionExtent=Full  RevolutionAngle=180  RevolutionAngleUnits=deg  BlockFunction=simmechanics.library.body_elements.solid
  F : PMIOPort  Port=1  Side=Left
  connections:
  Solid/RConn1 -- ReferenceFrame/RConn1 -- F/RConn1

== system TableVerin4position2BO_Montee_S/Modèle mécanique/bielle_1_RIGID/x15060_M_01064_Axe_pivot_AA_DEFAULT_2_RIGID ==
  ReferenceFrame : sm_lib/Frames and Transforms/Reference Frame  BlockFunction=simmechanics.library.frames_transforms.reference_frame
  Solid : sm_lib/Body Elements/Solid  InertiaType=Custom  Mass=0.39573599999999998  MassUnits=kg  CenterOfMass=[-0.15709799999999999 0.0078982500000000008 0]  CenterOfMassUnits=mm  MomentsOfInertia=[12.652900000000001 2161.5900000000001 2161.5800000000004]  MomentsOfInertiaUnits=kg*mm^2  ProductsOfInertia=[0 0 0.38728699999999999]  ProductsOfInertiaUnits=kg*mm^2  DensityBased=on  Density=1000  DensityUnits=kg/(m^3)  GraphicType=FromGeometry  MarkerShape=Sphere  MarkerSize=10  MarkerSizeUnits=m  GraphicVisPropType=SimpleVisualProperties  GraphicDiffuseColor=[0.776471 0.756863 0.737255]  GraphicSpecularColor=[0.5 0.5 0.5 1.0]  GraphicAmbientColor=[0.15 0.15 0.15 1.0]  GraphicEmissiveColor=[0.0 0.0 0.0 1.0]  GraphicShininess=75  GraphicOpacity=1  GeometryShape=FromFile  RectangleSize=[1 1]  RectangleSizeUnits=m  BrickDimensions=[1 1 1]  BrickDimensionUnits=m  CylinderRadius=1  CylinderRadiusUnits=m  CylinderLength=1  CylinderLengthUnits=m  SphereRadius=1  SphereRadiusUnits=m  EllipsoidRadii=[1 1 1]  EllipsoidRadiiUnits=m  ExtrusionCrossSection=[1 1; -1 1; -1 -1; 1 -1]  ExtrusionCrossSectionUnits=m  ExtrusionLength=1  ExtrusionLengthUnits=m  PolygonNumSides=3  PolygonOuterRadius=1  PolygonOuterRadiusUnits=m  ExtGeomFileName=15060-M-01064-Axe pivot_AA - DEFAULT_Défaut_sldprt.STL  ExtGeomFileUnits=mm  RevolutionCrossSection=[1 1; 1 -1; 2 -1; 2 1]  RevolutionCrossSectionUnits=m  RevolutionExtent=Full  RevolutionAngle=180  RevolutionAngleUnits=deg  BlockFunction=simmechanics.library.body_elements.solid
  F : PMIOPort  Port=1  Side=Left
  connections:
  Solid/RConn1 -- ReferenceFrame/RConn1 -- F/RConn1

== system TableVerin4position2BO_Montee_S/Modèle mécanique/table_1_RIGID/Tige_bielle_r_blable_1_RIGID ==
  ReferenceFrame : sm_lib/Frames and Transforms/Reference Frame  BlockFunction=simmechanics.library.frames_transforms.reference_frame
  Transform : sm_lib/Frames and Transforms/Rigid Transform  TranslationMethod=None  TranslationLengthUnit=m  TranslationStandardAxis=+Z  TranslationStandardOffset=0  TranslationCartesianOffset=[0 0 0]  TranslationROffset=0  TranslationROffsetUnits=m  TranslationZOffset=0  TranslationZOffsetUnits=m  TranslationThetaOffset=0  TranslationThetaOffsetUnits=deg  RotationMethod=None  RotationAngleUnits=deg  RotationStandardAxis=+Z  RotationAngle=0  RotationArbitraryAxis=[0 0 1]  FollAlignAxisA=+X  BaseAlignAxisA=+Y  FollAlignAxisB=+Y  BaseAlignAxisB=+Z  BlockFunction=simmechanics.library.frames_transforms.rigid_transform
  Transform1 : sm_lib/Frames and Transforms/Rigid Transform  TranslationMethod=Cartesian  TranslationLengthUnit=mm  TranslationStandardAxis=+Z  TranslationStandardOffset=0  TranslationCartesianOffset=[73 0 -25.613299999999999]  TranslationROffset=0  TranslationROffsetUnits=m  TranslationZOffset=0  TranslationZOffsetUnits=m  TranslationThetaOffset=0  TranslationThetaOffsetUnits=deg  RotationMethod=ArbitraryAxis  RotationAngleUnits=rad  RotationStandardAxis=+Z  RotationAngle=1.5716345006458177  RotationArbitraryAxis=[-0.028939105132906089 -0.99916217722060174 -0.028939105132906089]  FollAlignAxisA=+X  BaseAlignAxisA=+Y  FollAlignAxisB=+Y  BaseAlignAxisB=+Z  BlockFunction=simmechanics.library.frames_transforms.rigid_transform
  Transform2 : sm_lib/Frames and Transforms/Rigid Transform  TranslationMethod=Cartesian  TranslationLengthUnit=mm  TranslationStandardAxis=+Z  TranslationStandardOffset=0  TranslationCartesianOffset=[-2009.1100000000001 -371.69799999999998 621.09899999999993]  TranslationROffset=0  TranslationROffsetUnits=m  TranslationZOffset=0  TranslationZOffsetUnits=m  TranslationThetaOffset=0  TranslationThetaOffsetUnits=deg  RotationMethod=ArbitraryAxis  RotationAngleUnits=rad  RotationStandardAxis=+Z  RotationAngle=1.3391162766902314  RotationArbitraryAxis=[6.0679741328823503e-17 1 7.0725647859510403e-17]  FollAlignAxisA=+X  BaseAlignAxisA=+Y  FollAlignAxisB=+Y  BaseAlignAxisB=+Z  BlockFunction=simmechanics.library.frames_transforms.rigid_transform
  x15060_Goupille_Beta_3_Acier_Zingu_AA_DEFAULT_1_RIGID : Subsystem
  x15060_M_01031_Barre_de_retenue_AA_DEFAULT_1_RIGID : Subsystem
  F : PMIOPort  Port=1  Side=Right
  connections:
  Transform/RConn1 -- x15060_M_01031_Barre_de_retenue_AA_DEFAULT_1_RIGID/LConn1
  Transform1/RConn1 -- x15060_Goupille_Beta_3_Acier_Zingu_AA_DEFAULT_1_RIGID/LConn1
  Transform/LConn1 -- ReferenceFrame/RConn1 -- Transform1/LConn1 -- Transform2/RConn1
  Transform2/LConn1 -- F/RConn1

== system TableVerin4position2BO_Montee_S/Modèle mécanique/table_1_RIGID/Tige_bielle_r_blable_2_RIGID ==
  ReferenceFrame : sm_lib/Frames and Transforms/Reference Frame  BlockFunction=simmechanics.library.frames_transforms.reference_frame
  Transform : sm_lib/Frames and Transforms/Rigid Transform  TranslationMethod=None  TranslationLengthUnit=m  TranslationStandardAxis=+Z  TranslationStandardOffset=0  TranslationCartesianOffset=[0 0 0]  TranslationROffset=0  TranslationROffsetUnits=m  TranslationZOffset=0  TranslationZOffsetUnits=m  TranslationThetaOffset=0  TranslationThetaOffsetUnits=deg  RotationMethod=None  RotationAngleUnits=deg  RotationStandardAxis=+Z  RotationAngle=0  RotationArbitraryAxis=[0 0 1]  FollAlignAxisA=+X  BaseAlignAxisA=+Y  FollAlignAxisB=+Y  BaseAlignAxisB=+Z  BlockFunction=simmechanics.library.frames_transforms.rigid_transform
  Transform1 : sm_lib/Frames and Transforms/Rigid Transform  TranslationMethod=Cartesian  TranslationLengthUnit=mm  TranslationStandardAxis=+Z  TranslationStandardOffset=0  TranslationCartesianOffset=[73 0 -25.613299999999999]  TranslationROffset=0  TranslationROffsetUnits=m  TranslationZOffset=0  TranslationZOffsetUnits=m  TranslationThetaOffset=0  TranslationThetaOffsetUnits=deg  RotationMethod=ArbitraryAxis  RotationAngleUnits=rad  RotationStandardAxis=+Z  RotationAngle=1.5716345006458177  RotationArbitraryAxis=[-0.028939105132906089 -0.99916217722060174 -0.028939105132906089]  FollAlignAxisA=+X  BaseAlignAxisA=+Y  FollAlignAxisB=+Y  BaseAlignAxisB=+Z  BlockFunction=simmechanics.library.frames_transforms.rigid_transform
  Transform2 : sm_lib/Frames and Transforms/Rigid Transform  TranslationMethod=Cartesian  TranslationLengthUnit=mm  TranslationStandardAxis=+Z  TranslationStandardOffset=0  TranslationCartesianOffset=[-2009.1100000000001 391.30199999999996 621.09899999999993]  TranslationROffset=0  TranslationROffsetUnits=m  TranslationZOffset=0  TranslationZOffsetUnits=m  TranslationThetaOffset=0  TranslationThetaOffsetUnits=deg  RotationMethod=ArbitraryAxis  RotationAngleUnits=rad  RotationStandardAxis=+Z  RotationAngle=1.3391162766902314  RotationArbitraryAxis=[0 1 0]  FollAlignAxisA=+X  BaseAlignAxisA=+Y  FollAlignAxisB=+Y  BaseAlignAxisB=+Z  BlockFunction=simmechanics.library.frames_transforms.rigid_transform
  x15060_Goupille_Beta_3_Acier_Zingu_AA_DEFAULT_1_RIGID : Subsystem
  x15060_M_01031_Barre_de_retenue_AA_DEFAULT_1_RIGID : Subsystem
  F : PMIOPort  Port=1  Side=Right
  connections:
  Transform/RConn1 -- x15060_M_01031_Barre_de_retenue_AA_DEFAULT_1_RIGID/LConn1
  Transform1/RConn1 -- x15060_Goupille_Beta_3_Acier_Zingu_AA_DEFAULT_1_RIGID/LConn1
  Transform/LConn1 -- ReferenceFrame/RConn1 -- Transform1/LConn1 -- Transform2/RConn1
  Transform2/LConn1 -- F/RConn1

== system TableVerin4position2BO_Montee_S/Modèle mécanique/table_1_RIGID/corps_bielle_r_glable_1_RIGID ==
  ReferenceFrame : sm_lib/Frames and Transforms/Reference Frame  BlockFunction=simmechanics.library.frames_transforms.reference_frame
  Transform : sm_lib/Frames and Transforms/Rigid Transform  TranslationMethod=None  TranslationLengthUnit=m  TranslationStandardAxis=+Z  TranslationStandardOffset=0  TranslationCartesianOffset=[0 0 0]  TranslationROffset=0  TranslationROffsetUnits=m  TranslationZOffset=0  TranslationZOffsetUnits=m  TranslationThetaOffset=0  TranslationThetaOffsetUnits=deg  RotationMethod=None  RotationAngleUnits=deg  RotationStandardAxis=+Z  RotationAngle=0  RotationArbitraryAxis=[0 0 1]  FollAlignAxisA=+X  BaseAlignAxisA=+Y  FollAlignAxisB=+Y  BaseAlignAxisB=+Z  BlockFunction=simmechanics.library.frames_transforms.rigid_transform
  Transform1 : sm_lib/Frames and Transforms/Rigid Transform  TranslationMethod=Cartesian  TranslationLengthUnit=mm  TranslationStandardAxis=+Z  TranslationStandardOffset=0  TranslationCartesianOffset=[22 0 0]  TranslationROffset=0  TranslationROffsetUnits=m  TranslationZOffset=0  TranslationZOffsetUnits=m  TranslationThetaOffset=0  TranslationThetaOffsetUnits=deg  RotationMethod=ArbitraryAxis  RotationAngleUnits=rad  RotationStandardAxis=+Z  RotationAngle=2.0943951023931957  RotationArbitraryAxis=[0.57735026918962573 -0.57735026918962584 -0.57735026918962573]  FollAlignAxisA=+X  BaseAlignAxisA=+Y  FollAlignAxisB=+Y  BaseAlignAxisB=+Z  BlockFunction=simmechanics.library.frames_transforms.rigid_transform
  Transform2 : sm_lib/Frames and Transforms/Rigid Transform  TranslationMethod=Cartesian  TranslationLengthUnit=mm  TranslationStandardAxis=+Z  TranslationStandardOffset=0  TranslationCartesianOffset=[0 0 73.5]  TranslationROffset=0  TranslationROffsetUnits=m  TranslationZOffset=0  TranslationZOffsetUnits=m  TranslationThetaOffset=0  TranslationThetaOffsetUnits=deg  RotationMethod=ArbitraryAxis  RotationAngleUnits=rad  RotationStandardAxis=+Z  RotationAngle=1.5707963267948966  RotationArbitraryAxis=[0 0 -1]  FollAlignAxisA=+X  BaseAlignAxisA=+Y  FollAlignAxisB=+Y  BaseAlignAxisB=+Z  BlockFunction=simmechanics.library.frames_transforms.rigid_transform
  Transform3 : sm_lib/Frames and Transforms/Rigid Transform  TranslationMethod=Cartesian  TranslationLengthUnit=mm  TranslationStandardAxis=+Z  TranslationStandardOffset=0  TranslationCartesianOffset=[22 0 -12.5]  TranslationROffset=0  TranslationROffsetUnits=m  TranslationZOffset=0  TranslationZOffsetUnits=m  TranslationThetaOffset=0  TranslationThetaOffsetUnits=deg  RotationMethod=None  RotationAngleUnits=deg  RotationStandardAxis=+Z  RotationAngle=0  RotationArbitraryAxis=[0 0 1]  FollAlignAxisA=+X  BaseAlignAxisA=+Y  FollAlignAxisB=+Y  BaseAlignAxisB=+Z  BlockFunction=simmechanics.library.frames_transforms.rigid_transform
  Transform4 : sm_lib/Frames and Transforms/Rigid Transform  TranslationMethod=Cartesian  TranslationLengthUnit=mm  TranslationStandardAxis=+Z  TranslationStandardOffset=0  TranslationCartesianOffset=[38 0 -12.5]  TranslationROffset=0  TranslationROffsetUnits=m  TranslationZOffset=0  TranslationZOffsetUnits=m  TranslationThetaOffset=0  TranslationThetaOffsetUnits=deg  RotationMethod=ArbitraryAxis  RotationAngleUnits=rad  RotationStandardAxis=+Z  RotationAngle=1.5707963267948968  RotationArbitraryAxis=[-0 -0 -1]  FollAlignAxisA=+X  BaseAlignAxisA=+Y  FollAlignAxisB=+Y  BaseAlignAxisB=+Z  BlockFunction=simmechanics.library.frames_transforms.rigid_transform
  Transform5 : sm_lib/Frames and Transforms/Rigid Transform  TranslationMethod=Cartesian  TranslationLengthUnit=mm  TranslationStandardAxis=+Z  TranslationStandardOffset=0  TranslationCartesianOffset=[16 -16 91.5]  TranslationROffset=0  TranslationROffsetUnits=m  TranslationZOffset=0  TranslationZOffsetUnits=m  TranslationThetaOffset=0  TranslationThetaOffsetUnits=deg  RotationMethod=ArbitraryAxis  RotationAngleUnits=rad  RotationStandardAxis=+Z  RotationAngle=1.8650806328081346  RotationArbitraryAxis=[0.47417217331560524 0.47417217331560535 -0.7418365723704321]  FollAlignAxisA=+X  BaseAlignAxisA=+Y  FollAlignAxisB=+Y  BaseAlignAxisB=+Z  BlockFunction=simmechanics.library.frames_transforms.rigid_transform
  Transform6 : sm_lib/Frames and Transforms/Rigid Transform  TranslationMethod=Cartesian  TranslationLengthUnit=mm  TranslationStandardAxis=+Z  TranslationStandardOffset=0  TranslationCartesianOffset=[14 -16 91.5]  TranslationROffset=0  TranslationROffsetUnits=m  TranslationZOffset=0  TranslationZOffsetUnits=m  TranslationThetaOffset=0  TranslationThetaOffsetUnits=deg  RotationMethod=ArbitraryAxis  RotationAngleUnits=rad  RotationStandardAxis=+Z  RotationAngle=1.5707963267948966  RotationArbitraryAxis=[0 0 -1]  FollAlignAxisA=+X  BaseAlignAxisA=+Y  FollAlignAxisB=+Y  BaseAlignAxisB=+Z  BlockFunction=simmechanics.library.frames_transforms.rigid_transform
  Transform7 : sm_lib/Frames and Transforms/Rigid Transform  TranslationMethod=Cartesian  TranslationLengthUnit=mm  TranslationStandardAxis=+Z  TranslationStandardOffset=0  TranslationCartesianOffset=[-1955.7199999999998 391.30199999999996 394.81100000000004]  TranslationROffset=0  TranslationROffsetUnits=m  TranslationZOffset=0  TranslationZOffsetUnits=m  TranslationThetaOffset=0  TranslationThetaOffsetUnits=deg  RotationMethod=ArbitraryAxis  RotationAngleUnits=rad  RotationStandardAxis=+Z  RotationAngle=3.1415926535897931  RotationArbitraryAxis=[-0.11558112009861291 0 0.99329804423282253]  FollAlignAxisA=+X  BaseAlignAxisA=+Y  FollAlignAxisB=+Y  BaseAlignAxisB=+Z  BlockFunction=simmechanics.library.frames_transforms.rigid_transform
  x15060_M_01054_Barre_glissiere_AA_DEFAULT_1_RIGID : Subsystem
  x15060_M_01055_Glissiere_AA_DEFAULT_1_RIGID : Subsystem
  x15060_M_01056_Couvercle_Glissiere_AA_DEFAULT_1_RIGID : Subsystem
  x15060_M_01078_Rondelle_entretoise_AA_DEFAULT_1_RIGID : Subsystem
  x15060_NLM_Doigt_dindexage_Noir_court_M16_03089_5308_1_RIGID : Subsystem
  x15060_NLM_Manette_indexable_Noire_M10_lgr_30_06460_3101X30_1_R : Subsystem
  x15060_Rondelle_Rondelle_Etroite_Z_10_1_RIGID : Subsystem
  F : PMIOPort  Port=1  Side=Right
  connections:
  Transform/RConn1 -- x15060_M_01055_Glissiere_AA_DEFAULT_1_RIGID/LConn1
  Transform1/RConn1 -- x15060_M_01056_Couvercle_Glissiere_AA_DEFAULT_1_RIGID/LConn1
  Transform2/RConn1 -- x15060_M_01054_Barre_glissiere_AA_DEFAULT_1_RIGID/LConn1
  Transform3/RConn1 -- x15060_M_01078_Rondelle_entretoise_AA_DEFAULT_1_RIGID/LConn1
  Transform4/RConn1 -- x15060_NLM_Doigt_dindexage_Noir_court_M16_03089_5308_1_RIGID/LConn1
  Transform5/RConn1 -- x15060_NLM_Manette_indexable_Noire_M10_lgr_30_06460_3101X30_1_R/LConn1
  Transform6/RConn1 -- x15060_Rondelle_Rondelle_Etroite_Z_10_1_RIGID/LConn1
  Transform/LConn1 -- ReferenceFrame/RConn1 -- Transform1/LConn1 -- Transform2/LConn1 -- Transform3/LConn1 -- Transform4/LConn1 -- Transform5/LConn1 -- Transform6/LConn1 -- Transform7/RConn1
  Transform7/LConn1 -- F/RConn1

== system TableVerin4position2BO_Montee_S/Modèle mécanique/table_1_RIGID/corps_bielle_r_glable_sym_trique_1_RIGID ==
  ReferenceFrame : sm_lib/Frames and Transforms/Reference Frame  BlockFunction=simmechanics.library.frames_transforms.reference_frame
  Transform : sm_lib/Frames and Transforms/Rigid Transform  TranslationMethod=None  TranslationLengthUnit=m  TranslationStandardAxis=+Z  TranslationStandardOffset=0  TranslationCartesianOffset=[0 0 0]  TranslationROffset=0  TranslationROffsetUnits=m  TranslationZOffset=0  TranslationZOffsetUnits=m  TranslationThetaOffset=0  TranslationThetaOffsetUnits=deg  RotationMethod=None  RotationAngleUnits=deg  RotationStandardAxis=+Z  RotationAngle=0  RotationArbitraryAxis=[0 0 1]  FollAlignAxisA=+X  BaseAlignAxisA=+Y  FollAlignAxisB=+Y  BaseAlignAxisB=+Z  BlockFunction=simmechanics.library.frames_transforms.rigid_transform
  Transform1 : sm_lib/Frames and Transforms/Rigid Transform  TranslationMethod=Cartesian  TranslationLengthUnit=mm  TranslationStandardAxis=+Z  TranslationStandardOffset=0  TranslationCartesianOffset=[22 0 0]  TranslationROffset=0  TranslationROffsetUnits=m  TranslationZOffset=0  TranslationZOffsetUnits=m  TranslationThetaOffset=0  TranslationThetaOffsetUnits=deg  RotationMethod=ArbitraryAxis  RotationAngleUnits=rad  RotationStandardAxis=+Z  RotationAngle=2.0943951023931957  RotationArbitraryAxis=[0.57735026918962573 -0.57735026918962584 -0.57735026918962573]  FollAlignAxisA=+X  BaseAlignAxisA=+Y  FollAlignAxisB=+Y  BaseAlignAxisB=+Z  BlockFunction=simmechanics.library.frames_transforms.rigid_transform
  Transform2 : sm_lib/Frames and Transforms/Rigid Transform  TranslationMethod=Cartesian  TranslationLengthUnit=mm  TranslationStandardAxis=+Z  TranslationStandardOffset=0  TranslationCartesianOffset=[0 0 -98.5]  TranslationROffset=0  TranslationROffsetUnits=m  TranslationZOffset=0  TranslationZOffsetUnits=m  TranslationThetaOffset=0  TranslationThetaOffsetUnits=deg  RotationMethod=ArbitraryAxis  RotationAngleUnits=rad  RotationStandardAxis=+Z  RotationAngle=3.1415926535897931  RotationArbitraryAxis=[0.70710678118654746 0.70710678118654757 0]  FollAlignAxisA=+X  BaseAlignAxisA=+Y  FollAlignAxisB=+Y  BaseAlignAxisB=+Z  BlockFunction=simmechanics.library.frames_transforms.rigid_transform
  Transform3 : sm_lib/Frames and Transforms/Rigid Transform  TranslationMethod=Cartesian  TranslationLengthUnit=mm  TranslationStandardAxis=+Z  TranslationStandardOffset=0  TranslationCartesianOffset=[22 0 -12.5]  TranslationROffset=0  TranslationROffsetUnits=m  TranslationZOffset=0  TranslationZOffsetUnits=m  TranslationThetaOffset=0  TranslationThetaOffsetUnits=deg  RotationMethod=None  RotationAngleUnits=deg  RotationStandardAxis=+Z  RotationAngle=0  RotationArbitraryAxis=[0 0 1]  FollAlignAxisA=+X  BaseAlignAxisA=+Y  FollAlignAxisB=+Y  BaseAlignAxisB=+Z  BlockFunction=simmechanics.library.frames_transforms.rigid_transform
  Transform4 : sm_lib/Frames and Transforms/Rigid Transform  TranslationMethod=Cartesian  TranslationLengthUnit=mm  TranslationStandardAxis=+Z  TranslationStandardOffset=0  TranslationCartesianOffset=[38 0 -12.5]  TranslationROffset=0  TranslationROffsetUnits=m  TranslationZOffset=0  TranslationZOffsetUnits=m  TranslationThetaOffset=0  TranslationThetaOffsetUnits=deg  RotationMethod=ArbitraryAxis  RotationAngleUnits=rad  RotationStandardAxis=+Z  RotationAngle=1.5707963267948968  RotationArbitraryAxis=[-0 -0 -1]  FollAlignAxisA=+X  BaseAlignAxisA=+Y  FollAlignAxisB=+Y  BaseAlignAxisB=+Z  BlockFunction=simmechanics.library.frames_transforms.rigid_transform
  Transform5 : sm_lib/Frames and Transforms/Rigid Transform  TranslationMethod=Cartesian  TranslationLengthUnit=mm  TranslationStandardAxis=+Z  TranslationStandardOffset=0  TranslationCartesianOffset=[16 16 -116.5]  TranslationROffset=0  TranslationROffsetUnits=m  TranslationZOffset=0  TranslationZOffsetUnits=m  TranslationThetaOffset=0  TranslationThetaOffsetUnits=deg  RotationMethod=ArbitraryAxis  RotationAngleUnits=rad  RotationStandardAxis=+Z  RotationAngle=1.8548405369738612  RotationArbitraryAxis=[-0.46786377366730747 -0.46786377366730758 -0.74980462693929351]  FollAlignAxisA=+X  BaseAlignAxisA=+Y  FollAlignAxisB=+Y  BaseAlignAxisB=+Z  BlockFunction=simmechanics.library.frames_transforms.rigid_transform
  Transform6 : sm_lib/Frames and Transforms/Rigid Transform  TranslationMethod=Cartesian  TranslationLengthUnit=mm  TranslationStandardAxis=+Z  TranslationStandardOffset=0  TranslationCartesianOffset=[14 16 -116.5]  TranslationROffset=0  TranslationROffsetUnits=m  TranslationZOffset=0  TranslationZOffsetUnits=m  TranslationThetaOffset=0  TranslationThetaOffsetUnits=deg  RotationMethod=ArbitraryAxis  RotationAngleUnits=rad  RotationStandardAxis=+Z  RotationAngle=1.5707963267948966  RotationArbitraryAxis=[0 0 -1]  FollAlignAxisA=+X  BaseAlignAxisA=+Y  FollAlignAxisB=+Y  BaseAlignAxisB=+Z  BlockFunction=simmechanics.library.frames_transforms.rigid_transform
  Transform7 : sm_lib/Frames and Transforms/Rigid Transform  TranslationMethod=Cartesian  TranslationLengthUnit=mm  TranslationStandardAxis=+Z  TranslationStandardOffset=0  TranslationCartesianOffset=[-1963.76 -371.69799999999998 428.87599999999998]  TranslationROffset=0  TranslationROffsetUnits=m  TranslationZOffset=0  TranslationZOffsetUnits=m  TranslationThetaOffset=0  TranslationThetaOffsetUnits=deg  RotationMethod=ArbitraryAxis  RotationAngleUnits=rad  RotationStandardAxis=+Z  RotationAngle=2.909912611977135  RotationArbitraryAxis=[1.9786325522657173e-16 1 3.7677331471122725e-17]  FollAlignAxisA=+X  BaseAlignAxisA=+Y  FollAlignAxisB=+Y  BaseAlignAxisB=+Z  BlockFunction=simmechanics.library.frames_transforms.rigid_transform
  x15060_M_01054_Barre_glissiere_AA_DEFAULT_1_RIGID : Subsystem
  x15060_M_01055_Glissiere_AA_DEFAULT_1_RIGID : Subsystem
  x15060_M_01056_Couvercle_Glissiere_AA_DEFAULT_1_RIGID : Subsystem
  x15060_M_01078_Rondelle_entretoise_AA_DEFAULT_1_RIGID : Subsystem
  x15060_NLM_Doigt_dindexage_Noir_court_M16_03089_5308_1_RIGID : Subsystem
  x15060_NLM_Manette_indexable_Noire_M10_lgr_30_06460_3101X30_1_R : Subsystem
  x15060_Rondelle_Rondelle_Etroite_Z_10_1_RIGID : Subsystem
  F : PMIOPort  Port=1  Side=Right
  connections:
  Transform/RConn1 -- x15060_M_01055_Glissiere_AA_DEFAULT_1_RIGID/LConn1
  Transform1/RConn1 -- x15060_M_01056_Couvercle_Glissiere_AA_DEFAULT_1_RIGID/LConn1
  Transform2/RConn1 -- x15060_M_01054_Barre_glissiere_AA_DEFAULT_1_RIGID/LConn1
  Transform3/RConn1 -- x15060_M_01078_Rondelle_entretoise_AA_DEFAULT_1_RIGID/LConn1
  Transform4/RConn1 -- x15060_NLM_Doigt_dindexage_Noir_court_M16_03089_5308_1_RIGID/LConn1
  Transform5/RConn1 -- x15060_NLM_Manette_indexable_Noire_M10_lgr_30_06460_3101X30_1_R/LConn1
  Transform6/RConn1 -- x15060_Rondelle_Rondelle_Etroite_Z_10_1_RIGID/LConn1
  Transform/LConn1 -- ReferenceFrame/RConn1 -- Transform1/LConn1 -- Transform2/LConn1 -- Transform3/LConn1 -- Transform4/LConn1 -- Transform5/LConn1 -- Transform6/LConn1 -- Transform7/RConn1
  Transform7/LConn1 -- F/RConn1

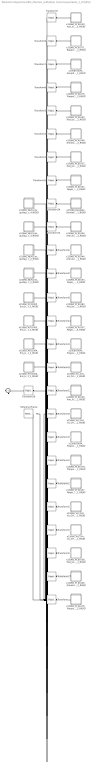
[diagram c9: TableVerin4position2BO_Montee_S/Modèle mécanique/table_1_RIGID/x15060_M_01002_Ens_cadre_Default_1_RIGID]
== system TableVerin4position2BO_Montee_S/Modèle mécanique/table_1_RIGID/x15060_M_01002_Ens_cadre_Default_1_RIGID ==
  ReferenceFrame : sm_lib/Frames and Transforms/Reference Frame  BlockFunction=simmechanics.library.frames_transforms.reference_frame
  Transform : sm_lib/Frames and Transforms/Rigid Transform  TranslationMethod=Cartesian  TranslationLengthUnit=mm  TranslationStandardAxis=+Z  TranslationStandardOffset=0  TranslationCartesianOffset=[-62 -30 352.5]  TranslationROffset=0  TranslationROffsetUnits=m  TranslationZOffset=0  TranslationZOffsetUnits=m  TranslationThetaOffset=0  TranslationThetaOffsetUnits=deg  RotationMethod=None  RotationAngleUnits=deg  RotationStandardAxis=+Z  RotationAngle=0  RotationArbitraryAxis=[0 0 1]  FollAlignAxisA=+X  BaseAlignAxisA=+Y  FollAlignAxisB=+Y  BaseAlignAxisB=+Z  BlockFunction=simmechanics.library.frames_transforms.rigid_transform
  Transform1 : sm_lib/Frames and Transforms/Rigid Transform  TranslationMethod=Cartesian  TranslationLengthUnit=mm  TranslationStandardAxis=+Z  TranslationStandardOffset=0  TranslationCartesianOffset=[367.5 -42 320.5]  TranslationROffset=0  TranslationROffsetUnits=m  TranslationZOffset=0  TranslationZOffsetUnits=m  TranslationThetaOffset=0  TranslationThetaOffsetUnits=deg  RotationMethod=ArbitraryAxis  RotationAngleUnits=rad  RotationStandardAxis=+Z  RotationAngle=1.8031651019763151  RotationArbitraryAxis=[-0.4326419638709077 0.79097526016674402 0.43264196387090759]  FollAlignAxisA=+X  BaseAlignAxisA=+Y  FollAlignAxisB=+Y  BaseAlignAxisB=+Z  BlockFunction=simmechanics.library.frames_transforms.rigid_transform
  Transform10 : sm_lib/Frames and Transforms/Rigid Transform  TranslationMethod=Cartesian  TranslationLengthUnit=mm  TranslationStandardAxis=+Z  TranslationStandardOffset=0  TranslationCartesianOffset=[1.0480500000000001e-10 1.5876200000000001e-11 346.5]  TranslationROffset=0  TranslationROffsetUnits=m  TranslationZOffset=0  TranslationZOffsetUnits=m  TranslationThetaOffset=0  TranslationThetaOffsetUnits=deg  RotationMethod=ArbitraryAxis  RotationAngleUnits=rad  RotationStandardAxis=+Z  RotationAngle=1.5707963267948968  RotationArbitraryAxis=[0 1 0]  FollAlignAxisA=+X  BaseAlignAxisA=+Y  FollAlignAxisB=+Y  BaseAlignAxisB=+Z  BlockFunction=simmechanics.library.frames_transforms.rigid_transform
  Transform11 : sm_lib/Frames and Transforms/Rigid Transform  TranslationMethod=Cartesian  TranslationLengthUnit=mm  TranslationStandardAxis=+Z  TranslationStandardOffset=0  TranslationCartesianOffset=[310.09999999999997 -26.599999999999998 359.5]  TranslationROffset=0  TranslationROffsetUnits=m  TranslationZOffset=0  TranslationZOffsetUnits=m  TranslationThetaOffset=0  TranslationThetaOffsetUnits=deg  RotationMethod=ArbitraryAxis  RotationAngleUnits=rad  RotationStandardAxis=+Z  RotationAngle=3.1415926535897931  RotationArbitraryAxis=[0.71158314396818567 -0.70260189952799912 0]  FollAlignAxisA=+X  BaseAlignAxisA=+Y  FollAlignAxisB=+Y  BaseAlignAxisB=+Z  BlockFunction=simmechanics.library.frames_transforms.rigid_transform
  Transform12 : sm_lib/Frames and Transforms/Rigid Transform  TranslationMethod=Cartesian  TranslationLengthUnit=mm  TranslationStandardAxis=+Z  TranslationStandardOffset=0  TranslationCartesianOffset=[90.5 -23 398]  TranslationROffset=0  TranslationROffsetUnits=m  TranslationZOffset=0  TranslationZOffsetUnits=m  TranslationThetaOffset=0  TranslationThetaOffsetUnits=deg  RotationMethod=ArbitraryAxis  RotationAngleUnits=rad  RotationStandardAxis=+Z  RotationAngle=3.1415926535897931  RotationArbitraryAxis=[0.96150000341592001 0.2748049188627924 0]  FollAlignAxisA=+X  BaseAlignAxisA=+Y  FollAlignAxisB=+Y  BaseAlignAxisB=+Z  BlockFunction=simmechanics.library.frames_transforms.rigid_transform
  Transform13 : sm_lib/Frames and Transforms/Rigid Transform  TranslationMethod=Cartesian  TranslationLengthUnit=mm  TranslationStandardAxis=+Z  TranslationStandardOffset=0  TranslationCartesianOffset=[-346.5 -40 -165]  TranslationROffset=0  TranslationROffsetUnits=m  TranslationZOffset=0  TranslationZOffsetUnits=m  TranslationThetaOffset=0  TranslationThetaOffsetUnits=deg  RotationMethod=ArbitraryAxis  RotationAngleUnits=rad  RotationStandardAxis=+Z  RotationAngle=1.5707963267948968  RotationArbitraryAxis=[1 0 0]  FollAlignAxisA=+X  BaseAlignAxisA=+Y  FollAlignAxisB=+Y  BaseAlignAxisB=+Z  BlockFunction=simmechanics.library.frames_transforms.rigid_transform
  Transform14 : sm_lib/Frames and Transforms/Rigid Transform  TranslationMethod=Cartesian  TranslationLengthUnit=mm  TranslationStandardAxis=+Z  TranslationStandardOffset=0  TranslationCartesianOffset=[-62 -30 -357.5]  TranslationROffset=0  TranslationROffsetUnits=m  TranslationZOffset=0  TranslationZOffsetUnits=m  TranslationThetaOffset=0  TranslationThetaOffsetUnits=deg  RotationMethod=None  RotationAngleUnits=deg  RotationStandardAxis=+Z  RotationAngle=0  RotationArbitraryAxis=[0 0 1]  FollAlignAxisA=+X  BaseAlignAxisA=+Y  FollAlignAxisB=+Y  BaseAlignAxisB=+Z  BlockFunction=simmechanics.library.frames_transforms.rigid_transform
  Transform15 : sm_lib/Frames and Transforms/Rigid Transform  TranslationMethod=Cartesian  TranslationLengthUnit=mm  TranslationStandardAxis=+Z  TranslationStandardOffset=0  TranslationCartesianOffset=[-250.5 1.5765200000000002e-11 -352.5]  TranslationROffset=0  TranslationROffsetUnits=m  TranslationZOffset=0  TranslationZOffsetUnits=m  TranslationThetaOffset=0  TranslationThetaOffsetUnits=deg  RotationMethod=ArbitraryAxis  RotationAngleUnits=rad  RotationStandardAxis=+Z  RotationAngle=2.0943951023931962  RotationArbitraryAxis=[-0.57735026918962606 -0.57735026918962595 0.5773502691896254]  FollAlignAxisA=+X  BaseAlignAxisA=+Y  FollAlignAxisB=+Y  BaseAlignAxisB=+Z  BlockFunction=simmechanics.library.frames_transforms.rigid_transform
  Transform16 : sm_lib/Frames and Transforms/Rigid Transform  TranslationMethod=Cartesian  TranslationLengthUnit=mm  TranslationStandardAxis=+Z  TranslationStandardOffset=0  TranslationCartesianOffset=[358.5 32.5 346.5]  TranslationROffset=0  TranslationROffsetUnits=m  TranslationZOffset=0  TranslationZOffsetUnits=m  TranslationThetaOffset=0  TranslationThetaOffsetUnits=deg  RotationMethod=ArbitraryAxis  RotationAngleUnits=rad  RotationStandardAxis=+Z  RotationAngle=2.7044242386120039  RotationArbitraryAxis=[-0.68944064161854934 -0.22213330090044031 0.68944064161875263]  FollAlignAxisA=+X  BaseAlignAxisA=+Y  FollAlignAxisB=+Y  BaseAlignAxisB=+Z  BlockFunction=simmechanics.library.frames_transforms.rigid_transform
  Transform17 : sm_lib/Frames and Transforms/Rigid Transform  TranslationMethod=Cartesian  TranslationLengthUnit=mm  TranslationStandardAxis=+Z  TranslationStandardOffset=0  TranslationCartesianOffset=[90.5 -23 -352.5]  TranslationROffset=0  TranslationROffsetUnits=m  TranslationZOffset=0  TranslationZOffsetUnits=m  TranslationThetaOffset=0  TranslationThetaOffsetUnits=deg  RotationMethod=ArbitraryAxis  RotationAngleUnits=rad  RotationStandardAxis=+Z  RotationAngle=2.0943951023931957  RotationArbitraryAxis=[0.57735026918962584 0.57735026918962573 -0.57735026918962573]  FollAlignAxisA=+X  BaseAlignAxisA=+Y  FollAlignAxisB=+Y  BaseAlignAxisB=+Z  BlockFunction=simmechanics.library.frames_transforms.rigid_transform
  Transform18 : sm_lib/Frames and Transforms/Rigid Transform  TranslationMethod=Cartesian  TranslationLengthUnit=mm  TranslationStandardAxis=+Z  TranslationStandardOffset=0  TranslationCartesianOffset=[368.5 25 330.5]  TranslationROffset=0  TranslationROffsetUnits=m  TranslationZOffset=0  TranslationZOffsetUnits=m  TranslationThetaOffset=0  TranslationThetaOffsetUnits=deg  RotationMethod=ArbitraryAxis  RotationAngleUnits=rad  RotationStandardAxis=+Z  RotationAngle=2.8130451254913762  RotationArbitraryAxis=[-0.69732385197991364 -0.16576758102711101 0.69732385198006508]  FollAlignAxisA=+X  BaseAlignAxisA=+Y  FollAlignAxisB=+Y  BaseAlignAxisB=+Z  BlockFunction=simmechanics.library.frames_transforms.rigid_transform
  Transform19 : sm_lib/Frames and Transforms/Rigid Transform  TranslationMethod=Cartesian  TranslationLengthUnit=mm  TranslationStandardAxis=+Z  TranslationStandardOffset=0  TranslationCartesianOffset=[-250.5 1.59872e-11 352.5]  TranslationROffset=0  TranslationROffsetUnits=m  TranslationZOffset=0  TranslationZOffsetUnits=m  TranslationThetaOffset=0  TranslationThetaOffsetUnits=deg  RotationMethod=ArbitraryAxis  RotationAngleUnits=rad  RotationStandardAxis=+Z  RotationAngle=2.0943951023931953  RotationArbitraryAxis=[0.57735026918962584 -0.57735026918962584 -0.57735026918962584]  FollAlignAxisA=+X  BaseAlignAxisA=+Y  FollAlignAxisB=+Y  BaseAlignAxisB=+Z  BlockFunction=simmechanics.library.frames_transforms.rigid_transform
  Transform2 : sm_lib/Frames and Transforms/Rigid Transform  TranslationMethod=Cartesian  TranslationLengthUnit=mm  TranslationStandardAxis=+Z  TranslationStandardOffset=0  TranslationCartesianOffset=[165 -40 346.5]  TranslationROffset=0  TranslationROffsetUnits=m  TranslationZOffset=0  TranslationZOffsetUnits=m  TranslationThetaOffset=0  TranslationThetaOffsetUnits=deg  RotationMethod=ArbitraryAxis  RotationAngleUnits=rad  RotationStandardAxis=+Z  RotationAngle=2.0943951023931953  RotationArbitraryAxis=[0.57735026918962584 -0.57735026918962584 0.57735026918962584]  FollAlignAxisA=+X  BaseAlignAxisA=+Y  FollAlignAxisB=+Y  BaseAlignAxisB=+Z  BlockFunction=simmechanics.library.frames_transforms.rigid_transform
  Transform20 : sm_lib/Frames and Transforms/Rigid Transform  TranslationMethod=Cartesian  TranslationLengthUnit=mm  TranslationStandardAxis=+Z  TranslationStandardOffset=0  TranslationCartesianOffset=[1.0480500000000001e-10 1.58207e-11 -346.5]  TranslationROffset=0  TranslationROffsetUnits=m  TranslationZOffset=0  TranslationZOffsetUnits=m  TranslationThetaOffset=0  TranslationThetaOffsetUnits=deg  RotationMethod=ArbitraryAxis  RotationAngleUnits=rad  RotationStandardAxis=+Z  RotationAngle=1.5707963267948968  RotationArbitraryAxis=[5.7237000000000004e-17 1 5.7237000000000004e-17]  FollAlignAxisA=+X  BaseAlignAxisA=+Y  FollAlignAxisB=+Y  BaseAlignAxisB=+Z  BlockFunction=simmechanics.library.frames_transforms.rigid_transform
  Transform21 : sm_lib/Frames and Transforms/Rigid Transform  TranslationMethod=Cartesian  TranslationLengthUnit=mm  TranslationStandardAxis=+Z  TranslationStandardOffset=0  TranslationCartesianOffset=[-346.5 -40 165]  TranslationROffset=0  TranslationROffsetUnits=m  TranslationZOffset=0  TranslationZOffsetUnits=m  TranslationThetaOffset=0  TranslationThetaOffsetUnits=deg  RotationMethod=ArbitraryAxis  RotationAngleUnits=rad  RotationStandardAxis=+Z  RotationAngle=3.1415926535897931  RotationArbitraryAxis=[0 -0.70710678118654746 0.70710678118654757]  FollAlignAxisA=+X  BaseAlignAxisA=+Y  FollAlignAxisB=+Y  BaseAlignAxisB=+Z  BlockFunction=simmechanics.library.frames_transforms.rigid_transform
  Transform22 : sm_lib/Frames and Transforms/Rigid Transform  TranslationMethod=Cartesian  TranslationLengthUnit=mm  TranslationStandardAxis=+Z  TranslationStandardOffset=0  TranslationCartesianOffset=[367.5 -42 330.5]  TranslationROffset=0  TranslationROffsetUnits=m  TranslationZOffset=0  TranslationZOffsetUnits=m  TranslationThetaOffset=0  TranslationThetaOffsetUnits=deg  RotationMethod=ArbitraryAxis  RotationAngleUnits=rad  RotationStandardAxis=+Z  RotationAngle=1.5707963267948961  RotationArbitraryAxis=[-4.4840000000000079e-18 -1.2244500000000001e-16 1]  FollAlignAxisA=+X  BaseAlignAxisA=+Y  FollAlignAxisB=+Y  BaseAlignAxisB=+Z  BlockFunction=simmechanics.library.frames_transforms.rigid_transform
  Transform23 : sm_lib/Frames and Transforms/Rigid Transform  TranslationMethod=Cartesian  TranslationLengthUnit=mm  TranslationStandardAxis=+Z  TranslationStandardOffset=0  TranslationCartesianOffset=[367.5 -42 -330.5]  TranslationROffset=0  TranslationROffsetUnits=m  TranslationZOffset=0  TranslationZOffsetUnits=m  TranslationThetaOffset=0  TranslationThetaOffsetUnits=deg  RotationMethod=ArbitraryAxis  RotationAngleUnits=rad  RotationStandardAxis=+Z  RotationAngle=1.5707963267948974  RotationArbitraryAxis=[0 0 1]  FollAlignAxisA=+X  BaseAlignAxisA=+Y  FollAlignAxisB=+Y  BaseAlignAxisB=+Z  BlockFunction=simmechanics.library.frames_transforms.rigid_transform
  Transform24 : sm_lib/Frames and Transforms/Rigid Transform  TranslationMethod=Cartesian  TranslationLengthUnit=mm  TranslationStandardAxis=+Z  TranslationStandardOffset=0  TranslationCartesianOffset=[90.5 -23 392]  TranslationROffset=0  TranslationROffsetUnits=m  TranslationZOffset=0  TranslationZOffsetUnits=m  TranslationThetaOffset=0  TranslationThetaOffsetUnits=deg  RotationMethod=ArbitraryAxis  RotationAngleUnits=rad  RotationStandardAxis=+Z  RotationAngle=2.426234766327469  RotationArbitraryAxis=[0.3737552584014866 -0.65586088723800184 -0.65586088723800195]  FollAlignAxisA=+X  BaseAlignAxisA=+Y  FollAlignAxisB=+Y  BaseAlignAxisB=+Z  BlockFunction=simmechanics.library.frames_transforms.rigid_transform
  Transform25 : sm_lib/Frames and Transforms/Rigid Transform  TranslationMethod=Cartesian  TranslationLengthUnit=mm  TranslationStandardAxis=+Z  TranslationStandardOffset=0  TranslationCartesianOffset=[-165 -40 346.5]  TranslationROffset=0  TranslationROffsetUnits=m  TranslationZOffset=0  TranslationZOffsetUnits=m  TranslationThetaOffset=0  TranslationThetaOffsetUnits=deg  RotationMethod=ArbitraryAxis  RotationAngleUnits=rad  RotationStandardAxis=+Z  RotationAngle=2.0943951023931953  RotationArbitraryAxis=[0.57735026918962584 0.57735026918962584 -0.57735026918962584]  FollAlignAxisA=+X  BaseAlignAxisA=+Y  FollAlignAxisB=+Y  BaseAlignAxisB=+Z  BlockFunction=simmechanics.library.frames_transforms.rigid_transform
  Transform26 : sm_lib/Frames and Transforms/Rigid Transform  TranslationMethod=Cartesian  TranslationLengthUnit=mm  TranslationStandardAxis=+Z  TranslationStandardOffset=0  TranslationCartesianOffset=[-2102.48 9.8021700000000003 620.55400000000009]  TranslationROffset=0  TranslationROffsetUnits=m  TranslationZOffset=0  TranslationZOffsetUnits=m  TranslationThetaOffset=0  TranslationThetaOffsetUnits=deg  RotationMethod=ArbitraryAxis  RotationAngleUnits=rad  RotationStandardAxis=+Z  RotationAngle=1.5854912505939065  RotationArbitraryAxis=[-0.98541199847340966 0.1203395057008316 0.1203395057008316]  FollAlignAxisA=+X  BaseAlignAxisA=+Y  FollAlignAxisB=+Y  BaseAlignAxisB=+Z  BlockFunction=simmechanics.library.frames_transforms.rigid_transform
  Transform3 : sm_lib/Frames and Transforms/Rigid Transform  TranslationMethod=Cartesian  TranslationLengthUnit=mm  TranslationStandardAxis=+Z  TranslationStandardOffset=0  TranslationCartesianOffset=[-346.5 1.5931700000000002e-11 2.45364e-11]  TranslationROffset=0  TranslationROffsetUnits=m  TranslationZOffset=0  TranslationZOffsetUnits=m  TranslationThetaOffset=0  TranslationThetaOffsetUnits=deg  RotationMethod=ArbitraryAxis  RotationAngleUnits=rad  RotationStandardAxis=+Z  RotationAngle=3.1415926535897931  RotationArbitraryAxis=[0 1 0]  FollAlignAxisA=+X  BaseAlignAxisA=+Y  FollAlignAxisB=+Y  BaseAlignAxisB=+Z  BlockFunction=simmechanics.library.frames_transforms.rigid_transform
  Transform4 : sm_lib/Frames and Transforms/Rigid Transform  TranslationMethod=Cartesian  TranslationLengthUnit=mm  TranslationStandardAxis=+Z  TranslationStandardOffset=0  TranslationCartesianOffset=[367.5 -42 -315.5]  TranslationROffset=0  TranslationROffsetUnits=m  TranslationZOffset=0  TranslationZOffsetUnits=m  TranslationThetaOffset=0  TranslationThetaOffsetUnits=deg  RotationMethod=ArbitraryAxis  RotationAngleUnits=rad  RotationStandardAxis=+Z  RotationAngle=1.5708079595287647  RotationArbitraryAxis=[0.003410659547515394 0.99998836733379148 -0.0034106595475155393]  FollAlignAxisA=+X  BaseAlignAxisA=+Y  FollAlignAxisB=+Y  BaseAlignAxisB=+Z  BlockFunction=simmechanics.library.frames_transforms.rigid_transform
  Transform5 : sm_lib/Frames and Transforms/Rigid Transform  TranslationMethod=Cartesian  TranslationLengthUnit=mm  TranslationStandardAxis=+Z  TranslationStandardOffset=0  TranslationCartesianOffset=[346.5 1.5931700000000002e-11 2.4757999999999999e-11]  TranslationROffset=0  TranslationROffsetUnits=m  TranslationZOffset=0  TranslationZOffsetUnits=m  TranslationThetaOffset=0  TranslationThetaOffsetUnits=deg  RotationMethod=None  RotationAngleUnits=deg  RotationStandardAxis=+Z  RotationAngle=0  RotationArbitraryAxis=[0 0 1]  FollAlignAxisA=+X  BaseAlignAxisA=+Y  FollAlignAxisB=+Y  BaseAlignAxisB=+Z  BlockFunction=simmechanics.library.frames_transforms.rigid_transform
  Transform6 : sm_lib/Frames and Transforms/Rigid Transform  TranslationMethod=Cartesian  TranslationLengthUnit=mm  TranslationStandardAxis=+Z  TranslationStandardOffset=0  TranslationCartesianOffset=[-352.5 -30 -244]  TranslationROffset=0  TranslationROffsetUnits=m  TranslationZOffset=0  TranslationZOffsetUnits=m  TranslationThetaOffset=0  TranslationThetaOffsetUnits=deg  RotationMethod=ArbitraryAxis  RotationAngleUnits=rad  RotationStandardAxis=+Z  RotationAngle=1.570796326794897  RotationArbitraryAxis=[3.4781199999999986e-16 -1 2.4893299999999984e-16]  FollAlignAxisA=+X  BaseAlignAxisA=+Y  FollAlignAxisB=+Y  BaseAlignAxisB=+Z  BlockFunction=simmechanics.library.frames_transforms.rigid_transform
  Transform7 : sm_lib/Frames and Transforms/Rigid Transform  TranslationMethod=Cartesian  TranslationLengthUnit=mm  TranslationStandardAxis=+Z  TranslationStandardOffset=0  TranslationCartesianOffset=[-336.5 22.5 346.5]  TranslationROffset=0  TranslationROffsetUnits=m  TranslationZOffset=0  TranslationZOffsetUnits=m  TranslationThetaOffset=0  TranslationThetaOffsetUnits=deg  RotationMethod=ArbitraryAxis  RotationAngleUnits=rad  RotationStandardAxis=+Z  RotationAngle=3.1415926535894094  RotationArbitraryAxis=[4.1447007314695815e-13 -0.90746645198529152 -0.42012455120026815]  FollAlignAxisA=+X  BaseAlignAxisA=+Y  FollAlignAxisB=+Y  BaseAlignAxisB=+Z  BlockFunction=simmechanics.library.frames_transforms.rigid_transform
  Transform8 : sm_lib/Frames and Transforms/Rigid Transform  TranslationMethod=Cartesian  TranslationLengthUnit=mm  TranslationStandardAxis=+Z  TranslationStandardOffset=0  TranslationCartesianOffset=[367.5 -42 352.5]  TranslationROffset=0  TranslationROffsetUnits=m  TranslationZOffset=0  TranslationZOffsetUnits=m  TranslationThetaOffset=0  TranslationThetaOffsetUnits=deg  RotationMethod=ArbitraryAxis  RotationAngleUnits=rad  RotationStandardAxis=+Z  RotationAngle=3.1415926535897927  RotationArbitraryAxis=[-6.3464500000000003e-17 -5.9631e-17 1]  FollAlignAxisA=+X  BaseAlignAxisA=+Y  FollAlignAxisB=+Y  BaseAlignAxisB=+Z  BlockFunction=simmechanics.library.frames_transforms.rigid_transform
  Transform9 : sm_lib/Frames and Transforms/Rigid Transform  TranslationMethod=Cartesian  TranslationLengthUnit=mm  TranslationStandardAxis=+Z  TranslationStandardOffset=0  TranslationCartesianOffset=[90.5 -23 352.5]  TranslationROffset=0  TranslationROffsetUnits=m  TranslationZOffset=0  TranslationZOffsetUnits=m  TranslationThetaOffset=0  TranslationThetaOffsetUnits=deg  RotationMethod=ArbitraryAxis  RotationAngleUnits=rad  RotationStandardAxis=+Z  RotationAngle=2.0943951023931953  RotationArbitraryAxis=[0.57735026918962584 -0.57735026918962584 0.57735026918962584]  FollAlignAxisA=+X  BaseAlignAxisA=+Y  FollAlignAxisB=+Y  BaseAlignAxisB=+Z  BlockFunction=simmechanics.library.frames_transforms.rigid_transform
  x15060_M_01004_Ens_barre_de_cadre_1_Default_1_RIGID : Subsystem
  x15060_M_01004_Ens_barre_de_cadre_1_Default_2_RIGID : Subsystem
  x15060_M_01005_Ens_barre_de_cadre_2_Default_1_RIGID : Subsystem
  x15060_M_01005_Ens_barre_de_cadre_2_Default_2_RIGID : Subsystem
  x15060_M_01030_Axe_long_pour_cardan_AA_DEFAULT_1_RIGID : Subsystem
  x15060_M_01030_Axe_long_pour_cardan_AA_DEFAULT_2_RIGID : Subsystem
  x15060_M_01037_Plat_bord_de_cadre_AA_DEFAULT_1_RIGID : Subsystem
  x15060_M_01038_Plat_bord_de_cadre_2_AA_DEFAULT_1_RIGID : Subsystem
  x15060_M_01040_Plat_bord_de_cadre_avt_AA_DEFAULT_1_RIGID : Subsystem
  x15060_M_01044_Articulation_1_AA_DEFAULT_1_RIGID : Subsystem
  x15060_M_01044_Articulation_1_AA_DEFAULT_2_RIGID : Subsystem
  x15060_M_01046_Entretoise_pivot_AA_DEFAULT_1_RIGID : Subsystem
  x15060_M_01046_Entretoise_pivot_AA_DEFAULT_2_RIGID : Subsystem
  x15060_M_01057_Regle_gradu_e_AA_DEFAULT_1_RIGID : Subsystem
  x15060_M_01057_Regle_gradu_e_AA_DEFAULT_2_RIGID : Subsystem
  x15060_M_01057_Regle_gradu_e_AA_DEFAULT_3_RIGID : Subsystem
  x15060_M_01057_Regle_gradu_e_AA_DEFAULT_4_RIGID : Subsystem
  x15060_M_01071_Rapporteur_angulaire_AA_DEFAULT_1_RIGID : Subsystem
  x15060_M_01079_Plaque_a_trous_AA_DEFAULT_1_RIGID : Subsystem
  x15060_M_01079_Plaque_a_trous_AA_DEFAULT_2_RIGID : Subsystem
  x15060_M_01079_Plaque_a_trous_AA_DEFAULT_3_RIGID : Subsystem
  x15060_M_01083_Plat_bord_de_cadre_2_SYM_AA_DEFAULT_1_RIGID : Subsystem
  x15060_NLM_Ens_guidage_Drylin_N_1_Default_1_RIGID : Subsystem
  x15060_NLM_Ens_guidage_Drylin_N_1_Default_2_RIGID : Subsystem
  x15060_NLM_Ens_guidage_Drylin_N_1_Default_3_RIGID : Subsystem
  x15060_NLM_Ens_guidage_Drylin_N_1_Default_4_RIGID : Subsystem
  x15060_NLM_Goupille_cyl_3_Lgr_16_03320_03x16_AA_DEFAULT_1_RIGID : Subsystem
  x15060_NLM_Poignee_de_manut_noir_mat_06904_1120081_1_RIGID : Subsystem
  x15060_NLM_Poignee_de_manut_noir_mat_06904_1120081_2_RIGID : Subsystem
  x15060_Rondelle_Rondelle_TresLarge_LL_5_1_RIGID : Subsystem
  x15060_Vis_CHc_vis_CHc_M_4_X_10_1_RIGID : Subsystem
  x15060_Vis_CHc_vis_CHc_M_5_X_12_1_RIGID : Subsystem
  x15060_Vis_CHc_vis_CHc_M_6_X_16_1_RIGID : Subsystem
  x15060_Vis_CHc_vis_CHc_M_8_X_16_1_RIGID : Subsystem
  F : PMIOPort  Port=1  Side=Right
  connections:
  Transform/RConn1 -- x15060_M_01079_Plaque_a_trous_AA_DEFAULT_2_RIGID/LConn1
  Transform1/RConn1 -- x15060_M_01046_Entretoise_pivot_AA_DEFAULT_1_RIGID/LConn1
  Transform10/RConn1 -- x15060_M_01038_Plat_bord_de_cadre_2_AA_DEFAULT_1_RIGID/LConn1
  Transform11/RConn1 -- x15060_Vis_CHc_vis_CHc_M_4_X_10_1_RIGID/LConn1
  Transform12/RConn1 -- x15060_Vis_CHc_vis_CHc_M_5_X_12_1_RIGID/LConn1
  Transform13/RConn1 -- x15060_M_01057_Regle_gradu_e_AA_DEFAULT_1_RIGID/LConn1
  Transform14/RConn1 -- x15060_M_01079_Plaque_a_trous_AA_DEFAULT_1_RIGID/LConn1
  Transform15/RConn1 -- x15060_NLM_Poignee_de_manut_noir_mat_06904_1120081_1_RIGID/LConn1
  Transform16/RConn1 -- x15060_Vis_CHc_vis_CHc_M_6_X_16_1_RIGID/LConn1
  Transform17/RConn1 -- x15060_M_01030_Axe_long_pour_cardan_AA_DEFAULT_1_RIGID/LConn1
  Transform18/RConn1 -- x15060_Vis_CHc_vis_CHc_M_8_X_16_1_RIGID/LConn1
  Transform19/RConn1 -- x15060_NLM_Poignee_de_manut_noir_mat_06904_1120081_2_RIGID/LConn1
  Transform2/RConn1 -- x15060_M_01057_Regle_gradu_e_AA_DEFAULT_4_RIGID/LConn1
  Transform20/RConn1 -- x15060_M_01083_Plat_bord_de_cadre_2_SYM_AA_DEFAULT_1_RIGID/LConn1
  Transform21/RConn1 -- x15060_M_01057_Regle_gradu_e_AA_DEFAULT_2_RIGID/LConn1
  Transform22/RConn1 -- x15060_M_01044_Articulation_1_AA_DEFAULT_1_RIGID/LConn1
  Transform23/RConn1 -- x15060_M_01044_Articulation_1_AA_DEFAULT_2_RIGID/LConn1
  Transform24/RConn1 -- x15060_Rondelle_Rondelle_TresLarge_LL_5_1_RIGID/LConn1
  Transform25/RConn1 -- x15060_M_01057_Regle_gradu_e_AA_DEFAULT_3_RIGID/LConn1
  Transform/LConn1 -- ReferenceFrame/RConn1 -- Transform1/LConn1 -- Transform10/LConn1 -- Transform11/LConn1 -- Transform12/LConn1 -- Transform13/LConn1 -- Transform14/LConn1 -- Transform15/LConn1 -- Transform16/LConn1 -- Transform17/LConn1 -- Transform18/LConn1 -- Transform19/LConn1 -- Transform2/LConn1 -- Transform20/LConn1 -- Transform21/LConn1 -- Transform22/LConn1 -- Transform23/LConn1 -- Transform24/LConn1 -- Transform25/LConn1 -- Transform26/RConn1 -- Transform3/LConn1 -- Transform4/LConn1 -- Transform5/LConn1 -- Transform6/LConn1 -- Transform7/LConn1 -- Transform8/LConn1 -- Transform9/LConn1 -- x15060_M_01004_Ens_barre_de_cadre_1_Default_1_RIGID/RConn1 -- x15060_M_01004_Ens_barre_de_cadre_1_Default_2_RIGID/RConn1 -- x15060_M_01005_Ens_barre_de_cadre_2_Default_1_RIGID/RConn1 -- x15060_M_01005_Ens_barre_de_cadre_2_Default_2_RIGID/RConn1 -- x15060_NLM_Ens_guidage_Drylin_N_1_Default_1_RIGID/RConn1 -- x15060_NLM_Ens_guidage_Drylin_N_1_Default_2_RIGID/RConn1 -- x15060_NLM_Ens_guidage_Drylin_N_1_Default_3_RIGID/RConn1 -- x15060_NLM_Ens_guidage_Drylin_N_1_Default_4_RIGID/RConn1
  Transform26/LConn1 -- F/RConn1
  Transform3/RConn1 -- x15060_M_01037_Plat_bord_de_cadre_AA_DEFAULT_1_RIGID/LConn1
  Transform4/RConn1 -- x15060_M_01046_Entretoise_pivot_AA_DEFAULT_2_RIGID/LConn1
  Transform5/RConn1 -- x15060_M_01040_Plat_bord_de_cadre_avt_AA_DEFAULT_1_RIGID/LConn1
  Transform6/RConn1 -- x15060_M_01079_Plaque_a_trous_AA_DEFAULT_3_RIGID/LConn1
  Transform7/RConn1 -- x15060_NLM_Goupille_cyl_3_Lgr_16_03320_03x16_AA_DEFAULT_1_RIGID/LConn1
  Transform8/RConn1 -- x15060_M_01071_Rapporteur_angulaire_AA_DEFAULT_1_RIGID/LConn1
  Transform9/RConn1 -- x15060_M_01030_Axe_long_pour_cardan_AA_DEFAULT_2_RIGID/LConn1
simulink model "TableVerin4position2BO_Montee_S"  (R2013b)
settings: Solver=ode15s  StartTime=0.0  StopTime=20  RelTol=1e-3
undefined symbols (not defined in the file): deg, kg, m, mm, N, rad, s, X, Y, Z
libraries: sm_lib x907, fl_lib x19, nesl_utility x13, elec_lib x3, sdl_lib x2
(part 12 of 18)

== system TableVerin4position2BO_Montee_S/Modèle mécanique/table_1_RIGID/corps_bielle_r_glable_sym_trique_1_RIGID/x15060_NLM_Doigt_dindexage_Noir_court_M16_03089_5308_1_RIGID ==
  ReferenceFrame : sm_lib/Frames and Transforms/Reference Frame  BlockFunction=simmechanics.library.frames_transforms.reference_frame
  Solid : sm_lib/Body Elements/Solid  InertiaType=Custom  Mass=0.0152865  MassUnits=kg  CenterOfMass=[7.6408400000000005e-10 4.4630900000000002 2.0258599999999999e-09]  CenterOfMassUnits=mm  MomentsOfInertia=[3.4819200000000001 1.0587900000000001 3.4819300000000002]  MomentsOfInertiaUnits=kg*mm^2  ProductsOfInertia=[0 3.9585199999999998e-08 0]  ProductsOfInertiaUnits=kg*mm^2  DensityBased=on  Density=1000  DensityUnits=kg/(m^3)  GraphicType=FromGeometry  MarkerShape=Sphere  MarkerSize=10  MarkerSizeUnits=m  GraphicVisPropType=SimpleVisualProperties  GraphicDiffuseColor=[0.792157 0.819608 0.933333]  GraphicSpecularColor=[0.5 0.5 0.5 1.0]  GraphicAmbientColor=[0.15 0.15 0.15 1.0]  GraphicEmissiveColor=[0.0 0.0 0.0 1.0]  GraphicShininess=75  GraphicOpacity=1  GeometryShape=FromFile  RectangleSize=[1 1]  RectangleSizeUnits=m  BrickDimensions=[1 1 1]  BrickDimensionUnits=m  CylinderRadius=1  CylinderRadiusUnits=m  CylinderLength=1  CylinderLengthUnits=m  SphereRadius=1  SphereRadiusUnits=m  EllipsoidRadii=[1 1 1]  EllipsoidRadiiUnits=m  ExtrusionCrossSection=[1 1; -1 1; -1 -1; 1 -1]  ExtrusionCrossSectionUnits=m  ExtrusionLength=1  ExtrusionLengthUnits=m  PolygonNumSides=3  PolygonOuterRadius=1  PolygonOuterRadiusUnits=m  ExtGeomFileName=15060-NLM-Doigt d''indexage Noir court M16 - 03089-5308_Défaut_sldprt.STL  ExtGeomFileUnits=mm  RevolutionCrossSection=[1 1; 1 -1; 2 -1; 2 1]  RevolutionCrossSectionUnits=m  RevolutionExtent=Full  RevolutionAngle=180  RevolutionAngleUnits=deg  BlockFunction=simmechanics.library.body_elements.solid
  F : PMIOPort  Port=1  Side=Left
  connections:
  Solid/RConn1 -- ReferenceFrame/RConn1 -- F/RConn1

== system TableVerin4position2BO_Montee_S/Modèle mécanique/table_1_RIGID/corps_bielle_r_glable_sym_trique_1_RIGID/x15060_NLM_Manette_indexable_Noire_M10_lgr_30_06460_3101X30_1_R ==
  ReferenceFrame : sm_lib/Frames and Transforms/Reference Frame  BlockFunction=simmechanics.library.frames_transforms.reference_frame
  Solid : sm_lib/Body Elements/Solid  InertiaType=Custom  Mass=0.023906899999999998  MassUnits=kg  CenterOfMass=[17.667300000000001 25.971299999999999 -0.00010288700000000001]  CenterOfMassUnits=mm  MomentsOfInertia=[9.0608299999999993 14.0336 22.147400000000001]  MomentsOfInertiaUnits=kg*mm^2  ProductsOfInertia=[-2.4169099999999999e-05 -2.4047900000000001e-05 7.6455899999999994]  ProductsOfInertiaUnits=kg*mm^2  DensityBased=on  Density=1000  DensityUnits=kg/(m^3)  GraphicType=FromGeometry  MarkerShape=Sphere  MarkerSize=10  MarkerSizeUnits=m  GraphicVisPropType=SimpleVisualProperties  GraphicDiffuseColor=[0.792157 0.819608 0.933333]  GraphicSpecularColor=[0.5 0.5 0.5 1.0]  GraphicAmbientColor=[0.15 0.15 0.15 1.0]  GraphicEmissiveColor=[0.0 0.0 0.0 1.0]  GraphicShininess=75  GraphicOpacity=1  GeometryShape=FromFile  RectangleSize=[1 1]  RectangleSizeUnits=m  BrickDimensions=[1 1 1]  BrickDimensionUnits=m  CylinderRadius=1  CylinderRadiusUnits=m  CylinderLength=1  CylinderLengthUnits=m  SphereRadius=1  SphereRadiusUnits=m  EllipsoidRadii=[1 1 1]  EllipsoidRadiiUnits=m  ExtrusionCrossSection=[1 1; -1 1; -1 -1; 1 -1]  ExtrusionCrossSectionUnits=m  ExtrusionLength=1  ExtrusionLengthUnits=m  PolygonNumSides=3  PolygonOuterRadius=1  PolygonOuterRadiusUnits=m  ExtGeomFileName=15060-NLM-Manette indexable Noire M10 lgr 30 - 06460-3101X30_Défaut_sldprt.STL  ExtGeomFileUnits=mm  RevolutionCrossSection=[1 1; 1 -1; 2 -1; 2 1]  RevolutionCrossSectionUnits=m  RevolutionExtent=Full  RevolutionAngle=180  RevolutionAngleUnits=deg  BlockFunction=simmechanics.library.body_elements.solid
  F : PMIOPort  Port=1  Side=Left
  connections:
  Solid/RConn1 -- ReferenceFrame/RConn1 -- F/RConn1

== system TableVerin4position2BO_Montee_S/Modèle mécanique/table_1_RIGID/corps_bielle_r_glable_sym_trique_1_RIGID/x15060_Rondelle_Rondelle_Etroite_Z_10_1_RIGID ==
  ReferenceFrame : sm_lib/Frames and Transforms/Reference Frame  BlockFunction=simmechanics.library.frames_transforms.reference_frame
  Solid : sm_lib/Body Elements/Solid  InertiaType=Custom  Mass=0.00045513800000000001  MassUnits=kg  CenterOfMass=[0 1 0]  CenterOfMassUnits=mm  MomentsOfInertia=[0.014666400000000001 0.029029300000000001 0.014666400000000001]  MomentsOfInertiaUnits=kg*mm^2  ProductsOfInertia=[0 0 0]  ProductsOfInertiaUnits=kg*mm^2  DensityBased=on  Density=1000  DensityUnits=kg/(m^3)  GraphicType=FromGeometry  MarkerShape=Sphere  MarkerSize=10  MarkerSizeUnits=m  GraphicVisPropType=SimpleVisualProperties  GraphicDiffuseColor=[0.792157 0.819608 0.933333]  GraphicSpecularColor=[0.5 0.5 0.5 1.0]  GraphicAmbientColor=[0.15 0.15 0.15 1.0]  GraphicEmissiveColor=[0.0 0.0 0.0 1.0]  GraphicShininess=75  GraphicOpacity=1  GeometryShape=FromFile  RectangleSize=[1 1]  RectangleSizeUnits=m  BrickDimensions=[1 1 1]  BrickDimensionUnits=m  CylinderRadius=1  CylinderRadiusUnits=m  CylinderLength=1  CylinderLengthUnits=m  SphereRadius=1  SphereRadiusUnits=m  EllipsoidRadii=[1 1 1]  EllipsoidRadiiUnits=m  ExtrusionCrossSection=[1 1; -1 1; -1 -1; 1 -1]  ExtrusionCrossSectionUnits=m  ExtrusionLength=1  ExtrusionLengthUnits=m  PolygonNumSides=3  PolygonOuterRadius=1  PolygonOuterRadiusUnits=m  ExtGeomFileName=15060-Rondelle-_Rondelle Etroite Z 10_Défaut_sldprt.STL  ExtGeomFileUnits=mm  RevolutionCrossSection=[1 1; 1 -1; 2 -1; 2 1]  RevolutionCrossSectionUnits=m  RevolutionExtent=Full  RevolutionAngle=180  RevolutionAngleUnits=deg  BlockFunction=simmechanics.library.body_elements.solid
  F : PMIOPort  Port=1  Side=Left
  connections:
  Solid/RConn1 -- ReferenceFrame/RConn1 -- F/RConn1

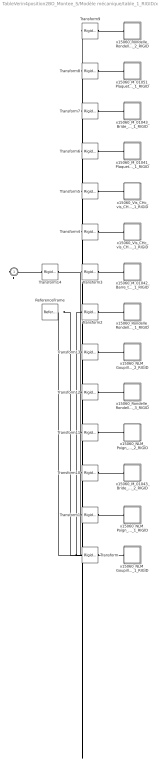
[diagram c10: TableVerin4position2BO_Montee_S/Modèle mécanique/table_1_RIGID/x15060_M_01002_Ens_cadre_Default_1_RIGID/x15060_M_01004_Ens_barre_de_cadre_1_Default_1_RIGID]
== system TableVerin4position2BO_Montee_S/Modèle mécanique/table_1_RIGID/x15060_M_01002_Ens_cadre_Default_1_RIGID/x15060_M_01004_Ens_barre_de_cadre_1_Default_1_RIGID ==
  ReferenceFrame : sm_lib/Frames and Transforms/Reference Frame  BlockFunction=simmechanics.library.frames_transforms.reference_frame
  Transform : sm_lib/Frames and Transforms/Rigid Transform  TranslationMethod=Cartesian  TranslationLengthUnit=mm  TranslationStandardAxis=+Z  TranslationStandardOffset=0  TranslationCartesianOffset=[-7.5 27.5 326]  TranslationROffset=0  TranslationROffsetUnits=m  TranslationZOffset=0  TranslationZOffsetUnits=m  TranslationThetaOffset=0  TranslationThetaOffsetUnits=deg  RotationMethod=ArbitraryAxis  RotationAngleUnits=rad  RotationStandardAxis=+Z  RotationAngle=1.6268483248229098  RotationArbitraryAxis=[-0.23032719235862154 0.23032719235862154 -0.94546219856765779]  FollAlignAxisA=+X  BaseAlignAxisA=+Y  FollAlignAxisB=+Y  BaseAlignAxisB=+Z  BlockFunction=simmechanics.library.frames_transforms.rigid_transform
  Transform1 : sm_lib/Frames and Transforms/Rigid Transform  TranslationMethod=Cartesian  TranslationLengthUnit=mm  TranslationStandardAxis=+Z  TranslationStandardOffset=0  TranslationCartesianOffset=[-25 32.5 346.5]  TranslationROffset=0  TranslationROffsetUnits=m  TranslationZOffset=0  TranslationZOffsetUnits=m  TranslationThetaOffset=0  TranslationThetaOffsetUnits=deg  RotationMethod=ArbitraryAxis  RotationAngleUnits=rad  RotationStandardAxis=+Z  RotationAngle=2.1102842595024089  RotationArbitraryAxis=[0 1 0]  FollAlignAxisA=+X  BaseAlignAxisA=+Y  FollAlignAxisB=+Y  BaseAlignAxisB=+Z  BlockFunction=simmechanics.library.frames_transforms.rigid_transform
  Transform10 : sm_lib/Frames and Transforms/Rigid Transform  TranslationMethod=Cartesian  TranslationLengthUnit=mm  TranslationStandardAxis=+Z  TranslationStandardOffset=0  TranslationCartesianOffset=[-25 27.5 336.75]  TranslationROffset=0  TranslationROffsetUnits=m  TranslationZOffset=0  TranslationZOffsetUnits=m  TranslationThetaOffset=0  TranslationThetaOffsetUnits=deg  RotationMethod=ArbitraryAxis  RotationAngleUnits=rad  RotationStandardAxis=+Z  RotationAngle=3.1415926535897931  RotationArbitraryAxis=[1.6314226234179785e-16 -0.70710678118654746 0.70710678118654757]  FollAlignAxisA=+X  BaseAlignAxisA=+Y  FollAlignAxisB=+Y  BaseAlignAxisB=+Z  BlockFunction=simmechanics.library.frames_transforms.rigid_transform
  Transform11 : sm_lib/Frames and Transforms/Rigid Transform  TranslationMethod=Cartesian  TranslationLengthUnit=mm  TranslationStandardAxis=+Z  TranslationStandardOffset=0  TranslationCartesianOffset=[-25 32.5 -346.5]  TranslationROffset=0  TranslationROffsetUnits=m  TranslationZOffset=0  TranslationZOffsetUnits=m  TranslationThetaOffset=0  TranslationThetaOffsetUnits=deg  RotationMethod=ArbitraryAxis  RotationAngleUnits=rad  RotationStandardAxis=+Z  RotationAngle=2.027787680848903  RotationArbitraryAxis=[0 1 0]  FollAlignAxisA=+X  BaseAlignAxisA=+Y  FollAlignAxisB=+Y  BaseAlignAxisB=+Z  BlockFunction=simmechanics.library.frames_transforms.rigid_transform
  Transform12 : sm_lib/Frames and Transforms/Rigid Transform  TranslationMethod=Cartesian  TranslationLengthUnit=mm  TranslationStandardAxis=+Z  TranslationStandardOffset=0  TranslationCartesianOffset=[10 0 320.19999999999999]  TranslationROffset=0  TranslationROffsetUnits=m  TranslationZOffset=0  TranslationZOffsetUnits=m  TranslationThetaOffset=0  TranslationThetaOffsetUnits=deg  RotationMethod=ArbitraryAxis  RotationAngleUnits=rad  RotationStandardAxis=+Z  RotationAngle=1.7685721393722891  RotationArbitraryAxis=[0.8194860460643737 0.40524228574136939 0.40524228574136928]  FollAlignAxisA=+X  BaseAlignAxisA=+Y  FollAlignAxisB=+Y  BaseAlignAxisB=+Z  BlockFunction=simmechanics.library.frames_transforms.rigid_transform
  Transform13 : sm_lib/Frames and Transforms/Rigid Transform  TranslationMethod=Cartesian  TranslationLengthUnit=mm  TranslationStandardAxis=+Z  TranslationStandardOffset=0  TranslationCartesianOffset=[-42.5 27.5 326]  TranslationROffset=0  TranslationROffsetUnits=m  TranslationZOffset=0  TranslationZOffsetUnits=m  TranslationThetaOffset=0  TranslationThetaOffsetUnits=deg  RotationMethod=ArbitraryAxis  RotationAngleUnits=rad  RotationStandardAxis=+Z  RotationAngle=1.8965497273291418  RotationArbitraryAxis=[0.49237916771694989 -0.49237916771694989 -0.71772244663012141]  FollAlignAxisA=+X  BaseAlignAxisA=+Y  FollAlignAxisB=+Y  BaseAlignAxisB=+Z  BlockFunction=simmechanics.library.frames_transforms.rigid_transform
  Transform14 : sm_lib/Frames and Transforms/Rigid Transform  TranslationMethod=Cartesian  TranslationLengthUnit=mm  TranslationStandardAxis=+Z  TranslationStandardOffset=0  TranslationCartesianOffset=[-4.5114999999999996e-09 22.5 -175.97099999999998]  TranslationROffset=0  TranslationROffsetUnits=m  TranslationZOffset=0  TranslationZOffsetUnits=m  TranslationThetaOffset=0  TranslationThetaOffsetUnits=deg  RotationMethod=ArbitraryAxis  RotationAngleUnits=rad  RotationStandardAxis=+Z  RotationAngle=1.5707963267948968  RotationArbitraryAxis=[4.011544999999999e-16 1 -2.9273449999999995e-16]  FollAlignAxisA=+X  BaseAlignAxisA=+Y  FollAlignAxisB=+Y  BaseAlignAxisB=+Z  BlockFunction=simmechanics.library.frames_transforms.rigid_transform
  Transform2 : sm_lib/Frames and Transforms/Rigid Transform  TranslationMethod=Cartesian  TranslationLengthUnit=mm  TranslationStandardAxis=+Z  TranslationStandardOffset=0  TranslationCartesianOffset=[-10 0 -321]  TranslationROffset=0  TranslationROffsetUnits=m  TranslationZOffset=0  TranslationZOffsetUnits=m  TranslationThetaOffset=0  TranslationThetaOffsetUnits=deg  RotationMethod=ArbitraryAxis  RotationAngleUnits=rad  RotationStandardAxis=+Z  RotationAngle=1.7685721393722891  RotationArbitraryAxis=[0.8194860460643737 0.40524228574136939 0.40524228574136928]  FollAlignAxisA=+X  BaseAlignAxisA=+Y  FollAlignAxisB=+Y  BaseAlignAxisB=+Z  BlockFunction=simmechanics.library.frames_transforms.rigid_transform
  Transform3 : sm_lib/Frames and Transforms/Rigid Transform  TranslationMethod=None  TranslationLengthUnit=m  TranslationStandardAxis=+Z  TranslationStandardOffset=0  TranslationCartesianOffset=[0 0 0]  TranslationROffset=0  TranslationROffsetUnits=m  TranslationZOffset=0  TranslationZOffsetUnits=m  TranslationThetaOffset=0  TranslationThetaOffsetUnits=deg  RotationMethod=None  RotationAngleUnits=deg  RotationStandardAxis=+Z  RotationAngle=0  RotationArbitraryAxis=[0 0 1]  FollAlignAxisA=+X  BaseAlignAxisA=+Y  FollAlignAxisB=+Y  BaseAlignAxisB=+Z  BlockFunction=simmechanics.library.frames_transforms.rigid_transform
  Transform4 : sm_lib/Frames and Transforms/Rigid Transform  TranslationMethod=Cartesian  TranslationLengthUnit=mm  TranslationStandardAxis=+Z  TranslationStandardOffset=0  TranslationCartesianOffset=[-60 27.099999999999998 -326]  TranslationROffset=0  TranslationROffsetUnits=m  TranslationZOffset=0  TranslationZOffsetUnits=m  TranslationThetaOffset=0  TranslationThetaOffsetUnits=deg  RotationMethod=ArbitraryAxis  RotationAngleUnits=rad  RotationStandardAxis=+Z  RotationAngle=2.5194254432888998  RotationArbitraryAxis=[0.32152271397417787 0.66956073077752953 -0.66956073077752953]  FollAlignAxisA=+X  BaseAlignAxisA=+Y  FollAlignAxisB=+Y  BaseAlignAxisB=+Z  BlockFunction=simmechanics.library.frames_transforms.rigid_transform
  Transform5 : sm_lib/Frames and Transforms/Rigid Transform  TranslationMethod=Cartesian  TranslationLengthUnit=mm  TranslationStandardAxis=+Z  TranslationStandardOffset=0  TranslationCartesianOffset=[-10 0 -316.19999999999999]  TranslationROffset=0  TranslationROffsetUnits=m  TranslationZOffset=0  TranslationZOffsetUnits=m  TranslationThetaOffset=0  TranslationThetaOffsetUnits=deg  RotationMethod=ArbitraryAxis  RotationAngleUnits=rad  RotationStandardAxis=+Z  RotationAngle=3.1415926535897931  RotationArbitraryAxis=[0.66186296474968098 0.74962485010354518 0]  FollAlignAxisA=+X  BaseAlignAxisA=+Y  FollAlignAxisB=+Y  BaseAlignAxisB=+Z  BlockFunction=simmechanics.library.frames_transforms.rigid_transform
  Transform6 : sm_lib/Frames and Transforms/Rigid Transform  TranslationMethod=Cartesian  TranslationLengthUnit=mm  TranslationStandardAxis=+Z  TranslationStandardOffset=0  TranslationCartesianOffset=[-25 0 -331]  TranslationROffset=0  TranslationROffsetUnits=m  TranslationZOffset=0  TranslationZOffsetUnits=m  TranslationThetaOffset=0  TranslationThetaOffsetUnits=deg  RotationMethod=None  RotationAngleUnits=deg  RotationStandardAxis=+Z  RotationAngle=0  RotationArbitraryAxis=[0 0 1]  FollAlignAxisA=+X  BaseAlignAxisA=+Y  FollAlignAxisB=+Y  BaseAlignAxisB=+Z  BlockFunction=simmechanics.library.frames_transforms.rigid_transform
  Transform7 : sm_lib/Frames and Transforms/Rigid Transform  TranslationMethod=Cartesian  TranslationLengthUnit=mm  TranslationStandardAxis=+Z  TranslationStandardOffset=0  TranslationCartesianOffset=[-25 27.5 -336.75]  TranslationROffset=0  TranslationROffsetUnits=m  TranslationZOffset=0  TranslationZOffsetUnits=m  TranslationThetaOffset=0  TranslationThetaOffsetUnits=deg  RotationMethod=ArbitraryAxis  RotationAngleUnits=rad  RotationStandardAxis=+Z  RotationAngle=1.5707963267948968  RotationArbitraryAxis=[1 6.5055000000000021e-18 -1.149255e-16]  FollAlignAxisA=+X  BaseAlignAxisA=+Y  FollAlignAxisB=+Y  BaseAlignAxisB=+Z  BlockFunction=simmechanics.library.frames_transforms.rigid_transform
  Transform8 : sm_lib/Frames and Transforms/Rigid Transform  TranslationMethod=Cartesian  TranslationLengthUnit=mm  TranslationStandardAxis=+Z  TranslationStandardOffset=0  TranslationCartesianOffset=[-25 0 331]  TranslationROffset=0  TranslationROffsetUnits=m  TranslationZOffset=0  TranslationZOffsetUnits=m  TranslationThetaOffset=0  TranslationThetaOffsetUnits=deg  RotationMethod=None  RotationAngleUnits=deg  RotationStandardAxis=+Z  RotationAngle=0  RotationArbitraryAxis=[0 0 1]  FollAlignAxisA=+X  BaseAlignAxisA=+Y  FollAlignAxisB=+Y  BaseAlignAxisB=+Z  BlockFunction=simmechanics.library.frames_transforms.rigid_transform
  Transform9 : sm_lib/Frames and Transforms/Rigid Transform  TranslationMethod=Cartesian  TranslationLengthUnit=mm  TranslationStandardAxis=+Z  TranslationStandardOffset=0  TranslationCartesianOffset=[10 0 -321]  TranslationROffset=0  TranslationROffsetUnits=m  TranslationZOffset=0  TranslationZOffsetUnits=m  TranslationThetaOffset=0  TranslationThetaOffsetUnits=deg  RotationMethod=ArbitraryAxis  RotationAngleUnits=rad  RotationStandardAxis=+Z  RotationAngle=1.7685721393722891  RotationArbitraryAxis=[0.8194860460643737 0.40524228574136939 0.40524228574136928]  FollAlignAxisA=+X  BaseAlignAxisA=+Y  FollAlignAxisB=+Y  BaseAlignAxisB=+Z  BlockFunction=simmechanics.library.frames_transforms.rigid_transform
  x15060_M_01041_Plaquette_sur_glissiere_AA_DEFAULT_1_RIGID : Subsystem
  x15060_M_01042_Barre_transversale_AA_DEFAULT_1_RIGID : Subsystem
  x15060_M_01043_Bride_de_barre_AA_DEFAULT_1_RIGID : Subsystem
  x15060_M_01043_Bride_de_barre_AA_DEFAULT_2_RIGID : Subsystem
  x15060_M_01051_Plaquette_sur_glissiere_SYM_AA_DEFAULT_1_RIGID : Subsystem
  x15060_NLM_Goupille_cyl_3_Lgr_16_03320_03x16_AA_DEFAULT_1_RIGID : Subsystem
  x15060_NLM_Goupille_cyl_3_Lgr_16_03320_03x16_AA_DEFAULT_2_RIGID : Subsystem
  x15060_NLM_Poign_e_Miniwing_M6_06652_006_X_15_1_RIGID : Subsystem
  x15060_NLM_Poign_e_Miniwing_M6_06652_006_X_15_2_RIGID : Subsystem
  x15060_Rondelle_Rondelle_Etroite_Z_4_1_RIGID : Subsystem
  x15060_Rondelle_Rondelle_Etroite_Z_4_2_RIGID : Subsystem
  x15060_Rondelle_Rondelle_Etroite_Z_4_3_RIGID : Subsystem
  x15060_Vis_CHc_vis_CHc_M_4_X_12_1_RIGID : Subsystem
  x15060_Vis_CHc_vis_CHc_M_4_X_16_1_RIGID : Subsystem
  F : PMIOPort  Port=1  Side=Right
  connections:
  Transform/RConn1 -- x15060_NLM_Goupille_cyl_3_Lgr_16_03320_03x16_AA_DEFAULT_1_RIGID/LConn1
  Transform1/RConn1 -- x15060_NLM_Poign_e_Miniwing_M6_06652_006_X_15_1_RIGID/LConn1
  Transform10/RConn1 -- x15060_M_01043_Bride_de_barre_AA_DEFAULT_2_RIGID/LConn1
  Transform11/RConn1 -- x15060_NLM_Poign_e_Miniwing_M6_06652_006_X_15_2_RIGID/LConn1
  Transform12/RConn1 -- x15060_Rondelle_Rondelle_Etroite_Z_4_3_RIGID/LConn1
  Transform13/RConn1 -- x15060_NLM_Goupille_cyl_3_Lgr_16_03320_03x16_AA_DEFAULT_2_RIGID/LConn1
  Transform/LConn1 -- ReferenceFrame/RConn1 -- Transform1/LConn1 -- Transform10/LConn1 -- Transform11/LConn1 -- Transform12/LConn1 -- Transform13/LConn1 -- Transform14/RConn1 -- Transform2/LConn1 -- Transform3/LConn1 -- Transform4/LConn1 -- Transform5/LConn1 -- Transform6/LConn1 -- Transform7/LConn1 -- Transform8/LConn1 -- Transform9/LConn1
  Transform14/LConn1 -- F/RConn1
  Transform2/RConn1 -- x15060_Rondelle_Rondelle_Etroite_Z_4_1_RIGID/LConn1
  Transform3/RConn1 -- x15060_M_01042_Barre_transversale_AA_DEFAULT_1_RIGID/LConn1
  Transform4/RConn1 -- x15060_Vis_CHc_vis_CHc_M_4_X_16_1_RIGID/LConn1
  Transform5/RConn1 -- x15060_Vis_CHc_vis_CHc_M_4_X_12_1_RIGID/LConn1
  Transform6/RConn1 -- x15060_M_01041_Plaquette_sur_glissiere_AA_DEFAULT_1_RIGID/LConn1
  Transform7/RConn1 -- x15060_M_01043_Bride_de_barre_AA_DEFAULT_1_RIGID/LConn1
  Transform8/RConn1 -- x15060_M_01051_Plaquette_sur_glissiere_SYM_AA_DEFAULT_1_RIGID/LConn1
  Transform9/RConn1 -- x15060_Rondelle_Rondelle_Etroite_Z_4_2_RIGID/LConn1

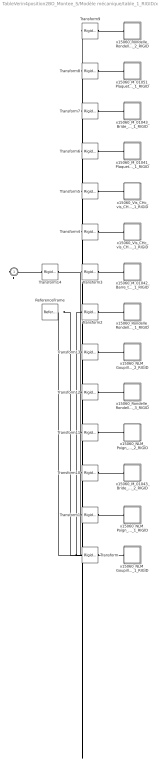
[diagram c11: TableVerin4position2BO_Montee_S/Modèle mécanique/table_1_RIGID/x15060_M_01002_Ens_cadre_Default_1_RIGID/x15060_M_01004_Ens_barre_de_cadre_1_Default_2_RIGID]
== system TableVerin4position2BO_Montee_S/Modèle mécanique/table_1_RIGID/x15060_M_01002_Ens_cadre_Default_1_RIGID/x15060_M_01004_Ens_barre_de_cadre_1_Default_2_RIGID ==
  ReferenceFrame : sm_lib/Frames and Transforms/Reference Frame  BlockFunction=simmechanics.library.frames_transforms.reference_frame
  Transform : sm_lib/Frames and Transforms/Rigid Transform  TranslationMethod=Cartesian  TranslationLengthUnit=mm  TranslationStandardAxis=+Z  TranslationStandardOffset=0  TranslationCartesianOffset=[-7.5 27.5 326]  TranslationROffset=0  TranslationROffsetUnits=m  TranslationZOffset=0  TranslationZOffsetUnits=m  TranslationThetaOffset=0  TranslationThetaOffsetUnits=deg  RotationMethod=ArbitraryAxis  RotationAngleUnits=rad  RotationStandardAxis=+Z  RotationAngle=1.6268483248229098  RotationArbitraryAxis=[-0.23032719235862154 0.23032719235862154 -0.94546219856765779]  FollAlignAxisA=+X  BaseAlignAxisA=+Y  FollAlignAxisB=+Y  BaseAlignAxisB=+Z  BlockFunction=simmechanics.library.frames_transforms.rigid_transform
  Transform1 : sm_lib/Frames and Transforms/Rigid Transform  TranslationMethod=Cartesian  TranslationLengthUnit=mm  TranslationStandardAxis=+Z  TranslationStandardOffset=0  TranslationCartesianOffset=[-25 32.5 346.5]  TranslationROffset=0  TranslationROffsetUnits=m  TranslationZOffset=0  TranslationZOffsetUnits=m  TranslationThetaOffset=0  TranslationThetaOffsetUnits=deg  RotationMethod=ArbitraryAxis  RotationAngleUnits=rad  RotationStandardAxis=+Z  RotationAngle=2.1102842595024089  RotationArbitraryAxis=[0 1 0]  FollAlignAxisA=+X  BaseAlignAxisA=+Y  FollAlignAxisB=+Y  BaseAlignAxisB=+Z  BlockFunction=simmechanics.library.frames_transforms.rigid_transform
  Transform10 : sm_lib/Frames and Transforms/Rigid Transform  TranslationMethod=Cartesian  TranslationLengthUnit=mm  TranslationStandardAxis=+Z  TranslationStandardOffset=0  TranslationCartesianOffset=[-25 27.5 336.75]  TranslationROffset=0  TranslationROffsetUnits=m  TranslationZOffset=0  TranslationZOffsetUnits=m  TranslationThetaOffset=0  TranslationThetaOffsetUnits=deg  RotationMethod=ArbitraryAxis  RotationAngleUnits=rad  RotationStandardAxis=+Z  RotationAngle=3.1415926535897931  RotationArbitraryAxis=[1.6314226234179785e-16 -0.70710678118654746 0.70710678118654757]  FollAlignAxisA=+X  BaseAlignAxisA=+Y  FollAlignAxisB=+Y  BaseAlignAxisB=+Z  BlockFunction=simmechanics.library.frames_transforms.rigid_transform
  Transform11 : sm_lib/Frames and Transforms/Rigid Transform  TranslationMethod=Cartesian  TranslationLengthUnit=mm  TranslationStandardAxis=+Z  TranslationStandardOffset=0  TranslationCartesianOffset=[-25 32.5 -346.5]  TranslationROffset=0  TranslationROffsetUnits=m  TranslationZOffset=0  TranslationZOffsetUnits=m  TranslationThetaOffset=0  TranslationThetaOffsetUnits=deg  RotationMethod=ArbitraryAxis  RotationAngleUnits=rad  RotationStandardAxis=+Z  RotationAngle=2.027787680848903  RotationArbitraryAxis=[0 1 0]  FollAlignAxisA=+X  BaseAlignAxisA=+Y  FollAlignAxisB=+Y  BaseAlignAxisB=+Z  BlockFunction=simmechanics.library.frames_transforms.rigid_transform
  Transform12 : sm_lib/Frames and Transforms/Rigid Transform  TranslationMethod=Cartesian  TranslationLengthUnit=mm  TranslationStandardAxis=+Z  TranslationStandardOffset=0  TranslationCartesianOffset=[10 0 320.19999999999999]  TranslationROffset=0  TranslationROffsetUnits=m  TranslationZOffset=0  TranslationZOffsetUnits=m  TranslationThetaOffset=0  TranslationThetaOffsetUnits=deg  RotationMethod=ArbitraryAxis  RotationAngleUnits=rad  RotationStandardAxis=+Z  RotationAngle=1.7685721393722891  RotationArbitraryAxis=[0.8194860460643737 0.40524228574136939 0.40524228574136922]  FollAlignAxisA=+X  BaseAlignAxisA=+Y  FollAlignAxisB=+Y  BaseAlignAxisB=+Z  BlockFunction=simmechanics.library.frames_transforms.rigid_transform
  Transform13 : sm_lib/Frames and Transforms/Rigid Transform  TranslationMethod=Cartesian  TranslationLengthUnit=mm  TranslationStandardAxis=+Z  TranslationStandardOffset=0  TranslationCartesianOffset=[-42.5 27.5 326]  TranslationROffset=0  TranslationROffsetUnits=m  TranslationZOffset=0  TranslationZOffsetUnits=m  TranslationThetaOffset=0  TranslationThetaOffsetUnits=deg  RotationMethod=ArbitraryAxis  RotationAngleUnits=rad  RotationStandardAxis=+Z  RotationAngle=1.8965497273291418  RotationArbitraryAxis=[0.49237916771694989 -0.49237916771694989 -0.71772244663012141]  FollAlignAxisA=+X  BaseAlignAxisA=+Y  FollAlignAxisB=+Y  BaseAlignAxisB=+Z  BlockFunction=simmechanics.library.frames_transforms.rigid_transform
  Transform14 : sm_lib/Frames and Transforms/Rigid Transform  TranslationMethod=Cartesian  TranslationLengthUnit=mm  TranslationStandardAxis=+Z  TranslationStandardOffset=0  TranslationCartesianOffset=[-1.4726899999999999e-07 22.5 228.898]  TranslationROffset=0  TranslationROffsetUnits=m  TranslationZOffset=0  TranslationZOffsetUnits=m  TranslationThetaOffset=0  TranslationThetaOffsetUnits=deg  RotationMethod=ArbitraryAxis  RotationAngleUnits=rad  RotationStandardAxis=+Z  RotationAngle=1.5707963267948968  RotationArbitraryAxis=[-2.2204449999999998e-16 -1 -2.2204449999999998e-16]  FollAlignAxisA=+X  BaseAlignAxisA=+Y  FollAlignAxisB=+Y  BaseAlignAxisB=+Z  BlockFunction=simmechanics.library.frames_transforms.rigid_transform
  Transform2 : sm_lib/Frames and Transforms/Rigid Transform  TranslationMethod=Cartesian  TranslationLengthUnit=mm  TranslationStandardAxis=+Z  TranslationStandardOffset=0  TranslationCartesianOffset=[-10 0 -321]  TranslationROffset=0  TranslationROffsetUnits=m  TranslationZOffset=0  TranslationZOffsetUnits=m  TranslationThetaOffset=0  TranslationThetaOffsetUnits=deg  RotationMethod=ArbitraryAxis  RotationAngleUnits=rad  RotationStandardAxis=+Z  RotationAngle=1.7685721393722891  RotationArbitraryAxis=[0.8194860460643737 0.40524228574136939 0.40524228574136922]  FollAlignAxisA=+X  BaseAlignAxisA=+Y  FollAlignAxisB=+Y  BaseAlignAxisB=+Z  BlockFunction=simmechanics.library.frames_transforms.rigid_transform
  Transform3 : sm_lib/Frames and Transforms/Rigid Transform  TranslationMethod=None  TranslationLengthUnit=m  TranslationStandardAxis=+Z  TranslationStandardOffset=0  TranslationCartesianOffset=[0 0 0]  TranslationROffset=0  TranslationROffsetUnits=m  TranslationZOffset=0  TranslationZOffsetUnits=m  TranslationThetaOffset=0  TranslationThetaOffsetUnits=deg  RotationMethod=None  RotationAngleUnits=deg  RotationStandardAxis=+Z  RotationAngle=0  RotationArbitraryAxis=[0 0 1]  FollAlignAxisA=+X  BaseAlignAxisA=+Y  FollAlignAxisB=+Y  BaseAlignAxisB=+Z  BlockFunction=simmechanics.library.frames_transforms.rigid_transform
  Transform4 : sm_lib/Frames and Transforms/Rigid Transform  TranslationMethod=Cartesian  TranslationLengthUnit=mm  TranslationStandardAxis=+Z  TranslationStandardOffset=0  TranslationCartesianOffset=[-60 27.099999999999998 -326]  TranslationROffset=0  TranslationROffsetUnits=m  TranslationZOffset=0  TranslationZOffsetUnits=m  TranslationThetaOffset=0  TranslationThetaOffsetUnits=deg  RotationMethod=ArbitraryAxis  RotationAngleUnits=rad  RotationStandardAxis=+Z  RotationAngle=2.5194254432888998  RotationArbitraryAxis=[0.32152271397417787 0.66956073077752953 -0.66956073077752953]  FollAlignAxisA=+X  BaseAlignAxisA=+Y  FollAlignAxisB=+Y  BaseAlignAxisB=+Z  BlockFunction=simmechanics.library.frames_transforms.rigid_transform
  Transform5 : sm_lib/Frames and Transforms/Rigid Transform  TranslationMethod=Cartesian  TranslationLengthUnit=mm  TranslationStandardAxis=+Z  TranslationStandardOffset=0  TranslationCartesianOffset=[-10 0 -316.19999999999999]  TranslationROffset=0  TranslationROffsetUnits=m  TranslationZOffset=0  TranslationZOffsetUnits=m  TranslationThetaOffset=0  TranslationThetaOffsetUnits=deg  RotationMethod=ArbitraryAxis  RotationAngleUnits=rad  RotationStandardAxis=+Z  RotationAngle=3.1415926535897931  RotationArbitraryAxis=[0.66186296474968098 0.74962485010354518 0]  FollAlignAxisA=+X  BaseAlignAxisA=+Y  FollAlignAxisB=+Y  BaseAlignAxisB=+Z  BlockFunction=simmechanics.library.frames_transforms.rigid_transform
  Transform6 : sm_lib/Frames and Transforms/Rigid Transform  TranslationMethod=Cartesian  TranslationLengthUnit=mm  TranslationStandardAxis=+Z  TranslationStandardOffset=0  TranslationCartesianOffset=[-25 0 -331]  TranslationROffset=0  TranslationROffsetUnits=m  TranslationZOffset=0  TranslationZOffsetUnits=m  TranslationThetaOffset=0  TranslationThetaOffsetUnits=deg  RotationMethod=None  RotationAngleUnits=deg  RotationStandardAxis=+Z  RotationAngle=0  RotationArbitraryAxis=[0 0 1]  FollAlignAxisA=+X  BaseAlignAxisA=+Y  FollAlignAxisB=+Y  BaseAlignAxisB=+Z  BlockFunction=simmechanics.library.frames_transforms.rigid_transform
  Transform7 : sm_lib/Frames and Transforms/Rigid Transform  TranslationMethod=Cartesian  TranslationLengthUnit=mm  TranslationStandardAxis=+Z  TranslationStandardOffset=0  TranslationCartesianOffset=[-25 27.5 -336.75]  TranslationROffset=0  TranslationROffsetUnits=m  TranslationZOffset=0  TranslationZOffsetUnits=m  TranslationThetaOffset=0  TranslationThetaOffsetUnits=deg  RotationMethod=ArbitraryAxis  RotationAngleUnits=rad  RotationStandardAxis=+Z  RotationAngle=1.5707963267948968  RotationArbitraryAxis=[1 6.5055000000000021e-18 -1.149255e-16]  FollAlignAxisA=+X  BaseAlignAxisA=+Y  FollAlignAxisB=+Y  BaseAlignAxisB=+Z  BlockFunction=simmechanics.library.frames_transforms.rigid_transform
  Transform8 : sm_lib/Frames and Transforms/Rigid Transform  TranslationMethod=Cartesian  TranslationLengthUnit=mm  TranslationStandardAxis=+Z  TranslationStandardOffset=0  TranslationCartesianOffset=[-25 0 331]  TranslationROffset=0  TranslationROffsetUnits=m  TranslationZOffset=0  TranslationZOffsetUnits=m  TranslationThetaOffset=0  TranslationThetaOffsetUnits=deg  RotationMethod=None  RotationAngleUnits=deg  RotationStandardAxis=+Z  RotationAngle=0  RotationArbitraryAxis=[0 0 1]  FollAlignAxisA=+X  BaseAlignAxisA=+Y  FollAlignAxisB=+Y  BaseAlignAxisB=+Z  BlockFunction=simmechanics.library.frames_transforms.rigid_transform
  Transform9 : sm_lib/Frames and Transforms/Rigid Transform  TranslationMethod=Cartesian  TranslationLengthUnit=mm  TranslationStandardAxis=+Z  TranslationStandardOffset=0  TranslationCartesianOffset=[10 0 -321]  TranslationROffset=0  TranslationROffsetUnits=m  TranslationZOffset=0  TranslationZOffsetUnits=m  TranslationThetaOffset=0  TranslationThetaOffsetUnits=deg  RotationMethod=ArbitraryAxis  RotationAngleUnits=rad  RotationStandardAxis=+Z  RotationAngle=1.7685721393722891  RotationArbitraryAxis=[0.8194860460643737 0.40524228574136939 0.40524228574136922]  FollAlignAxisA=+X  BaseAlignAxisA=+Y  FollAlignAxisB=+Y  BaseAlignAxisB=+Z  BlockFunction=simmechanics.library.frames_transforms.rigid_transform
  x15060_M_01041_Plaquette_sur_glissiere_AA_DEFAULT_1_RIGID : Subsystem
  x15060_M_01042_Barre_transversale_AA_DEFAULT_1_RIGID : Subsystem
  x15060_M_01043_Bride_de_barre_AA_DEFAULT_1_RIGID : Subsystem
  x15060_M_01043_Bride_de_barre_AA_DEFAULT_2_RIGID : Subsystem
  x15060_M_01051_Plaquette_sur_glissiere_SYM_AA_DEFAULT_1_RIGID : Subsystem
  x15060_NLM_Goupille_cyl_3_Lgr_16_03320_03x16_AA_DEFAULT_1_RIGID : Subsystem
  x15060_NLM_Goupille_cyl_3_Lgr_16_03320_03x16_AA_DEFAULT_2_RIGID : Subsystem
  x15060_NLM_Poign_e_Miniwing_M6_06652_006_X_15_1_RIGID : Subsystem
  x15060_NLM_Poign_e_Miniwing_M6_06652_006_X_15_2_RIGID : Subsystem
  x15060_Rondelle_Rondelle_Etroite_Z_4_1_RIGID : Subsystem
  x15060_Rondelle_Rondelle_Etroite_Z_4_2_RIGID : Subsystem
  x15060_Rondelle_Rondelle_Etroite_Z_4_3_RIGID : Subsystem
  x15060_Vis_CHc_vis_CHc_M_4_X_12_1_RIGID : Subsystem
  x15060_Vis_CHc_vis_CHc_M_4_X_16_1_RIGID : Subsystem
  F : PMIOPort  Port=1  Side=Right
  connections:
  Transform/RConn1 -- x15060_NLM_Goupille_cyl_3_Lgr_16_03320_03x16_AA_DEFAULT_1_RIGID/LConn1
  Transform1/RConn1 -- x15060_NLM_Poign_e_Miniwing_M6_06652_006_X_15_1_RIGID/LConn1
  Transform10/RConn1 -- x15060_M_01043_Bride_de_barre_AA_DEFAULT_2_RIGID/LConn1
  Transform11/RConn1 -- x15060_NLM_Poign_e_Miniwing_M6_06652_006_X_15_2_RIGID/LConn1
  Transform12/RConn1 -- x15060_Rondelle_Rondelle_Etroite_Z_4_3_RIGID/LConn1
  Transform13/RConn1 -- x15060_NLM_Goupille_cyl_3_Lgr_16_03320_03x16_AA_DEFAULT_2_RIGID/LConn1
  Transform/LConn1 -- ReferenceFrame/RConn1 -- Transform1/LConn1 -- Transform10/LConn1 -- Transform11/LConn1 -- Transform12/LConn1 -- Transform13/LConn1 -- Transform14/RConn1 -- Transform2/LConn1 -- Transform3/LConn1 -- Transform4/LConn1 -- Transform5/LConn1 -- Transform6/LConn1 -- Transform7/LConn1 -- Transform8/LConn1 -- Transform9/LConn1
  Transform14/LConn1 -- F/RConn1
  Transform2/RConn1 -- x15060_Rondelle_Rondelle_Etroite_Z_4_1_RIGID/LConn1
  Transform3/RConn1 -- x15060_M_01042_Barre_transversale_AA_DEFAULT_1_RIGID/LConn1
  Transform4/RConn1 -- x15060_Vis_CHc_vis_CHc_M_4_X_16_1_RIGID/LConn1
  Transform5/RConn1 -- x15060_Vis_CHc_vis_CHc_M_4_X_12_1_RIGID/LConn1
  Transform6/RConn1 -- x15060_M_01041_Plaquette_sur_glissiere_AA_DEFAULT_1_RIGID/LConn1
  Transform7/RConn1 -- x15060_M_01043_Bride_de_barre_AA_DEFAULT_1_RIGID/LConn1
  Transform8/RConn1 -- x15060_M_01051_Plaquette_sur_glissiere_SYM_AA_DEFAULT_1_RIGID/LConn1
  Transform9/RConn1 -- x15060_Rondelle_Rondelle_Etroite_Z_4_2_RIGID/LConn1

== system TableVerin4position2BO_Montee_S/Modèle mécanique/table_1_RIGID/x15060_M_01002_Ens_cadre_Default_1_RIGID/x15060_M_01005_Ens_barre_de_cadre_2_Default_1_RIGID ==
  ReferenceFrame : sm_lib/Frames and Transforms/Reference Frame  BlockFunction=simmechanics.library.frames_transforms.reference_frame
  Transform : sm_lib/Frames and Transforms/Rigid Transform  TranslationMethod=None  TranslationLengthUnit=m  TranslationStandardAxis=+Z  TranslationStandardOffset=0  TranslationCartesianOffset=[0 0 0]  TranslationROffset=0  TranslationROffsetUnits=m  TranslationZOffset=0  TranslationZOffsetUnits=m  TranslationThetaOffset=0  TranslationThetaOffsetUnits=deg  RotationMethod=None  RotationAngleUnits=deg  RotationStandardAxis=+Z  RotationAngle=0  RotationArbitraryAxis=[0 0 1]  FollAlignAxisA=+X  BaseAlignAxisA=+Y  FollAlignAxisB=+Y  BaseAlignAxisB=+Z  BlockFunction=simmechanics.library.frames_transforms.rigid_transform
  Transform1 : sm_lib/Frames and Transforms/Rigid Transform  TranslationMethod=Cartesian  TranslationLengthUnit=mm  TranslationStandardAxis=+Z  TranslationStandardOffset=0  TranslationCartesianOffset=[42.5 56.5 -326]  TranslationROffset=0  TranslationROffsetUnits=m  TranslationZOffset=0  TranslationZOffsetUnits=m  TranslationThetaOffset=0  TranslationThetaOffsetUnits=deg  RotationMethod=ArbitraryAxis  RotationAngleUnits=rad  RotationStandardAxis=+Z  RotationAngle=1.7467406108938903  RotationArbitraryAxis=[-0.3859580756948327 -0.38595807569483265 0.83789780260595248]  FollAlignAxisA=+X  BaseAlignAxisA=+Y  FollAlignAxisB=+Y  BaseAlignAxisB=+Z  BlockFunction=simmechanics.library.frames_transforms.rigid_transform
  Transform10 : sm_lib/Frames and Transforms/Rigid Transform  TranslationMethod=Cartesian  TranslationLengthUnit=mm  TranslationStandardAxis=+Z  TranslationStandardOffset=0  TranslationCartesianOffset=[10 0 321]  TranslationROffset=0  TranslationROffsetUnits=m  TranslationZOffset=0  TranslationZOffsetUnits=m  TranslationThetaOffset=0  TranslationThetaOffsetUnits=deg  RotationMethod=ArbitraryAxis  RotationAngleUnits=rad  RotationStandardAxis=+Z  RotationAngle=1.5777292164721624  RotationArbitraryAxis=[-0.99309103220519346 0.082976507981545794 -0.082976507981545988]  FollAlignAxisA=+X  BaseAlignAxisA=+Y  FollAlignAxisB=+Y  BaseAlignAxisB=+Z  BlockFunction=simmechanics.library.frames_transforms.rigid_transform
  Transform11 : sm_lib/Frames and Transforms/Rigid Transform  TranslationMethod=Cartesian  TranslationLengthUnit=mm  TranslationStandardAxis=+Z  TranslationStandardOffset=0  TranslationCartesianOffset=[25 72.5 336.75]  TranslationROffset=0  TranslationROffsetUnits=m  TranslationZOffset=0  TranslationZOffsetUnits=m  TranslationThetaOffset=0  TranslationThetaOffsetUnits=deg  RotationMethod=ArbitraryAxis  RotationAngleUnits=rad  RotationStandardAxis=+Z  RotationAngle=3.1415926535897931  RotationArbitraryAxis=[1.6314226234179785e-16 -0.70710678118654746 0.70710678118654757]  FollAlignAxisA=+X  BaseAlignAxisA=+Y  FollAlignAxisB=+Y  BaseAlignAxisB=+Z  BlockFunction=simmechanics.library.frames_transforms.rigid_transform
  Transform12 : sm_lib/Frames and Transforms/Rigid Transform  TranslationMethod=Cartesian  TranslationLengthUnit=mm  TranslationStandardAxis=+Z  TranslationStandardOffset=0  TranslationCartesianOffset=[210.06299999999999 -22.5 1.22052e-08]  TranslationROffset=0  TranslationROffsetUnits=m  TranslationZOffset=0  TranslationZOffsetUnits=m  TranslationThetaOffset=0  TranslationThetaOffsetUnits=deg  RotationMethod=None  RotationAngleUnits=deg  RotationStandardAxis=+Z  RotationAngle=0  RotationArbitraryAxis=[0 0 1]  FollAlignAxisA=+X  BaseAlignAxisA=+Y  FollAlignAxisB=+Y  BaseAlignAxisB=+Z  BlockFunction=simmechanics.library.frames_transforms.rigid_transform
  Transform2 : sm_lib/Frames and Transforms/Rigid Transform  TranslationMethod=Cartesian  TranslationLengthUnit=mm  TranslationStandardAxis=+Z  TranslationStandardOffset=0  TranslationCartesianOffset=[25 0 -331]  TranslationROffset=0  TranslationROffsetUnits=m  TranslationZOffset=0  TranslationZOffsetUnits=m  TranslationThetaOffset=0  TranslationThetaOffsetUnits=deg  RotationMethod=ArbitraryAxis  RotationAngleUnits=rad  RotationStandardAxis=+Z  RotationAngle=3.1415926535897931  RotationArbitraryAxis=[0 1 0]  FollAlignAxisA=+X  BaseAlignAxisA=+Y  FollAlignAxisB=+Y  BaseAlignAxisB=+Z  BlockFunction=simmechanics.library.frames_transforms.rigid_transform
  Transform3 : sm_lib/Frames and Transforms/Rigid Transform  TranslationMethod=Cartesian  TranslationLengthUnit=mm  TranslationStandardAxis=+Z  TranslationStandardOffset=0  TranslationCartesianOffset=[25 77.5 -346.5]  TranslationROffset=0  TranslationROffsetUnits=m  TranslationZOffset=0  TranslationZOffsetUnits=m  TranslationThetaOffset=0  TranslationThetaOffsetUnits=deg  RotationMethod=ArbitraryAxis  RotationAngleUnits=rad  RotationStandardAxis=+Z  RotationAngle=0.95951428278210815  RotationArbitraryAxis=[0 1 0]  FollAlignAxisA=+X  BaseAlignAxisA=+Y  FollAlignAxisB=+Y  BaseAlignAxisB=+Z  BlockFunction=simmechanics.library.frames_transforms.rigid_transform
  Transform4 : sm_lib/Frames and Transforms/Rigid Transform  TranslationMethod=Cartesian  TranslationLengthUnit=mm  TranslationStandardAxis=+Z  TranslationStandardOffset=0  TranslationCartesianOffset=[7.5 56.5 -326]  TranslationROffset=0  TranslationROffsetUnits=m  TranslationZOffset=0  TranslationZOffsetUnits=m  TranslationThetaOffset=0  TranslationThetaOffsetUnits=deg  RotationMethod=ArbitraryAxis  RotationAngleUnits=rad  RotationStandardAxis=+Z  RotationAngle=1.7467406108938903  RotationArbitraryAxis=[-0.3859580756948327 -0.38595807569483265 0.83789780260595248]  FollAlignAxisA=+X  BaseAlignAxisA=+Y  FollAlignAxisB=+Y  BaseAlignAxisB=+Z  BlockFunction=simmechanics.library.frames_transforms.rigid_transform
  Transform5 : sm_lib/Frames and Transforms/Rigid Transform  TranslationMethod=Cartesian  TranslationLengthUnit=mm  TranslationStandardAxis=+Z  TranslationStandardOffset=0  TranslationCartesianOffset=[-10 0 -320.19999999999999]  TranslationROffset=0  TranslationROffsetUnits=m  TranslationZOffset=0  TranslationZOffsetUnits=m  TranslationThetaOffset=0  TranslationThetaOffsetUnits=deg  RotationMethod=ArbitraryAxis  RotationAngleUnits=rad  RotationStandardAxis=+Z  RotationAngle=1.5777292164721624  RotationArbitraryAxis=[-0.99309103220519346 0.082976507981545794 -0.082976507981545988]  FollAlignAxisA=+X  BaseAlignAxisA=+Y  FollAlignAxisB=+Y  BaseAlignAxisB=+Z  BlockFunction=simmechanics.library.frames_transforms.rigid_transform
  Transform6 : sm_lib/Frames and Transforms/Rigid Transform  TranslationMethod=Cartesian  TranslationLengthUnit=mm  TranslationStandardAxis=+Z  TranslationStandardOffset=0  TranslationCartesianOffset=[25 0 331]  TranslationROffset=0  TranslationROffsetUnits=m  TranslationZOffset=0  TranslationZOffsetUnits=m  TranslationThetaOffset=0  TranslationThetaOffsetUnits=deg  RotationMethod=ArbitraryAxis  RotationAngleUnits=rad  RotationStandardAxis=+Z  RotationAngle=3.1415926535897931  RotationArbitraryAxis=[-1.110225e-16 1 0]  FollAlignAxisA=+X  BaseAlignAxisA=+Y  FollAlignAxisB=+Y  BaseAlignAxisB=+Z  BlockFunction=simmechanics.library.frames_transforms.rigid_transform
  Transform7 : sm_lib/Frames and Transforms/Rigid Transform  TranslationMethod=Cartesian  TranslationLengthUnit=mm  TranslationStandardAxis=+Z  TranslationStandardOffset=0  TranslationCartesianOffset=[25 77.5 346.5]  TranslationROffset=0  TranslationROffsetUnits=m  TranslationZOffset=0  TranslationZOffsetUnits=m  TranslationThetaOffset=0  TranslationThetaOffsetUnits=deg  RotationMethod=ArbitraryAxis  RotationAngleUnits=rad  RotationStandardAxis=+Z  RotationAngle=1.5193660168733383  RotationArbitraryAxis=[0 -1 0]  FollAlignAxisA=+X  BaseAlignAxisA=+Y  FollAlignAxisB=+Y  BaseAlignAxisB=+Z  BlockFunction=simmechanics.library.frames_transforms.rigid_transform
  Transform8 : sm_lib/Frames and Transforms/Rigid Transform  TranslationMethod=Cartesian  TranslationLengthUnit=mm  TranslationStandardAxis=+Z  TranslationStandardOffset=0  TranslationCartesianOffset=[25 72.5 -336.75]  TranslationROffset=0  TranslationROffsetUnits=m  TranslationZOffset=0  TranslationZOffsetUnits=m  TranslationThetaOffset=0  TranslationThetaOffsetUnits=deg  RotationMethod=ArbitraryAxis  RotationAngleUnits=rad  RotationStandardAxis=+Z  RotationAngle=1.5707963267948968  RotationArbitraryAxis=[1 6.0715499999999988e-17 -6.0715499999999988e-17]  FollAlignAxisA=+X  BaseAlignAxisA=+Y  FollAlignAxisB=+Y  BaseAlignAxisB=+Z  BlockFunction=simmechanics.library.frames_transforms.rigid_transform
  Transform9 : sm_lib/Frames and Transforms/Rigid Transform  TranslationMethod=Cartesian  TranslationLengthUnit=mm  TranslationStandardAxis=+Z  TranslationStandardOffset=0  TranslationCartesianOffset=[-10 0 321]  TranslationROffset=0  TranslationROffsetUnits=m  TranslationZOffset=0  TranslationZOffsetUnits=m  TranslationThetaOffset=0  TranslationThetaOffsetUnits=deg  RotationMethod=ArbitraryAxis  RotationAngleUnits=rad  RotationStandardAxis=+Z  RotationAngle=1.5777292164721624  RotationArbitraryAxis=[-0.99309103220519346 0.082976507981545794 -0.082976507981545988]  FollAlignAxisA=+X  BaseAlignAxisA=+Y  FollAlignAxisB=+Y  BaseAlignAxisB=+Z  BlockFunction=simmechanics.library.frames_transforms.rigid_transform
  x15060_M_01029_Plaquette_haute_sur_glissiere_AA_DEFAULT_1_RIGID : Subsystem
  x15060_M_01042_Barre_transversale_AA_DEFAULT_1_RIGID : Subsystem
  x15060_M_01043_Bride_de_barre_AA_DEFAULT_1_RIGID : Subsystem
  x15060_M_01043_Bride_de_barre_AA_DEFAULT_2_RIGID : Subsystem
  x15060_M_01053_Plaquette_haute_sur_glissiere_SYM_AA_DEFAULT_1_R : Subsystem
  x15060_NLM_Goupille_cyl_3_Lgr_16_03320_03x16_AA_DEFAULT_1_RIGID : Subsystem
  x15060_NLM_Goupille_cyl_3_Lgr_16_03320_03x16_AA_DEFAULT_2_RIGID : Subsystem
  x15060_NLM_Poign_e_Miniwing_M6_06652_006_X_15_1_RIGID : Subsystem
  x15060_NLM_Poign_e_Miniwing_M6_06652_006_X_15_2_RIGID : Subsystem
  x15060_Rondelle_Rondelle_Etroite_Z_4_1_RIGID : Subsystem
  x15060_Rondelle_Rondelle_Etroite_Z_4_2_RIGID : Subsystem
  x15060_Rondelle_Rondelle_Etroite_Z_4_3_RIGID : Subsystem
  F : PMIOPort  Port=1  Side=Right
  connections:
  Transform/RConn1 -- x15060_M_01042_Barre_transversale_AA_DEFAULT_1_RIGID/LConn1
  Transform1/RConn1 -- x15060_NLM_Goupille_cyl_3_Lgr_16_03320_03x16_AA_DEFAULT_1_RIGID/LConn1
  Transform10/RConn1 -- x15060_Rondelle_Rondelle_Etroite_Z_4_3_RIGID/LConn1
  Transform11/RConn1 -- x15060_M_01043_Bride_de_barre_AA_DEFAULT_2_RIGID/LConn1
  Transform/LConn1 -- ReferenceFrame/RConn1 -- Transform1/LConn1 -- Transform10/LConn1 -- Transform11/LConn1 -- Transform12/RConn1 -- Transform2/LConn1 -- Transform3/LConn1 -- Transform4/LConn1 -- Transform5/LConn1 -- Transform6/LConn1 -- Transform7/LConn1 -- Transform8/LConn1 -- Transform9/LConn1
  Transform12/LConn1 -- F/RConn1
  Transform2/RConn1 -- x15060_M_01053_Plaquette_haute_sur_glissiere_SYM_AA_DEFAULT_1_R/LConn1
  Transform3/RConn1 -- x15060_NLM_Poign_e_Miniwing_M6_06652_006_X_15_1_RIGID/LConn1
  Transform4/RConn1 -- x15060_NLM_Goupille_cyl_3_Lgr_16_03320_03x16_AA_DEFAULT_2_RIGID/LConn1
  Transform5/RConn1 -- x15060_Rondelle_Rondelle_Etroite_Z_4_1_RIGID/LConn1
  Transform6/RConn1 -- x15060_M_01029_Plaquette_haute_sur_glissiere_AA_DEFAULT_1_RIGID/LConn1
  Transform7/RConn1 -- x15060_NLM_Poign_e_Miniwing_M6_06652_006_X_15_2_RIGID/LConn1
  Transform8/RConn1 -- x15060_M_01043_Bride_de_barre_AA_DEFAULT_1_RIGID/LConn1
  Transform9/RConn1 -- x15060_Rondelle_Rondelle_Etroite_Z_4_2_RIGID/LConn1
